VERSION 5.8 ;
BUSBITCHARS "[]" ;
DIVIDERCHAR "/" ;
UNITS
    DATABASE MICRONS 1000 ;
END UNITS

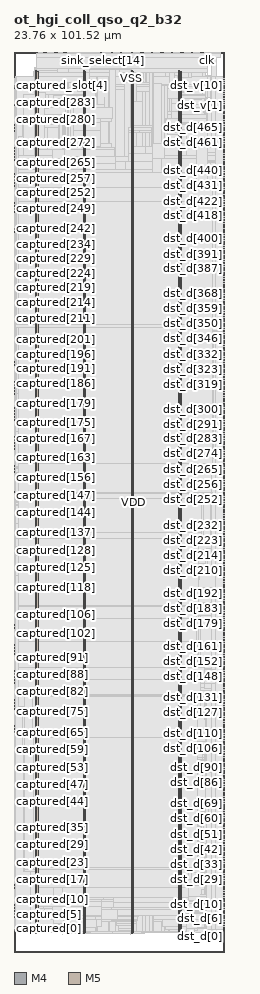
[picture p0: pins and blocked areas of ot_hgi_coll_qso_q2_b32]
MACRO ot_hgi_coll_qso_q2_b32
  FOREIGN ot_hgi_coll_qso_q2_b32 0 0 ;
  CLASS BLOCK ;
  SIZE 23.76 BY 101.52 ;
  PIN captured[0]
    DIRECTION INPUT ;
    USE SIGNAL ;
    PORT
      LAYER M4 ;
        RECT  0 2.64 0.084 2.664 ;
    END
  END captured[0]
  PIN captured[100]
    DIRECTION INPUT ;
    USE SIGNAL ;
    PORT
      LAYER M4 ;
        RECT  0 35.232 0.084 35.256 ;
    END
  END captured[100]
  PIN captured[101]
    DIRECTION INPUT ;
    USE SIGNAL ;
    PORT
      LAYER M4 ;
        RECT  0 35.568 0.084 35.592 ;
    END
  END captured[101]
  PIN captured[102]
    DIRECTION INPUT ;
    USE SIGNAL ;
    PORT
      LAYER M4 ;
        RECT  0 35.904 0.084 35.928 ;
    END
  END captured[102]
  PIN captured[103]
    DIRECTION INPUT ;
    USE SIGNAL ;
    PORT
      LAYER M4 ;
        RECT  0 36.24 0.084 36.264 ;
    END
  END captured[103]
  PIN captured[104]
    DIRECTION INPUT ;
    USE SIGNAL ;
    PORT
      LAYER M4 ;
        RECT  0 36.528 0.084 36.552 ;
    END
  END captured[104]
  PIN captured[105]
    DIRECTION INPUT ;
    USE SIGNAL ;
    PORT
      LAYER M4 ;
        RECT  0 36.864 0.084 36.888 ;
    END
  END captured[105]
  PIN captured[106]
    DIRECTION INPUT ;
    USE SIGNAL ;
    PORT
      LAYER M4 ;
        RECT  0 37.2 0.084 37.224 ;
    END
  END captured[106]
  PIN captured[107]
    DIRECTION INPUT ;
    USE SIGNAL ;
    PORT
      LAYER M4 ;
        RECT  0 37.536 0.084 37.56 ;
    END
  END captured[107]
  PIN captured[108]
    DIRECTION INPUT ;
    USE SIGNAL ;
    PORT
      LAYER M4 ;
        RECT  0 37.872 0.084 37.896 ;
    END
  END captured[108]
  PIN captured[109]
    DIRECTION INPUT ;
    USE SIGNAL ;
    PORT
      LAYER M4 ;
        RECT  0 38.16 0.084 38.184 ;
    END
  END captured[109]
  PIN captured[10]
    DIRECTION INPUT ;
    USE SIGNAL ;
    PORT
      LAYER M4 ;
        RECT  0 5.904 0.084 5.928 ;
    END
  END captured[10]
  PIN captured[110]
    DIRECTION INPUT ;
    USE SIGNAL ;
    PORT
      LAYER M4 ;
        RECT  0 38.496 0.084 38.52 ;
    END
  END captured[110]
  PIN captured[111]
    DIRECTION INPUT ;
    USE SIGNAL ;
    PORT
      LAYER M4 ;
        RECT  0 38.832 0.084 38.856 ;
    END
  END captured[111]
  PIN captured[112]
    DIRECTION INPUT ;
    USE SIGNAL ;
    PORT
      LAYER M4 ;
        RECT  0 39.168 0.084 39.192 ;
    END
  END captured[112]
  PIN captured[113]
    DIRECTION INPUT ;
    USE SIGNAL ;
    PORT
      LAYER M4 ;
        RECT  0 39.504 0.084 39.528 ;
    END
  END captured[113]
  PIN captured[114]
    DIRECTION INPUT ;
    USE SIGNAL ;
    PORT
      LAYER M4 ;
        RECT  0 39.792 0.084 39.816 ;
    END
  END captured[114]
  PIN captured[115]
    DIRECTION INPUT ;
    USE SIGNAL ;
    PORT
      LAYER M4 ;
        RECT  0 40.128 0.084 40.152 ;
    END
  END captured[115]
  PIN captured[116]
    DIRECTION INPUT ;
    USE SIGNAL ;
    PORT
      LAYER M4 ;
        RECT  0 40.464 0.084 40.488 ;
    END
  END captured[116]
  PIN captured[117]
    DIRECTION INPUT ;
    USE SIGNAL ;
    PORT
      LAYER M4 ;
        RECT  0 40.8 0.084 40.824 ;
    END
  END captured[117]
  PIN captured[118]
    DIRECTION INPUT ;
    USE SIGNAL ;
    PORT
      LAYER M4 ;
        RECT  0 41.136 0.084 41.16 ;
    END
  END captured[118]
  PIN captured[119]
    DIRECTION INPUT ;
    USE SIGNAL ;
    PORT
      LAYER M4 ;
        RECT  0 41.424 0.084 41.448 ;
    END
  END captured[119]
  PIN captured[11]
    DIRECTION INPUT ;
    USE SIGNAL ;
    PORT
      LAYER M4 ;
        RECT  0 6.24 0.084 6.264 ;
    END
  END captured[11]
  PIN captured[120]
    DIRECTION INPUT ;
    USE SIGNAL ;
    PORT
      LAYER M4 ;
        RECT  0 41.76 0.084 41.784 ;
    END
  END captured[120]
  PIN captured[121]
    DIRECTION INPUT ;
    USE SIGNAL ;
    PORT
      LAYER M4 ;
        RECT  0 42.096 0.084 42.12 ;
    END
  END captured[121]
  PIN captured[122]
    DIRECTION INPUT ;
    USE SIGNAL ;
    PORT
      LAYER M4 ;
        RECT  0 42.432 0.084 42.456 ;
    END
  END captured[122]
  PIN captured[123]
    DIRECTION INPUT ;
    USE SIGNAL ;
    PORT
      LAYER M4 ;
        RECT  0 42.72 0.084 42.744 ;
    END
  END captured[123]
  PIN captured[124]
    DIRECTION INPUT ;
    USE SIGNAL ;
    PORT
      LAYER M4 ;
        RECT  0 43.056 0.084 43.08 ;
    END
  END captured[124]
  PIN captured[125]
    DIRECTION INPUT ;
    USE SIGNAL ;
    PORT
      LAYER M4 ;
        RECT  0 43.392 0.084 43.416 ;
    END
  END captured[125]
  PIN captured[126]
    DIRECTION INPUT ;
    USE SIGNAL ;
    PORT
      LAYER M4 ;
        RECT  0 43.728 0.084 43.752 ;
    END
  END captured[126]
  PIN captured[127]
    DIRECTION INPUT ;
    USE SIGNAL ;
    PORT
      LAYER M4 ;
        RECT  0 44.064 0.084 44.088 ;
    END
  END captured[127]
  PIN captured[128]
    DIRECTION INPUT ;
    USE SIGNAL ;
    PORT
      LAYER M4 ;
        RECT  0 44.352 0.084 44.376 ;
    END
  END captured[128]
  PIN captured[129]
    DIRECTION INPUT ;
    USE SIGNAL ;
    PORT
      LAYER M4 ;
        RECT  0 44.688 0.084 44.712 ;
    END
  END captured[129]
  PIN captured[12]
    DIRECTION INPUT ;
    USE SIGNAL ;
    PORT
      LAYER M4 ;
        RECT  0 6.576 0.084 6.6 ;
    END
  END captured[12]
  PIN captured[130]
    DIRECTION INPUT ;
    USE SIGNAL ;
    PORT
      LAYER M4 ;
        RECT  0 45.024 0.084 45.048 ;
    END
  END captured[130]
  PIN captured[131]
    DIRECTION INPUT ;
    USE SIGNAL ;
    PORT
      LAYER M4 ;
        RECT  0 45.36 0.084 45.384 ;
    END
  END captured[131]
  PIN captured[132]
    DIRECTION INPUT ;
    USE SIGNAL ;
    PORT
      LAYER M4 ;
        RECT  0 45.696 0.084 45.72 ;
    END
  END captured[132]
  PIN captured[133]
    DIRECTION INPUT ;
    USE SIGNAL ;
    PORT
      LAYER M4 ;
        RECT  0 45.984 0.084 46.008 ;
    END
  END captured[133]
  PIN captured[134]
    DIRECTION INPUT ;
    USE SIGNAL ;
    PORT
      LAYER M4 ;
        RECT  0 46.32 0.084 46.344 ;
    END
  END captured[134]
  PIN captured[135]
    DIRECTION INPUT ;
    USE SIGNAL ;
    PORT
      LAYER M4 ;
        RECT  0 46.656 0.084 46.68 ;
    END
  END captured[135]
  PIN captured[136]
    DIRECTION INPUT ;
    USE SIGNAL ;
    PORT
      LAYER M4 ;
        RECT  0 46.992 0.084 47.016 ;
    END
  END captured[136]
  PIN captured[137]
    DIRECTION INPUT ;
    USE SIGNAL ;
    PORT
      LAYER M4 ;
        RECT  0 47.328 0.084 47.352 ;
    END
  END captured[137]
  PIN captured[138]
    DIRECTION INPUT ;
    USE SIGNAL ;
    PORT
      LAYER M4 ;
        RECT  0 47.616 0.084 47.64 ;
    END
  END captured[138]
  PIN captured[139]
    DIRECTION INPUT ;
    USE SIGNAL ;
    PORT
      LAYER M4 ;
        RECT  0 47.952 0.084 47.976 ;
    END
  END captured[139]
  PIN captured[13]
    DIRECTION INPUT ;
    USE SIGNAL ;
    PORT
      LAYER M4 ;
        RECT  0 6.912 0.084 6.936 ;
    END
  END captured[13]
  PIN captured[140]
    DIRECTION INPUT ;
    USE SIGNAL ;
    PORT
      LAYER M4 ;
        RECT  0 48.288 0.084 48.312 ;
    END
  END captured[140]
  PIN captured[141]
    DIRECTION INPUT ;
    USE SIGNAL ;
    PORT
      LAYER M4 ;
        RECT  0 48.624 0.084 48.648 ;
    END
  END captured[141]
  PIN captured[142]
    DIRECTION INPUT ;
    USE SIGNAL ;
    PORT
      LAYER M4 ;
        RECT  0 48.912 0.084 48.936 ;
    END
  END captured[142]
  PIN captured[143]
    DIRECTION INPUT ;
    USE SIGNAL ;
    PORT
      LAYER M4 ;
        RECT  0 49.248 0.084 49.272 ;
    END
  END captured[143]
  PIN captured[144]
    DIRECTION INPUT ;
    USE SIGNAL ;
    PORT
      LAYER M4 ;
        RECT  0 49.584 0.084 49.608 ;
    END
  END captured[144]
  PIN captured[145]
    DIRECTION INPUT ;
    USE SIGNAL ;
    PORT
      LAYER M4 ;
        RECT  0 49.92 0.084 49.944 ;
    END
  END captured[145]
  PIN captured[146]
    DIRECTION INPUT ;
    USE SIGNAL ;
    PORT
      LAYER M4 ;
        RECT  0 50.256 0.084 50.28 ;
    END
  END captured[146]
  PIN captured[147]
    DIRECTION INPUT ;
    USE SIGNAL ;
    PORT
      LAYER M4 ;
        RECT  0 50.544 0.084 50.568 ;
    END
  END captured[147]
  PIN captured[148]
    DIRECTION INPUT ;
    USE SIGNAL ;
    PORT
      LAYER M4 ;
        RECT  0 50.88 0.084 50.904 ;
    END
  END captured[148]
  PIN captured[149]
    DIRECTION INPUT ;
    USE SIGNAL ;
    PORT
      LAYER M4 ;
        RECT  0 51.216 0.084 51.24 ;
    END
  END captured[149]
  PIN captured[14]
    DIRECTION INPUT ;
    USE SIGNAL ;
    PORT
      LAYER M4 ;
        RECT  0 7.2 0.084 7.224 ;
    END
  END captured[14]
  PIN captured[150]
    DIRECTION INPUT ;
    USE SIGNAL ;
    PORT
      LAYER M4 ;
        RECT  0 51.552 0.084 51.576 ;
    END
  END captured[150]
  PIN captured[151]
    DIRECTION INPUT ;
    USE SIGNAL ;
    PORT
      LAYER M4 ;
        RECT  0 51.888 0.084 51.912 ;
    END
  END captured[151]
  PIN captured[152]
    DIRECTION INPUT ;
    USE SIGNAL ;
    PORT
      LAYER M4 ;
        RECT  0 52.176 0.084 52.2 ;
    END
  END captured[152]
  PIN captured[153]
    DIRECTION INPUT ;
    USE SIGNAL ;
    PORT
      LAYER M4 ;
        RECT  0 52.512 0.084 52.536 ;
    END
  END captured[153]
  PIN captured[154]
    DIRECTION INPUT ;
    USE SIGNAL ;
    PORT
      LAYER M4 ;
        RECT  0 52.848 0.084 52.872 ;
    END
  END captured[154]
  PIN captured[155]
    DIRECTION INPUT ;
    USE SIGNAL ;
    PORT
      LAYER M4 ;
        RECT  0 53.184 0.084 53.208 ;
    END
  END captured[155]
  PIN captured[156]
    DIRECTION INPUT ;
    USE SIGNAL ;
    PORT
      LAYER M4 ;
        RECT  0 53.52 0.084 53.544 ;
    END
  END captured[156]
  PIN captured[157]
    DIRECTION INPUT ;
    USE SIGNAL ;
    PORT
      LAYER M4 ;
        RECT  0 53.808 0.084 53.832 ;
    END
  END captured[157]
  PIN captured[158]
    DIRECTION INPUT ;
    USE SIGNAL ;
    PORT
      LAYER M4 ;
        RECT  0 54.144 0.084 54.168 ;
    END
  END captured[158]
  PIN captured[159]
    DIRECTION INPUT ;
    USE SIGNAL ;
    PORT
      LAYER M4 ;
        RECT  0 54.48 0.084 54.504 ;
    END
  END captured[159]
  PIN captured[15]
    DIRECTION INPUT ;
    USE SIGNAL ;
    PORT
      LAYER M4 ;
        RECT  0 7.536 0.084 7.56 ;
    END
  END captured[15]
  PIN captured[160]
    DIRECTION INPUT ;
    USE SIGNAL ;
    PORT
      LAYER M4 ;
        RECT  0 54.816 0.084 54.84 ;
    END
  END captured[160]
  PIN captured[161]
    DIRECTION INPUT ;
    USE SIGNAL ;
    PORT
      LAYER M4 ;
        RECT  0 55.104 0.084 55.128 ;
    END
  END captured[161]
  PIN captured[162]
    DIRECTION INPUT ;
    USE SIGNAL ;
    PORT
      LAYER M4 ;
        RECT  0 55.44 0.084 55.464 ;
    END
  END captured[162]
  PIN captured[163]
    DIRECTION INPUT ;
    USE SIGNAL ;
    PORT
      LAYER M4 ;
        RECT  0 55.776 0.084 55.8 ;
    END
  END captured[163]
  PIN captured[164]
    DIRECTION INPUT ;
    USE SIGNAL ;
    PORT
      LAYER M4 ;
        RECT  0 56.112 0.084 56.136 ;
    END
  END captured[164]
  PIN captured[165]
    DIRECTION INPUT ;
    USE SIGNAL ;
    PORT
      LAYER M4 ;
        RECT  0 56.448 0.084 56.472 ;
    END
  END captured[165]
  PIN captured[166]
    DIRECTION INPUT ;
    USE SIGNAL ;
    PORT
      LAYER M4 ;
        RECT  0 56.736 0.084 56.76 ;
    END
  END captured[166]
  PIN captured[167]
    DIRECTION INPUT ;
    USE SIGNAL ;
    PORT
      LAYER M4 ;
        RECT  0 57.072 0.084 57.096 ;
    END
  END captured[167]
  PIN captured[168]
    DIRECTION INPUT ;
    USE SIGNAL ;
    PORT
      LAYER M4 ;
        RECT  0 57.408 0.084 57.432 ;
    END
  END captured[168]
  PIN captured[169]
    DIRECTION INPUT ;
    USE SIGNAL ;
    PORT
      LAYER M4 ;
        RECT  0 57.744 0.084 57.768 ;
    END
  END captured[169]
  PIN captured[16]
    DIRECTION INPUT ;
    USE SIGNAL ;
    PORT
      LAYER M4 ;
        RECT  0 7.872 0.084 7.896 ;
    END
  END captured[16]
  PIN captured[170]
    DIRECTION INPUT ;
    USE SIGNAL ;
    PORT
      LAYER M4 ;
        RECT  0 58.08 0.084 58.104 ;
    END
  END captured[170]
  PIN captured[171]
    DIRECTION INPUT ;
    USE SIGNAL ;
    PORT
      LAYER M4 ;
        RECT  0 58.368 0.084 58.392 ;
    END
  END captured[171]
  PIN captured[172]
    DIRECTION INPUT ;
    USE SIGNAL ;
    PORT
      LAYER M4 ;
        RECT  0 58.704 0.084 58.728 ;
    END
  END captured[172]
  PIN captured[173]
    DIRECTION INPUT ;
    USE SIGNAL ;
    PORT
      LAYER M4 ;
        RECT  0 59.04 0.084 59.064 ;
    END
  END captured[173]
  PIN captured[174]
    DIRECTION INPUT ;
    USE SIGNAL ;
    PORT
      LAYER M4 ;
        RECT  0 59.376 0.084 59.4 ;
    END
  END captured[174]
  PIN captured[175]
    DIRECTION INPUT ;
    USE SIGNAL ;
    PORT
      LAYER M4 ;
        RECT  0 59.712 0.084 59.736 ;
    END
  END captured[175]
  PIN captured[176]
    DIRECTION INPUT ;
    USE SIGNAL ;
    PORT
      LAYER M4 ;
        RECT  0 60 0.084 60.024 ;
    END
  END captured[176]
  PIN captured[177]
    DIRECTION INPUT ;
    USE SIGNAL ;
    PORT
      LAYER M4 ;
        RECT  0 60.336 0.084 60.36 ;
    END
  END captured[177]
  PIN captured[178]
    DIRECTION INPUT ;
    USE SIGNAL ;
    PORT
      LAYER M4 ;
        RECT  0 60.672 0.084 60.696 ;
    END
  END captured[178]
  PIN captured[179]
    DIRECTION INPUT ;
    USE SIGNAL ;
    PORT
      LAYER M4 ;
        RECT  0 61.008 0.084 61.032 ;
    END
  END captured[179]
  PIN captured[17]
    DIRECTION INPUT ;
    USE SIGNAL ;
    PORT
      LAYER M4 ;
        RECT  0 8.208 0.084 8.232 ;
    END
  END captured[17]
  PIN captured[180]
    DIRECTION INPUT ;
    USE SIGNAL ;
    PORT
      LAYER M4 ;
        RECT  0 61.344 0.084 61.368 ;
    END
  END captured[180]
  PIN captured[181]
    DIRECTION INPUT ;
    USE SIGNAL ;
    PORT
      LAYER M4 ;
        RECT  0 61.632 0.084 61.656 ;
    END
  END captured[181]
  PIN captured[182]
    DIRECTION INPUT ;
    USE SIGNAL ;
    PORT
      LAYER M4 ;
        RECT  0 61.968 0.084 61.992 ;
    END
  END captured[182]
  PIN captured[183]
    DIRECTION INPUT ;
    USE SIGNAL ;
    PORT
      LAYER M4 ;
        RECT  0 62.304 0.084 62.328 ;
    END
  END captured[183]
  PIN captured[184]
    DIRECTION INPUT ;
    USE SIGNAL ;
    PORT
      LAYER M4 ;
        RECT  0 62.64 0.084 62.664 ;
    END
  END captured[184]
  PIN captured[185]
    DIRECTION INPUT ;
    USE SIGNAL ;
    PORT
      LAYER M4 ;
        RECT  0 62.928 0.084 62.952 ;
    END
  END captured[185]
  PIN captured[186]
    DIRECTION INPUT ;
    USE SIGNAL ;
    PORT
      LAYER M4 ;
        RECT  0 63.264 0.084 63.288 ;
    END
  END captured[186]
  PIN captured[187]
    DIRECTION INPUT ;
    USE SIGNAL ;
    PORT
      LAYER M4 ;
        RECT  0 63.6 0.084 63.624 ;
    END
  END captured[187]
  PIN captured[188]
    DIRECTION INPUT ;
    USE SIGNAL ;
    PORT
      LAYER M4 ;
        RECT  0 63.936 0.084 63.96 ;
    END
  END captured[188]
  PIN captured[189]
    DIRECTION INPUT ;
    USE SIGNAL ;
    PORT
      LAYER M4 ;
        RECT  0 64.272 0.084 64.296 ;
    END
  END captured[189]
  PIN captured[18]
    DIRECTION INPUT ;
    USE SIGNAL ;
    PORT
      LAYER M4 ;
        RECT  0 8.496 0.084 8.52 ;
    END
  END captured[18]
  PIN captured[190]
    DIRECTION INPUT ;
    USE SIGNAL ;
    PORT
      LAYER M4 ;
        RECT  0 64.56 0.084 64.584 ;
    END
  END captured[190]
  PIN captured[191]
    DIRECTION INPUT ;
    USE SIGNAL ;
    PORT
      LAYER M4 ;
        RECT  0 64.896 0.084 64.92 ;
    END
  END captured[191]
  PIN captured[192]
    DIRECTION INPUT ;
    USE SIGNAL ;
    PORT
      LAYER M4 ;
        RECT  0 65.232 0.084 65.256 ;
    END
  END captured[192]
  PIN captured[193]
    DIRECTION INPUT ;
    USE SIGNAL ;
    PORT
      LAYER M4 ;
        RECT  0 65.568 0.084 65.592 ;
    END
  END captured[193]
  PIN captured[194]
    DIRECTION INPUT ;
    USE SIGNAL ;
    PORT
      LAYER M4 ;
        RECT  0 65.904 0.084 65.928 ;
    END
  END captured[194]
  PIN captured[195]
    DIRECTION INPUT ;
    USE SIGNAL ;
    PORT
      LAYER M4 ;
        RECT  0 66.192 0.084 66.216 ;
    END
  END captured[195]
  PIN captured[196]
    DIRECTION INPUT ;
    USE SIGNAL ;
    PORT
      LAYER M4 ;
        RECT  0 66.528 0.084 66.552 ;
    END
  END captured[196]
  PIN captured[197]
    DIRECTION INPUT ;
    USE SIGNAL ;
    PORT
      LAYER M4 ;
        RECT  0 66.864 0.084 66.888 ;
    END
  END captured[197]
  PIN captured[198]
    DIRECTION INPUT ;
    USE SIGNAL ;
    PORT
      LAYER M4 ;
        RECT  0 67.2 0.084 67.224 ;
    END
  END captured[198]
  PIN captured[199]
    DIRECTION INPUT ;
    USE SIGNAL ;
    PORT
      LAYER M4 ;
        RECT  0 67.536 0.084 67.56 ;
    END
  END captured[199]
  PIN captured[19]
    DIRECTION INPUT ;
    USE SIGNAL ;
    PORT
      LAYER M4 ;
        RECT  0 8.832 0.084 8.856 ;
    END
  END captured[19]
  PIN captured[1]
    DIRECTION INPUT ;
    USE SIGNAL ;
    PORT
      LAYER M4 ;
        RECT  0 2.976 0.084 3 ;
    END
  END captured[1]
  PIN captured[200]
    DIRECTION INPUT ;
    USE SIGNAL ;
    PORT
      LAYER M4 ;
        RECT  0 67.824 0.084 67.848 ;
    END
  END captured[200]
  PIN captured[201]
    DIRECTION INPUT ;
    USE SIGNAL ;
    PORT
      LAYER M4 ;
        RECT  0 68.16 0.084 68.184 ;
    END
  END captured[201]
  PIN captured[202]
    DIRECTION INPUT ;
    USE SIGNAL ;
    PORT
      LAYER M4 ;
        RECT  0 68.496 0.084 68.52 ;
    END
  END captured[202]
  PIN captured[203]
    DIRECTION INPUT ;
    USE SIGNAL ;
    PORT
      LAYER M4 ;
        RECT  0 68.832 0.084 68.856 ;
    END
  END captured[203]
  PIN captured[204]
    DIRECTION INPUT ;
    USE SIGNAL ;
    PORT
      LAYER M4 ;
        RECT  0 69.12 0.084 69.144 ;
    END
  END captured[204]
  PIN captured[205]
    DIRECTION INPUT ;
    USE SIGNAL ;
    PORT
      LAYER M4 ;
        RECT  0 69.456 0.084 69.48 ;
    END
  END captured[205]
  PIN captured[206]
    DIRECTION INPUT ;
    USE SIGNAL ;
    PORT
      LAYER M4 ;
        RECT  0 69.792 0.084 69.816 ;
    END
  END captured[206]
  PIN captured[207]
    DIRECTION INPUT ;
    USE SIGNAL ;
    PORT
      LAYER M4 ;
        RECT  0 70.128 0.084 70.152 ;
    END
  END captured[207]
  PIN captured[208]
    DIRECTION INPUT ;
    USE SIGNAL ;
    PORT
      LAYER M4 ;
        RECT  0 70.464 0.084 70.488 ;
    END
  END captured[208]
  PIN captured[209]
    DIRECTION INPUT ;
    USE SIGNAL ;
    PORT
      LAYER M4 ;
        RECT  0 70.752 0.084 70.776 ;
    END
  END captured[209]
  PIN captured[20]
    DIRECTION INPUT ;
    USE SIGNAL ;
    PORT
      LAYER M4 ;
        RECT  0 9.168 0.084 9.192 ;
    END
  END captured[20]
  PIN captured[210]
    DIRECTION INPUT ;
    USE SIGNAL ;
    PORT
      LAYER M4 ;
        RECT  0 71.088 0.084 71.112 ;
    END
  END captured[210]
  PIN captured[211]
    DIRECTION INPUT ;
    USE SIGNAL ;
    PORT
      LAYER M4 ;
        RECT  0 71.424 0.084 71.448 ;
    END
  END captured[211]
  PIN captured[212]
    DIRECTION INPUT ;
    USE SIGNAL ;
    PORT
      LAYER M4 ;
        RECT  0 71.76 0.084 71.784 ;
    END
  END captured[212]
  PIN captured[213]
    DIRECTION INPUT ;
    USE SIGNAL ;
    PORT
      LAYER M4 ;
        RECT  0 72.096 0.084 72.12 ;
    END
  END captured[213]
  PIN captured[214]
    DIRECTION INPUT ;
    USE SIGNAL ;
    PORT
      LAYER M4 ;
        RECT  0 72.384 0.084 72.408 ;
    END
  END captured[214]
  PIN captured[215]
    DIRECTION INPUT ;
    USE SIGNAL ;
    PORT
      LAYER M4 ;
        RECT  0 72.72 0.084 72.744 ;
    END
  END captured[215]
  PIN captured[216]
    DIRECTION INPUT ;
    USE SIGNAL ;
    PORT
      LAYER M4 ;
        RECT  0 73.056 0.084 73.08 ;
    END
  END captured[216]
  PIN captured[217]
    DIRECTION INPUT ;
    USE SIGNAL ;
    PORT
      LAYER M4 ;
        RECT  0 73.392 0.084 73.416 ;
    END
  END captured[217]
  PIN captured[218]
    DIRECTION INPUT ;
    USE SIGNAL ;
    PORT
      LAYER M4 ;
        RECT  0 73.728 0.084 73.752 ;
    END
  END captured[218]
  PIN captured[219]
    DIRECTION INPUT ;
    USE SIGNAL ;
    PORT
      LAYER M4 ;
        RECT  0 74.016 0.084 74.04 ;
    END
  END captured[219]
  PIN captured[21]
    DIRECTION INPUT ;
    USE SIGNAL ;
    PORT
      LAYER M4 ;
        RECT  0 9.504 0.084 9.528 ;
    END
  END captured[21]
  PIN captured[220]
    DIRECTION INPUT ;
    USE SIGNAL ;
    PORT
      LAYER M4 ;
        RECT  0 74.352 0.084 74.376 ;
    END
  END captured[220]
  PIN captured[221]
    DIRECTION INPUT ;
    USE SIGNAL ;
    PORT
      LAYER M4 ;
        RECT  0 74.688 0.084 74.712 ;
    END
  END captured[221]
  PIN captured[222]
    DIRECTION INPUT ;
    USE SIGNAL ;
    PORT
      LAYER M4 ;
        RECT  0 75.024 0.084 75.048 ;
    END
  END captured[222]
  PIN captured[223]
    DIRECTION INPUT ;
    USE SIGNAL ;
    PORT
      LAYER M4 ;
        RECT  0 75.312 0.084 75.336 ;
    END
  END captured[223]
  PIN captured[224]
    DIRECTION INPUT ;
    USE SIGNAL ;
    PORT
      LAYER M4 ;
        RECT  0 75.648 0.084 75.672 ;
    END
  END captured[224]
  PIN captured[225]
    DIRECTION INPUT ;
    USE SIGNAL ;
    PORT
      LAYER M4 ;
        RECT  0 75.984 0.084 76.008 ;
    END
  END captured[225]
  PIN captured[226]
    DIRECTION INPUT ;
    USE SIGNAL ;
    PORT
      LAYER M4 ;
        RECT  0 76.32 0.084 76.344 ;
    END
  END captured[226]
  PIN captured[227]
    DIRECTION INPUT ;
    USE SIGNAL ;
    PORT
      LAYER M4 ;
        RECT  0 76.656 0.084 76.68 ;
    END
  END captured[227]
  PIN captured[228]
    DIRECTION INPUT ;
    USE SIGNAL ;
    PORT
      LAYER M4 ;
        RECT  0 76.944 0.084 76.968 ;
    END
  END captured[228]
  PIN captured[229]
    DIRECTION INPUT ;
    USE SIGNAL ;
    PORT
      LAYER M4 ;
        RECT  0 77.28 0.084 77.304 ;
    END
  END captured[229]
  PIN captured[22]
    DIRECTION INPUT ;
    USE SIGNAL ;
    PORT
      LAYER M4 ;
        RECT  0 9.84 0.084 9.864 ;
    END
  END captured[22]
  PIN captured[230]
    DIRECTION INPUT ;
    USE SIGNAL ;
    PORT
      LAYER M4 ;
        RECT  0 77.616 0.084 77.64 ;
    END
  END captured[230]
  PIN captured[231]
    DIRECTION INPUT ;
    USE SIGNAL ;
    PORT
      LAYER M4 ;
        RECT  0 77.952 0.084 77.976 ;
    END
  END captured[231]
  PIN captured[232]
    DIRECTION INPUT ;
    USE SIGNAL ;
    PORT
      LAYER M4 ;
        RECT  0 78.288 0.084 78.312 ;
    END
  END captured[232]
  PIN captured[233]
    DIRECTION INPUT ;
    USE SIGNAL ;
    PORT
      LAYER M4 ;
        RECT  0 78.576 0.084 78.6 ;
    END
  END captured[233]
  PIN captured[234]
    DIRECTION INPUT ;
    USE SIGNAL ;
    PORT
      LAYER M4 ;
        RECT  0 78.912 0.084 78.936 ;
    END
  END captured[234]
  PIN captured[235]
    DIRECTION INPUT ;
    USE SIGNAL ;
    PORT
      LAYER M4 ;
        RECT  0 79.248 0.084 79.272 ;
    END
  END captured[235]
  PIN captured[236]
    DIRECTION INPUT ;
    USE SIGNAL ;
    PORT
      LAYER M4 ;
        RECT  0 79.584 0.084 79.608 ;
    END
  END captured[236]
  PIN captured[237]
    DIRECTION INPUT ;
    USE SIGNAL ;
    PORT
      LAYER M4 ;
        RECT  0 79.92 0.084 79.944 ;
    END
  END captured[237]
  PIN captured[238]
    DIRECTION INPUT ;
    USE SIGNAL ;
    PORT
      LAYER M4 ;
        RECT  0 80.208 0.084 80.232 ;
    END
  END captured[238]
  PIN captured[239]
    DIRECTION INPUT ;
    USE SIGNAL ;
    PORT
      LAYER M4 ;
        RECT  0 80.544 0.084 80.568 ;
    END
  END captured[239]
  PIN captured[23]
    DIRECTION INPUT ;
    USE SIGNAL ;
    PORT
      LAYER M4 ;
        RECT  0 10.128 0.084 10.152 ;
    END
  END captured[23]
  PIN captured[240]
    DIRECTION INPUT ;
    USE SIGNAL ;
    PORT
      LAYER M4 ;
        RECT  0 80.88 0.084 80.904 ;
    END
  END captured[240]
  PIN captured[241]
    DIRECTION INPUT ;
    USE SIGNAL ;
    PORT
      LAYER M4 ;
        RECT  0 81.216 0.084 81.24 ;
    END
  END captured[241]
  PIN captured[242]
    DIRECTION INPUT ;
    USE SIGNAL ;
    PORT
      LAYER M4 ;
        RECT  0 81.552 0.084 81.576 ;
    END
  END captured[242]
  PIN captured[243]
    DIRECTION INPUT ;
    USE SIGNAL ;
    PORT
      LAYER M4 ;
        RECT  0 81.84 0.084 81.864 ;
    END
  END captured[243]
  PIN captured[244]
    DIRECTION INPUT ;
    USE SIGNAL ;
    PORT
      LAYER M4 ;
        RECT  0 82.176 0.084 82.2 ;
    END
  END captured[244]
  PIN captured[245]
    DIRECTION INPUT ;
    USE SIGNAL ;
    PORT
      LAYER M4 ;
        RECT  0 82.512 0.084 82.536 ;
    END
  END captured[245]
  PIN captured[246]
    DIRECTION INPUT ;
    USE SIGNAL ;
    PORT
      LAYER M4 ;
        RECT  0 82.848 0.084 82.872 ;
    END
  END captured[246]
  PIN captured[247]
    DIRECTION INPUT ;
    USE SIGNAL ;
    PORT
      LAYER M4 ;
        RECT  0 83.136 0.084 83.16 ;
    END
  END captured[247]
  PIN captured[248]
    DIRECTION INPUT ;
    USE SIGNAL ;
    PORT
      LAYER M4 ;
        RECT  0 83.472 0.084 83.496 ;
    END
  END captured[248]
  PIN captured[249]
    DIRECTION INPUT ;
    USE SIGNAL ;
    PORT
      LAYER M4 ;
        RECT  0 83.808 0.084 83.832 ;
    END
  END captured[249]
  PIN captured[24]
    DIRECTION INPUT ;
    USE SIGNAL ;
    PORT
      LAYER M4 ;
        RECT  0 10.464 0.084 10.488 ;
    END
  END captured[24]
  PIN captured[250]
    DIRECTION INPUT ;
    USE SIGNAL ;
    PORT
      LAYER M4 ;
        RECT  0 84.144 0.084 84.168 ;
    END
  END captured[250]
  PIN captured[251]
    DIRECTION INPUT ;
    USE SIGNAL ;
    PORT
      LAYER M4 ;
        RECT  0 84.48 0.084 84.504 ;
    END
  END captured[251]
  PIN captured[252]
    DIRECTION INPUT ;
    USE SIGNAL ;
    PORT
      LAYER M4 ;
        RECT  0 84.768 0.084 84.792 ;
    END
  END captured[252]
  PIN captured[253]
    DIRECTION INPUT ;
    USE SIGNAL ;
    PORT
      LAYER M4 ;
        RECT  0 85.104 0.084 85.128 ;
    END
  END captured[253]
  PIN captured[254]
    DIRECTION INPUT ;
    USE SIGNAL ;
    PORT
      LAYER M4 ;
        RECT  0 85.44 0.084 85.464 ;
    END
  END captured[254]
  PIN captured[255]
    DIRECTION INPUT ;
    USE SIGNAL ;
    PORT
      LAYER M4 ;
        RECT  0 85.776 0.084 85.8 ;
    END
  END captured[255]
  PIN captured[256]
    DIRECTION INPUT ;
    USE SIGNAL ;
    PORT
      LAYER M4 ;
        RECT  0 86.112 0.084 86.136 ;
    END
  END captured[256]
  PIN captured[257]
    DIRECTION INPUT ;
    USE SIGNAL ;
    PORT
      LAYER M4 ;
        RECT  0 86.4 0.084 86.424 ;
    END
  END captured[257]
  PIN captured[258]
    DIRECTION INPUT ;
    USE SIGNAL ;
    PORT
      LAYER M4 ;
        RECT  0 86.736 0.084 86.76 ;
    END
  END captured[258]
  PIN captured[259]
    DIRECTION INPUT ;
    USE SIGNAL ;
    PORT
      LAYER M4 ;
        RECT  0 87.072 0.084 87.096 ;
    END
  END captured[259]
  PIN captured[25]
    DIRECTION INPUT ;
    USE SIGNAL ;
    PORT
      LAYER M4 ;
        RECT  0 10.8 0.084 10.824 ;
    END
  END captured[25]
  PIN captured[260]
    DIRECTION INPUT ;
    USE SIGNAL ;
    PORT
      LAYER M4 ;
        RECT  0 87.408 0.084 87.432 ;
    END
  END captured[260]
  PIN captured[261]
    DIRECTION INPUT ;
    USE SIGNAL ;
    PORT
      LAYER M4 ;
        RECT  0 87.744 0.084 87.768 ;
    END
  END captured[261]
  PIN captured[262]
    DIRECTION INPUT ;
    USE SIGNAL ;
    PORT
      LAYER M4 ;
        RECT  0 88.032 0.084 88.056 ;
    END
  END captured[262]
  PIN captured[263]
    DIRECTION INPUT ;
    USE SIGNAL ;
    PORT
      LAYER M4 ;
        RECT  0 88.368 0.084 88.392 ;
    END
  END captured[263]
  PIN captured[264]
    DIRECTION INPUT ;
    USE SIGNAL ;
    PORT
      LAYER M4 ;
        RECT  0 88.704 0.084 88.728 ;
    END
  END captured[264]
  PIN captured[265]
    DIRECTION INPUT ;
    USE SIGNAL ;
    PORT
      LAYER M4 ;
        RECT  0 89.04 0.084 89.064 ;
    END
  END captured[265]
  PIN captured[266]
    DIRECTION INPUT ;
    USE SIGNAL ;
    PORT
      LAYER M4 ;
        RECT  0 89.328 0.084 89.352 ;
    END
  END captured[266]
  PIN captured[267]
    DIRECTION INPUT ;
    USE SIGNAL ;
    PORT
      LAYER M4 ;
        RECT  0 89.664 0.084 89.688 ;
    END
  END captured[267]
  PIN captured[268]
    DIRECTION INPUT ;
    USE SIGNAL ;
    PORT
      LAYER M4 ;
        RECT  0 90 0.084 90.024 ;
    END
  END captured[268]
  PIN captured[269]
    DIRECTION INPUT ;
    USE SIGNAL ;
    PORT
      LAYER M4 ;
        RECT  0 90.336 0.084 90.36 ;
    END
  END captured[269]
  PIN captured[26]
    DIRECTION INPUT ;
    USE SIGNAL ;
    PORT
      LAYER M4 ;
        RECT  0 11.136 0.084 11.16 ;
    END
  END captured[26]
  PIN captured[270]
    DIRECTION INPUT ;
    USE SIGNAL ;
    PORT
      LAYER M4 ;
        RECT  0 90.672 0.084 90.696 ;
    END
  END captured[270]
  PIN captured[271]
    DIRECTION INPUT ;
    USE SIGNAL ;
    PORT
      LAYER M4 ;
        RECT  0 90.96 0.084 90.984 ;
    END
  END captured[271]
  PIN captured[272]
    DIRECTION INPUT ;
    USE SIGNAL ;
    PORT
      LAYER M4 ;
        RECT  0 91.296 0.084 91.32 ;
    END
  END captured[272]
  PIN captured[273]
    DIRECTION INPUT ;
    USE SIGNAL ;
    PORT
      LAYER M4 ;
        RECT  0 91.632 0.084 91.656 ;
    END
  END captured[273]
  PIN captured[274]
    DIRECTION INPUT ;
    USE SIGNAL ;
    PORT
      LAYER M4 ;
        RECT  0 91.968 0.084 91.992 ;
    END
  END captured[274]
  PIN captured[275]
    DIRECTION INPUT ;
    USE SIGNAL ;
    PORT
      LAYER M4 ;
        RECT  0 92.304 0.084 92.328 ;
    END
  END captured[275]
  PIN captured[276]
    DIRECTION INPUT ;
    USE SIGNAL ;
    PORT
      LAYER M4 ;
        RECT  0 92.592 0.084 92.616 ;
    END
  END captured[276]
  PIN captured[277]
    DIRECTION INPUT ;
    USE SIGNAL ;
    PORT
      LAYER M4 ;
        RECT  0 92.928 0.084 92.952 ;
    END
  END captured[277]
  PIN captured[278]
    DIRECTION INPUT ;
    USE SIGNAL ;
    PORT
      LAYER M4 ;
        RECT  0 93.264 0.084 93.288 ;
    END
  END captured[278]
  PIN captured[279]
    DIRECTION INPUT ;
    USE SIGNAL ;
    PORT
      LAYER M4 ;
        RECT  0 93.6 0.084 93.624 ;
    END
  END captured[279]
  PIN captured[27]
    DIRECTION INPUT ;
    USE SIGNAL ;
    PORT
      LAYER M4 ;
        RECT  0 11.472 0.084 11.496 ;
    END
  END captured[27]
  PIN captured[280]
    DIRECTION INPUT ;
    USE SIGNAL ;
    PORT
      LAYER M4 ;
        RECT  0 93.936 0.084 93.96 ;
    END
  END captured[280]
  PIN captured[281]
    DIRECTION INPUT ;
    USE SIGNAL ;
    PORT
      LAYER M4 ;
        RECT  0 94.224 0.084 94.248 ;
    END
  END captured[281]
  PIN captured[282]
    DIRECTION INPUT ;
    USE SIGNAL ;
    PORT
      LAYER M4 ;
        RECT  0 94.56 0.084 94.584 ;
    END
  END captured[282]
  PIN captured[283]
    DIRECTION INPUT ;
    USE SIGNAL ;
    PORT
      LAYER M4 ;
        RECT  0 94.896 0.084 94.92 ;
    END
  END captured[283]
  PIN captured[284]
    DIRECTION INPUT ;
    USE SIGNAL ;
    PORT
      LAYER M4 ;
        RECT  0 95.232 0.084 95.256 ;
    END
  END captured[284]
  PIN captured[285]
    DIRECTION INPUT ;
    USE SIGNAL ;
    PORT
      LAYER M4 ;
        RECT  0 95.52 0.084 95.544 ;
    END
  END captured[285]
  PIN captured[286]
    DIRECTION INPUT ;
    USE SIGNAL ;
    PORT
      LAYER M4 ;
        RECT  0 95.856 0.084 95.88 ;
    END
  END captured[286]
  PIN captured[287]
    DIRECTION INPUT ;
    USE SIGNAL ;
    PORT
      LAYER M4 ;
        RECT  0 96.192 0.084 96.216 ;
    END
  END captured[287]
  PIN captured[28]
    DIRECTION INPUT ;
    USE SIGNAL ;
    PORT
      LAYER M4 ;
        RECT  0 11.76 0.084 11.784 ;
    END
  END captured[28]
  PIN captured[29]
    DIRECTION INPUT ;
    USE SIGNAL ;
    PORT
      LAYER M4 ;
        RECT  0 12.096 0.084 12.12 ;
    END
  END captured[29]
  PIN captured[2]
    DIRECTION INPUT ;
    USE SIGNAL ;
    PORT
      LAYER M4 ;
        RECT  0 3.312 0.084 3.336 ;
    END
  END captured[2]
  PIN captured[30]
    DIRECTION INPUT ;
    USE SIGNAL ;
    PORT
      LAYER M4 ;
        RECT  0 12.432 0.084 12.456 ;
    END
  END captured[30]
  PIN captured[31]
    DIRECTION INPUT ;
    USE SIGNAL ;
    PORT
      LAYER M4 ;
        RECT  0 12.768 0.084 12.792 ;
    END
  END captured[31]
  PIN captured[32]
    DIRECTION INPUT ;
    USE SIGNAL ;
    PORT
      LAYER M4 ;
        RECT  0 13.104 0.084 13.128 ;
    END
  END captured[32]
  PIN captured[33]
    DIRECTION INPUT ;
    USE SIGNAL ;
    PORT
      LAYER M4 ;
        RECT  0 13.392 0.084 13.416 ;
    END
  END captured[33]
  PIN captured[34]
    DIRECTION INPUT ;
    USE SIGNAL ;
    PORT
      LAYER M4 ;
        RECT  0 13.728 0.084 13.752 ;
    END
  END captured[34]
  PIN captured[35]
    DIRECTION INPUT ;
    USE SIGNAL ;
    PORT
      LAYER M4 ;
        RECT  0 14.064 0.084 14.088 ;
    END
  END captured[35]
  PIN captured[36]
    DIRECTION INPUT ;
    USE SIGNAL ;
    PORT
      LAYER M4 ;
        RECT  0 14.4 0.084 14.424 ;
    END
  END captured[36]
  PIN captured[37]
    DIRECTION INPUT ;
    USE SIGNAL ;
    PORT
      LAYER M4 ;
        RECT  0 14.688 0.084 14.712 ;
    END
  END captured[37]
  PIN captured[38]
    DIRECTION INPUT ;
    USE SIGNAL ;
    PORT
      LAYER M4 ;
        RECT  0 15.024 0.084 15.048 ;
    END
  END captured[38]
  PIN captured[39]
    DIRECTION INPUT ;
    USE SIGNAL ;
    PORT
      LAYER M4 ;
        RECT  0 15.36 0.084 15.384 ;
    END
  END captured[39]
  PIN captured[3]
    DIRECTION INPUT ;
    USE SIGNAL ;
    PORT
      LAYER M4 ;
        RECT  0 3.648 0.084 3.672 ;
    END
  END captured[3]
  PIN captured[40]
    DIRECTION INPUT ;
    USE SIGNAL ;
    PORT
      LAYER M4 ;
        RECT  0 15.696 0.084 15.72 ;
    END
  END captured[40]
  PIN captured[41]
    DIRECTION INPUT ;
    USE SIGNAL ;
    PORT
      LAYER M4 ;
        RECT  0 16.032 0.084 16.056 ;
    END
  END captured[41]
  PIN captured[42]
    DIRECTION INPUT ;
    USE SIGNAL ;
    PORT
      LAYER M4 ;
        RECT  0 16.32 0.084 16.344 ;
    END
  END captured[42]
  PIN captured[43]
    DIRECTION INPUT ;
    USE SIGNAL ;
    PORT
      LAYER M4 ;
        RECT  0 16.656 0.084 16.68 ;
    END
  END captured[43]
  PIN captured[44]
    DIRECTION INPUT ;
    USE SIGNAL ;
    PORT
      LAYER M4 ;
        RECT  0 16.992 0.084 17.016 ;
    END
  END captured[44]
  PIN captured[45]
    DIRECTION INPUT ;
    USE SIGNAL ;
    PORT
      LAYER M4 ;
        RECT  0 17.328 0.084 17.352 ;
    END
  END captured[45]
  PIN captured[46]
    DIRECTION INPUT ;
    USE SIGNAL ;
    PORT
      LAYER M4 ;
        RECT  0 17.664 0.084 17.688 ;
    END
  END captured[46]
  PIN captured[47]
    DIRECTION INPUT ;
    USE SIGNAL ;
    PORT
      LAYER M4 ;
        RECT  0 17.952 0.084 17.976 ;
    END
  END captured[47]
  PIN captured[48]
    DIRECTION INPUT ;
    USE SIGNAL ;
    PORT
      LAYER M4 ;
        RECT  0 18.288 0.084 18.312 ;
    END
  END captured[48]
  PIN captured[49]
    DIRECTION INPUT ;
    USE SIGNAL ;
    PORT
      LAYER M4 ;
        RECT  0 18.624 0.084 18.648 ;
    END
  END captured[49]
  PIN captured[4]
    DIRECTION INPUT ;
    USE SIGNAL ;
    PORT
      LAYER M4 ;
        RECT  0 3.936 0.084 3.96 ;
    END
  END captured[4]
  PIN captured[50]
    DIRECTION INPUT ;
    USE SIGNAL ;
    PORT
      LAYER M4 ;
        RECT  0 18.96 0.084 18.984 ;
    END
  END captured[50]
  PIN captured[51]
    DIRECTION INPUT ;
    USE SIGNAL ;
    PORT
      LAYER M4 ;
        RECT  0 19.296 0.084 19.32 ;
    END
  END captured[51]
  PIN captured[52]
    DIRECTION INPUT ;
    USE SIGNAL ;
    PORT
      LAYER M4 ;
        RECT  0 19.584 0.084 19.608 ;
    END
  END captured[52]
  PIN captured[53]
    DIRECTION INPUT ;
    USE SIGNAL ;
    PORT
      LAYER M4 ;
        RECT  0 19.92 0.084 19.944 ;
    END
  END captured[53]
  PIN captured[54]
    DIRECTION INPUT ;
    USE SIGNAL ;
    PORT
      LAYER M4 ;
        RECT  0 20.256 0.084 20.28 ;
    END
  END captured[54]
  PIN captured[55]
    DIRECTION INPUT ;
    USE SIGNAL ;
    PORT
      LAYER M4 ;
        RECT  0 20.592 0.084 20.616 ;
    END
  END captured[55]
  PIN captured[56]
    DIRECTION INPUT ;
    USE SIGNAL ;
    PORT
      LAYER M4 ;
        RECT  0 20.88 0.084 20.904 ;
    END
  END captured[56]
  PIN captured[57]
    DIRECTION INPUT ;
    USE SIGNAL ;
    PORT
      LAYER M4 ;
        RECT  0 21.216 0.084 21.24 ;
    END
  END captured[57]
  PIN captured[58]
    DIRECTION INPUT ;
    USE SIGNAL ;
    PORT
      LAYER M4 ;
        RECT  0 21.552 0.084 21.576 ;
    END
  END captured[58]
  PIN captured[59]
    DIRECTION INPUT ;
    USE SIGNAL ;
    PORT
      LAYER M4 ;
        RECT  0 21.888 0.084 21.912 ;
    END
  END captured[59]
  PIN captured[5]
    DIRECTION INPUT ;
    USE SIGNAL ;
    PORT
      LAYER M4 ;
        RECT  0 4.272 0.084 4.296 ;
    END
  END captured[5]
  PIN captured[60]
    DIRECTION INPUT ;
    USE SIGNAL ;
    PORT
      LAYER M4 ;
        RECT  0 22.224 0.084 22.248 ;
    END
  END captured[60]
  PIN captured[61]
    DIRECTION INPUT ;
    USE SIGNAL ;
    PORT
      LAYER M4 ;
        RECT  0 22.512 0.084 22.536 ;
    END
  END captured[61]
  PIN captured[62]
    DIRECTION INPUT ;
    USE SIGNAL ;
    PORT
      LAYER M4 ;
        RECT  0 22.848 0.084 22.872 ;
    END
  END captured[62]
  PIN captured[63]
    DIRECTION INPUT ;
    USE SIGNAL ;
    PORT
      LAYER M4 ;
        RECT  0 23.184 0.084 23.208 ;
    END
  END captured[63]
  PIN captured[64]
    DIRECTION INPUT ;
    USE SIGNAL ;
    PORT
      LAYER M4 ;
        RECT  0 23.52 0.084 23.544 ;
    END
  END captured[64]
  PIN captured[65]
    DIRECTION INPUT ;
    USE SIGNAL ;
    PORT
      LAYER M4 ;
        RECT  0 23.856 0.084 23.88 ;
    END
  END captured[65]
  PIN captured[66]
    DIRECTION INPUT ;
    USE SIGNAL ;
    PORT
      LAYER M4 ;
        RECT  0 24.144 0.084 24.168 ;
    END
  END captured[66]
  PIN captured[67]
    DIRECTION INPUT ;
    USE SIGNAL ;
    PORT
      LAYER M4 ;
        RECT  0 24.48 0.084 24.504 ;
    END
  END captured[67]
  PIN captured[68]
    DIRECTION INPUT ;
    USE SIGNAL ;
    PORT
      LAYER M4 ;
        RECT  0 24.816 0.084 24.84 ;
    END
  END captured[68]
  PIN captured[69]
    DIRECTION INPUT ;
    USE SIGNAL ;
    PORT
      LAYER M4 ;
        RECT  0 25.152 0.084 25.176 ;
    END
  END captured[69]
  PIN captured[6]
    DIRECTION INPUT ;
    USE SIGNAL ;
    PORT
      LAYER M4 ;
        RECT  0 4.608 0.084 4.632 ;
    END
  END captured[6]
  PIN captured[70]
    DIRECTION INPUT ;
    USE SIGNAL ;
    PORT
      LAYER M4 ;
        RECT  0 25.488 0.084 25.512 ;
    END
  END captured[70]
  PIN captured[71]
    DIRECTION INPUT ;
    USE SIGNAL ;
    PORT
      LAYER M4 ;
        RECT  0 25.776 0.084 25.8 ;
    END
  END captured[71]
  PIN captured[72]
    DIRECTION INPUT ;
    USE SIGNAL ;
    PORT
      LAYER M4 ;
        RECT  0 26.112 0.084 26.136 ;
    END
  END captured[72]
  PIN captured[73]
    DIRECTION INPUT ;
    USE SIGNAL ;
    PORT
      LAYER M4 ;
        RECT  0 26.448 0.084 26.472 ;
    END
  END captured[73]
  PIN captured[74]
    DIRECTION INPUT ;
    USE SIGNAL ;
    PORT
      LAYER M4 ;
        RECT  0 26.784 0.084 26.808 ;
    END
  END captured[74]
  PIN captured[75]
    DIRECTION INPUT ;
    USE SIGNAL ;
    PORT
      LAYER M4 ;
        RECT  0 27.12 0.084 27.144 ;
    END
  END captured[75]
  PIN captured[76]
    DIRECTION INPUT ;
    USE SIGNAL ;
    PORT
      LAYER M4 ;
        RECT  0 27.408 0.084 27.432 ;
    END
  END captured[76]
  PIN captured[77]
    DIRECTION INPUT ;
    USE SIGNAL ;
    PORT
      LAYER M4 ;
        RECT  0 27.744 0.084 27.768 ;
    END
  END captured[77]
  PIN captured[78]
    DIRECTION INPUT ;
    USE SIGNAL ;
    PORT
      LAYER M4 ;
        RECT  0 28.08 0.084 28.104 ;
    END
  END captured[78]
  PIN captured[79]
    DIRECTION INPUT ;
    USE SIGNAL ;
    PORT
      LAYER M4 ;
        RECT  0 28.416 0.084 28.44 ;
    END
  END captured[79]
  PIN captured[7]
    DIRECTION INPUT ;
    USE SIGNAL ;
    PORT
      LAYER M4 ;
        RECT  0 4.944 0.084 4.968 ;
    END
  END captured[7]
  PIN captured[80]
    DIRECTION INPUT ;
    USE SIGNAL ;
    PORT
      LAYER M4 ;
        RECT  0 28.704 0.084 28.728 ;
    END
  END captured[80]
  PIN captured[81]
    DIRECTION INPUT ;
    USE SIGNAL ;
    PORT
      LAYER M4 ;
        RECT  0 29.04 0.084 29.064 ;
    END
  END captured[81]
  PIN captured[82]
    DIRECTION INPUT ;
    USE SIGNAL ;
    PORT
      LAYER M4 ;
        RECT  0 29.376 0.084 29.4 ;
    END
  END captured[82]
  PIN captured[83]
    DIRECTION INPUT ;
    USE SIGNAL ;
    PORT
      LAYER M4 ;
        RECT  0 29.712 0.084 29.736 ;
    END
  END captured[83]
  PIN captured[84]
    DIRECTION INPUT ;
    USE SIGNAL ;
    PORT
      LAYER M4 ;
        RECT  0 30.048 0.084 30.072 ;
    END
  END captured[84]
  PIN captured[85]
    DIRECTION INPUT ;
    USE SIGNAL ;
    PORT
      LAYER M4 ;
        RECT  0 30.336 0.084 30.36 ;
    END
  END captured[85]
  PIN captured[86]
    DIRECTION INPUT ;
    USE SIGNAL ;
    PORT
      LAYER M4 ;
        RECT  0 30.672 0.084 30.696 ;
    END
  END captured[86]
  PIN captured[87]
    DIRECTION INPUT ;
    USE SIGNAL ;
    PORT
      LAYER M4 ;
        RECT  0 31.008 0.084 31.032 ;
    END
  END captured[87]
  PIN captured[88]
    DIRECTION INPUT ;
    USE SIGNAL ;
    PORT
      LAYER M4 ;
        RECT  0 31.344 0.084 31.368 ;
    END
  END captured[88]
  PIN captured[89]
    DIRECTION INPUT ;
    USE SIGNAL ;
    PORT
      LAYER M4 ;
        RECT  0 31.68 0.084 31.704 ;
    END
  END captured[89]
  PIN captured[8]
    DIRECTION INPUT ;
    USE SIGNAL ;
    PORT
      LAYER M4 ;
        RECT  0 5.28 0.084 5.304 ;
    END
  END captured[8]
  PIN captured[90]
    DIRECTION INPUT ;
    USE SIGNAL ;
    PORT
      LAYER M4 ;
        RECT  0 31.968 0.084 31.992 ;
    END
  END captured[90]
  PIN captured[91]
    DIRECTION INPUT ;
    USE SIGNAL ;
    PORT
      LAYER M4 ;
        RECT  0 32.304 0.084 32.328 ;
    END
  END captured[91]
  PIN captured[92]
    DIRECTION INPUT ;
    USE SIGNAL ;
    PORT
      LAYER M4 ;
        RECT  0 32.64 0.084 32.664 ;
    END
  END captured[92]
  PIN captured[93]
    DIRECTION INPUT ;
    USE SIGNAL ;
    PORT
      LAYER M4 ;
        RECT  0 32.976 0.084 33 ;
    END
  END captured[93]
  PIN captured[94]
    DIRECTION INPUT ;
    USE SIGNAL ;
    PORT
      LAYER M4 ;
        RECT  0 33.312 0.084 33.336 ;
    END
  END captured[94]
  PIN captured[95]
    DIRECTION INPUT ;
    USE SIGNAL ;
    PORT
      LAYER M4 ;
        RECT  0 33.6 0.084 33.624 ;
    END
  END captured[95]
  PIN captured[96]
    DIRECTION INPUT ;
    USE SIGNAL ;
    PORT
      LAYER M4 ;
        RECT  0 33.936 0.084 33.96 ;
    END
  END captured[96]
  PIN captured[97]
    DIRECTION INPUT ;
    USE SIGNAL ;
    PORT
      LAYER M4 ;
        RECT  0 34.272 0.084 34.296 ;
    END
  END captured[97]
  PIN captured[98]
    DIRECTION INPUT ;
    USE SIGNAL ;
    PORT
      LAYER M4 ;
        RECT  0 34.608 0.084 34.632 ;
    END
  END captured[98]
  PIN captured[99]
    DIRECTION INPUT ;
    USE SIGNAL ;
    PORT
      LAYER M4 ;
        RECT  0 34.896 0.084 34.92 ;
    END
  END captured[99]
  PIN captured[9]
    DIRECTION INPUT ;
    USE SIGNAL ;
    PORT
      LAYER M4 ;
        RECT  0 5.568 0.084 5.592 ;
    END
  END captured[9]
  PIN captured_slot[0]
    DIRECTION INPUT ;
    USE SIGNAL ;
    PORT
      LAYER M4 ;
        RECT  0 96.672 0.084 96.696 ;
    END
  END captured_slot[0]
  PIN captured_slot[1]
    DIRECTION INPUT ;
    USE SIGNAL ;
    PORT
      LAYER M4 ;
        RECT  0 96.912 0.084 96.936 ;
    END
  END captured_slot[1]
  PIN captured_slot[2]
    DIRECTION INPUT ;
    USE SIGNAL ;
    PORT
      LAYER M4 ;
        RECT  0 97.2 0.084 97.224 ;
    END
  END captured_slot[2]
  PIN captured_slot[3]
    DIRECTION INPUT ;
    USE SIGNAL ;
    PORT
      LAYER M4 ;
        RECT  0 97.44 0.084 97.464 ;
    END
  END captured_slot[3]
  PIN captured_slot[4]
    DIRECTION INPUT ;
    USE SIGNAL ;
    PORT
      LAYER M4 ;
        RECT  0 97.68 0.084 97.704 ;
    END
  END captured_slot[4]
  PIN captured_slot[5]
    DIRECTION INPUT ;
    USE SIGNAL ;
    PORT
      LAYER M4 ;
        RECT  0 97.92 0.084 97.944 ;
    END
  END captured_slot[5]
  PIN captured_slot[6]
    DIRECTION INPUT ;
    USE SIGNAL ;
    PORT
      LAYER M4 ;
        RECT  0 98.16 0.084 98.184 ;
    END
  END captured_slot[6]
  PIN captured_slot[7]
    DIRECTION INPUT ;
    USE SIGNAL ;
    PORT
      LAYER M4 ;
        RECT  0 98.448 0.084 98.472 ;
    END
  END captured_slot[7]
  PIN captured_slot[8]
    DIRECTION INPUT ;
    USE SIGNAL ;
    PORT
      LAYER M4 ;
        RECT  0 98.688 0.084 98.712 ;
    END
  END captured_slot[8]
  PIN clk
    DIRECTION INPUT ;
    USE SIGNAL ;
    PORT
      LAYER M5 ;
        RECT  21.792 101.436 21.816 101.52 ;
    END
  END clk
  PIN dst_d[0]
    DIRECTION OUTPUT ;
    USE SIGNAL ;
    PORT
      LAYER M4 ;
        RECT  23.676 2.592 23.76 2.616 ;
    END
  END dst_d[0]
  PIN dst_d[100]
    DIRECTION OUTPUT ;
    USE SIGNAL ;
    PORT
      LAYER M4 ;
        RECT  23.676 21.84 23.76 21.864 ;
    END
  END dst_d[100]
  PIN dst_d[101]
    DIRECTION OUTPUT ;
    USE SIGNAL ;
    PORT
      LAYER M4 ;
        RECT  23.676 22.032 23.76 22.056 ;
    END
  END dst_d[101]
  PIN dst_d[102]
    DIRECTION OUTPUT ;
    USE SIGNAL ;
    PORT
      LAYER M4 ;
        RECT  23.676 22.224 23.76 22.248 ;
    END
  END dst_d[102]
  PIN dst_d[103]
    DIRECTION OUTPUT ;
    USE SIGNAL ;
    PORT
      LAYER M4 ;
        RECT  23.676 22.416 23.76 22.44 ;
    END
  END dst_d[103]
  PIN dst_d[104]
    DIRECTION OUTPUT ;
    USE SIGNAL ;
    PORT
      LAYER M4 ;
        RECT  23.676 22.608 23.76 22.632 ;
    END
  END dst_d[104]
  PIN dst_d[105]
    DIRECTION OUTPUT ;
    USE SIGNAL ;
    PORT
      LAYER M4 ;
        RECT  23.676 22.8 23.76 22.824 ;
    END
  END dst_d[105]
  PIN dst_d[106]
    DIRECTION OUTPUT ;
    USE SIGNAL ;
    PORT
      LAYER M4 ;
        RECT  23.676 22.992 23.76 23.016 ;
    END
  END dst_d[106]
  PIN dst_d[107]
    DIRECTION OUTPUT ;
    USE SIGNAL ;
    PORT
      LAYER M4 ;
        RECT  23.676 23.184 23.76 23.208 ;
    END
  END dst_d[107]
  PIN dst_d[108]
    DIRECTION OUTPUT ;
    USE SIGNAL ;
    PORT
      LAYER M4 ;
        RECT  23.676 23.376 23.76 23.4 ;
    END
  END dst_d[108]
  PIN dst_d[109]
    DIRECTION OUTPUT ;
    USE SIGNAL ;
    PORT
      LAYER M4 ;
        RECT  23.676 23.568 23.76 23.592 ;
    END
  END dst_d[109]
  PIN dst_d[10]
    DIRECTION OUTPUT ;
    USE SIGNAL ;
    PORT
      LAYER M4 ;
        RECT  23.676 4.512 23.76 4.536 ;
    END
  END dst_d[10]
  PIN dst_d[110]
    DIRECTION OUTPUT ;
    USE SIGNAL ;
    PORT
      LAYER M4 ;
        RECT  23.676 23.76 23.76 23.784 ;
    END
  END dst_d[110]
  PIN dst_d[111]
    DIRECTION OUTPUT ;
    USE SIGNAL ;
    PORT
      LAYER M4 ;
        RECT  23.676 23.952 23.76 23.976 ;
    END
  END dst_d[111]
  PIN dst_d[112]
    DIRECTION OUTPUT ;
    USE SIGNAL ;
    PORT
      LAYER M4 ;
        RECT  23.676 24.144 23.76 24.168 ;
    END
  END dst_d[112]
  PIN dst_d[113]
    DIRECTION OUTPUT ;
    USE SIGNAL ;
    PORT
      LAYER M4 ;
        RECT  23.676 24.336 23.76 24.36 ;
    END
  END dst_d[113]
  PIN dst_d[114]
    DIRECTION OUTPUT ;
    USE SIGNAL ;
    PORT
      LAYER M4 ;
        RECT  23.676 24.528 23.76 24.552 ;
    END
  END dst_d[114]
  PIN dst_d[115]
    DIRECTION OUTPUT ;
    USE SIGNAL ;
    PORT
      LAYER M4 ;
        RECT  23.676 24.72 23.76 24.744 ;
    END
  END dst_d[115]
  PIN dst_d[116]
    DIRECTION OUTPUT ;
    USE SIGNAL ;
    PORT
      LAYER M4 ;
        RECT  23.676 24.912 23.76 24.936 ;
    END
  END dst_d[116]
  PIN dst_d[117]
    DIRECTION OUTPUT ;
    USE SIGNAL ;
    PORT
      LAYER M4 ;
        RECT  23.676 25.104 23.76 25.128 ;
    END
  END dst_d[117]
  PIN dst_d[118]
    DIRECTION OUTPUT ;
    USE SIGNAL ;
    PORT
      LAYER M4 ;
        RECT  23.676 25.296 23.76 25.32 ;
    END
  END dst_d[118]
  PIN dst_d[119]
    DIRECTION OUTPUT ;
    USE SIGNAL ;
    PORT
      LAYER M4 ;
        RECT  23.676 25.488 23.76 25.512 ;
    END
  END dst_d[119]
  PIN dst_d[11]
    DIRECTION OUTPUT ;
    USE SIGNAL ;
    PORT
      LAYER M4 ;
        RECT  23.676 4.704 23.76 4.728 ;
    END
  END dst_d[11]
  PIN dst_d[120]
    DIRECTION OUTPUT ;
    USE SIGNAL ;
    PORT
      LAYER M4 ;
        RECT  23.676 25.68 23.76 25.704 ;
    END
  END dst_d[120]
  PIN dst_d[121]
    DIRECTION OUTPUT ;
    USE SIGNAL ;
    PORT
      LAYER M4 ;
        RECT  23.676 25.872 23.76 25.896 ;
    END
  END dst_d[121]
  PIN dst_d[122]
    DIRECTION OUTPUT ;
    USE SIGNAL ;
    PORT
      LAYER M4 ;
        RECT  23.676 26.064 23.76 26.088 ;
    END
  END dst_d[122]
  PIN dst_d[123]
    DIRECTION OUTPUT ;
    USE SIGNAL ;
    PORT
      LAYER M4 ;
        RECT  23.676 26.256 23.76 26.28 ;
    END
  END dst_d[123]
  PIN dst_d[124]
    DIRECTION OUTPUT ;
    USE SIGNAL ;
    PORT
      LAYER M4 ;
        RECT  23.676 26.448 23.76 26.472 ;
    END
  END dst_d[124]
  PIN dst_d[125]
    DIRECTION OUTPUT ;
    USE SIGNAL ;
    PORT
      LAYER M4 ;
        RECT  23.676 26.64 23.76 26.664 ;
    END
  END dst_d[125]
  PIN dst_d[126]
    DIRECTION OUTPUT ;
    USE SIGNAL ;
    PORT
      LAYER M4 ;
        RECT  23.676 26.832 23.76 26.856 ;
    END
  END dst_d[126]
  PIN dst_d[127]
    DIRECTION OUTPUT ;
    USE SIGNAL ;
    PORT
      LAYER M4 ;
        RECT  23.676 27.024 23.76 27.048 ;
    END
  END dst_d[127]
  PIN dst_d[128]
    DIRECTION OUTPUT ;
    USE SIGNAL ;
    PORT
      LAYER M4 ;
        RECT  23.676 27.216 23.76 27.24 ;
    END
  END dst_d[128]
  PIN dst_d[129]
    DIRECTION OUTPUT ;
    USE SIGNAL ;
    PORT
      LAYER M4 ;
        RECT  23.676 27.408 23.76 27.432 ;
    END
  END dst_d[129]
  PIN dst_d[12]
    DIRECTION OUTPUT ;
    USE SIGNAL ;
    PORT
      LAYER M4 ;
        RECT  23.676 4.896 23.76 4.92 ;
    END
  END dst_d[12]
  PIN dst_d[130]
    DIRECTION OUTPUT ;
    USE SIGNAL ;
    PORT
      LAYER M4 ;
        RECT  23.676 27.6 23.76 27.624 ;
    END
  END dst_d[130]
  PIN dst_d[131]
    DIRECTION OUTPUT ;
    USE SIGNAL ;
    PORT
      LAYER M4 ;
        RECT  23.676 27.792 23.76 27.816 ;
    END
  END dst_d[131]
  PIN dst_d[132]
    DIRECTION OUTPUT ;
    USE SIGNAL ;
    PORT
      LAYER M4 ;
        RECT  23.676 27.984 23.76 28.008 ;
    END
  END dst_d[132]
  PIN dst_d[133]
    DIRECTION OUTPUT ;
    USE SIGNAL ;
    PORT
      LAYER M4 ;
        RECT  23.676 28.176 23.76 28.2 ;
    END
  END dst_d[133]
  PIN dst_d[134]
    DIRECTION OUTPUT ;
    USE SIGNAL ;
    PORT
      LAYER M4 ;
        RECT  23.676 28.368 23.76 28.392 ;
    END
  END dst_d[134]
  PIN dst_d[135]
    DIRECTION OUTPUT ;
    USE SIGNAL ;
    PORT
      LAYER M4 ;
        RECT  23.676 28.56 23.76 28.584 ;
    END
  END dst_d[135]
  PIN dst_d[136]
    DIRECTION OUTPUT ;
    USE SIGNAL ;
    PORT
      LAYER M4 ;
        RECT  23.676 28.752 23.76 28.776 ;
    END
  END dst_d[136]
  PIN dst_d[137]
    DIRECTION OUTPUT ;
    USE SIGNAL ;
    PORT
      LAYER M4 ;
        RECT  23.676 28.944 23.76 28.968 ;
    END
  END dst_d[137]
  PIN dst_d[138]
    DIRECTION OUTPUT ;
    USE SIGNAL ;
    PORT
      LAYER M4 ;
        RECT  23.676 29.136 23.76 29.16 ;
    END
  END dst_d[138]
  PIN dst_d[139]
    DIRECTION OUTPUT ;
    USE SIGNAL ;
    PORT
      LAYER M4 ;
        RECT  23.676 29.328 23.76 29.352 ;
    END
  END dst_d[139]
  PIN dst_d[13]
    DIRECTION OUTPUT ;
    USE SIGNAL ;
    PORT
      LAYER M4 ;
        RECT  23.676 5.088 23.76 5.112 ;
    END
  END dst_d[13]
  PIN dst_d[140]
    DIRECTION OUTPUT ;
    USE SIGNAL ;
    PORT
      LAYER M4 ;
        RECT  23.676 29.52 23.76 29.544 ;
    END
  END dst_d[140]
  PIN dst_d[141]
    DIRECTION OUTPUT ;
    USE SIGNAL ;
    PORT
      LAYER M4 ;
        RECT  23.676 29.712 23.76 29.736 ;
    END
  END dst_d[141]
  PIN dst_d[142]
    DIRECTION OUTPUT ;
    USE SIGNAL ;
    PORT
      LAYER M4 ;
        RECT  23.676 29.904 23.76 29.928 ;
    END
  END dst_d[142]
  PIN dst_d[143]
    DIRECTION OUTPUT ;
    USE SIGNAL ;
    PORT
      LAYER M4 ;
        RECT  23.676 30.096 23.76 30.12 ;
    END
  END dst_d[143]
  PIN dst_d[144]
    DIRECTION OUTPUT ;
    USE SIGNAL ;
    PORT
      LAYER M4 ;
        RECT  23.676 30.288 23.76 30.312 ;
    END
  END dst_d[144]
  PIN dst_d[145]
    DIRECTION OUTPUT ;
    USE SIGNAL ;
    PORT
      LAYER M4 ;
        RECT  23.676 30.48 23.76 30.504 ;
    END
  END dst_d[145]
  PIN dst_d[146]
    DIRECTION OUTPUT ;
    USE SIGNAL ;
    PORT
      LAYER M4 ;
        RECT  23.676 30.672 23.76 30.696 ;
    END
  END dst_d[146]
  PIN dst_d[147]
    DIRECTION OUTPUT ;
    USE SIGNAL ;
    PORT
      LAYER M4 ;
        RECT  23.676 30.864 23.76 30.888 ;
    END
  END dst_d[147]
  PIN dst_d[148]
    DIRECTION OUTPUT ;
    USE SIGNAL ;
    PORT
      LAYER M4 ;
        RECT  23.676 31.056 23.76 31.08 ;
    END
  END dst_d[148]
  PIN dst_d[149]
    DIRECTION OUTPUT ;
    USE SIGNAL ;
    PORT
      LAYER M4 ;
        RECT  23.676 31.248 23.76 31.272 ;
    END
  END dst_d[149]
  PIN dst_d[14]
    DIRECTION OUTPUT ;
    USE SIGNAL ;
    PORT
      LAYER M4 ;
        RECT  23.676 5.28 23.76 5.304 ;
    END
  END dst_d[14]
  PIN dst_d[150]
    DIRECTION OUTPUT ;
    USE SIGNAL ;
    PORT
      LAYER M4 ;
        RECT  23.676 31.44 23.76 31.464 ;
    END
  END dst_d[150]
  PIN dst_d[151]
    DIRECTION OUTPUT ;
    USE SIGNAL ;
    PORT
      LAYER M4 ;
        RECT  23.676 31.632 23.76 31.656 ;
    END
  END dst_d[151]
  PIN dst_d[152]
    DIRECTION OUTPUT ;
    USE SIGNAL ;
    PORT
      LAYER M4 ;
        RECT  23.676 31.824 23.76 31.848 ;
    END
  END dst_d[152]
  PIN dst_d[153]
    DIRECTION OUTPUT ;
    USE SIGNAL ;
    PORT
      LAYER M4 ;
        RECT  23.676 32.016 23.76 32.04 ;
    END
  END dst_d[153]
  PIN dst_d[154]
    DIRECTION OUTPUT ;
    USE SIGNAL ;
    PORT
      LAYER M4 ;
        RECT  23.676 32.208 23.76 32.232 ;
    END
  END dst_d[154]
  PIN dst_d[155]
    DIRECTION OUTPUT ;
    USE SIGNAL ;
    PORT
      LAYER M4 ;
        RECT  23.676 32.4 23.76 32.424 ;
    END
  END dst_d[155]
  PIN dst_d[156]
    DIRECTION OUTPUT ;
    USE SIGNAL ;
    PORT
      LAYER M4 ;
        RECT  23.676 32.592 23.76 32.616 ;
    END
  END dst_d[156]
  PIN dst_d[157]
    DIRECTION OUTPUT ;
    USE SIGNAL ;
    PORT
      LAYER M4 ;
        RECT  23.676 32.784 23.76 32.808 ;
    END
  END dst_d[157]
  PIN dst_d[158]
    DIRECTION OUTPUT ;
    USE SIGNAL ;
    PORT
      LAYER M4 ;
        RECT  23.676 32.976 23.76 33 ;
    END
  END dst_d[158]
  PIN dst_d[159]
    DIRECTION OUTPUT ;
    USE SIGNAL ;
    PORT
      LAYER M4 ;
        RECT  23.676 33.168 23.76 33.192 ;
    END
  END dst_d[159]
  PIN dst_d[15]
    DIRECTION OUTPUT ;
    USE SIGNAL ;
    PORT
      LAYER M4 ;
        RECT  23.676 5.472 23.76 5.496 ;
    END
  END dst_d[15]
  PIN dst_d[160]
    DIRECTION OUTPUT ;
    USE SIGNAL ;
    PORT
      LAYER M4 ;
        RECT  23.676 33.36 23.76 33.384 ;
    END
  END dst_d[160]
  PIN dst_d[161]
    DIRECTION OUTPUT ;
    USE SIGNAL ;
    PORT
      LAYER M4 ;
        RECT  23.676 33.552 23.76 33.576 ;
    END
  END dst_d[161]
  PIN dst_d[162]
    DIRECTION OUTPUT ;
    USE SIGNAL ;
    PORT
      LAYER M4 ;
        RECT  23.676 33.744 23.76 33.768 ;
    END
  END dst_d[162]
  PIN dst_d[163]
    DIRECTION OUTPUT ;
    USE SIGNAL ;
    PORT
      LAYER M4 ;
        RECT  23.676 33.936 23.76 33.96 ;
    END
  END dst_d[163]
  PIN dst_d[164]
    DIRECTION OUTPUT ;
    USE SIGNAL ;
    PORT
      LAYER M4 ;
        RECT  23.676 34.128 23.76 34.152 ;
    END
  END dst_d[164]
  PIN dst_d[165]
    DIRECTION OUTPUT ;
    USE SIGNAL ;
    PORT
      LAYER M4 ;
        RECT  23.676 34.32 23.76 34.344 ;
    END
  END dst_d[165]
  PIN dst_d[166]
    DIRECTION OUTPUT ;
    USE SIGNAL ;
    PORT
      LAYER M4 ;
        RECT  23.676 34.512 23.76 34.536 ;
    END
  END dst_d[166]
  PIN dst_d[167]
    DIRECTION OUTPUT ;
    USE SIGNAL ;
    PORT
      LAYER M4 ;
        RECT  23.676 34.704 23.76 34.728 ;
    END
  END dst_d[167]
  PIN dst_d[168]
    DIRECTION OUTPUT ;
    USE SIGNAL ;
    PORT
      LAYER M4 ;
        RECT  23.676 34.896 23.76 34.92 ;
    END
  END dst_d[168]
  PIN dst_d[169]
    DIRECTION OUTPUT ;
    USE SIGNAL ;
    PORT
      LAYER M4 ;
        RECT  23.676 35.088 23.76 35.112 ;
    END
  END dst_d[169]
  PIN dst_d[16]
    DIRECTION OUTPUT ;
    USE SIGNAL ;
    PORT
      LAYER M4 ;
        RECT  23.676 5.664 23.76 5.688 ;
    END
  END dst_d[16]
  PIN dst_d[170]
    DIRECTION OUTPUT ;
    USE SIGNAL ;
    PORT
      LAYER M4 ;
        RECT  23.676 35.28 23.76 35.304 ;
    END
  END dst_d[170]
  PIN dst_d[171]
    DIRECTION OUTPUT ;
    USE SIGNAL ;
    PORT
      LAYER M4 ;
        RECT  23.676 35.472 23.76 35.496 ;
    END
  END dst_d[171]
  PIN dst_d[172]
    DIRECTION OUTPUT ;
    USE SIGNAL ;
    PORT
      LAYER M4 ;
        RECT  23.676 35.664 23.76 35.688 ;
    END
  END dst_d[172]
  PIN dst_d[173]
    DIRECTION OUTPUT ;
    USE SIGNAL ;
    PORT
      LAYER M4 ;
        RECT  23.676 35.856 23.76 35.88 ;
    END
  END dst_d[173]
  PIN dst_d[174]
    DIRECTION OUTPUT ;
    USE SIGNAL ;
    PORT
      LAYER M4 ;
        RECT  23.676 36.048 23.76 36.072 ;
    END
  END dst_d[174]
  PIN dst_d[175]
    DIRECTION OUTPUT ;
    USE SIGNAL ;
    PORT
      LAYER M4 ;
        RECT  23.676 36.24 23.76 36.264 ;
    END
  END dst_d[175]
  PIN dst_d[176]
    DIRECTION OUTPUT ;
    USE SIGNAL ;
    PORT
      LAYER M4 ;
        RECT  23.676 36.432 23.76 36.456 ;
    END
  END dst_d[176]
  PIN dst_d[177]
    DIRECTION OUTPUT ;
    USE SIGNAL ;
    PORT
      LAYER M4 ;
        RECT  23.676 36.624 23.76 36.648 ;
    END
  END dst_d[177]
  PIN dst_d[178]
    DIRECTION OUTPUT ;
    USE SIGNAL ;
    PORT
      LAYER M4 ;
        RECT  23.676 36.816 23.76 36.84 ;
    END
  END dst_d[178]
  PIN dst_d[179]
    DIRECTION OUTPUT ;
    USE SIGNAL ;
    PORT
      LAYER M4 ;
        RECT  23.676 37.008 23.76 37.032 ;
    END
  END dst_d[179]
  PIN dst_d[17]
    DIRECTION OUTPUT ;
    USE SIGNAL ;
    PORT
      LAYER M4 ;
        RECT  23.676 5.856 23.76 5.88 ;
    END
  END dst_d[17]
  PIN dst_d[180]
    DIRECTION OUTPUT ;
    USE SIGNAL ;
    PORT
      LAYER M4 ;
        RECT  23.676 37.2 23.76 37.224 ;
    END
  END dst_d[180]
  PIN dst_d[181]
    DIRECTION OUTPUT ;
    USE SIGNAL ;
    PORT
      LAYER M4 ;
        RECT  23.676 37.392 23.76 37.416 ;
    END
  END dst_d[181]
  PIN dst_d[182]
    DIRECTION OUTPUT ;
    USE SIGNAL ;
    PORT
      LAYER M4 ;
        RECT  23.676 37.632 23.76 37.656 ;
    END
  END dst_d[182]
  PIN dst_d[183]
    DIRECTION OUTPUT ;
    USE SIGNAL ;
    PORT
      LAYER M4 ;
        RECT  23.676 37.824 23.76 37.848 ;
    END
  END dst_d[183]
  PIN dst_d[184]
    DIRECTION OUTPUT ;
    USE SIGNAL ;
    PORT
      LAYER M4 ;
        RECT  23.676 38.016 23.76 38.04 ;
    END
  END dst_d[184]
  PIN dst_d[185]
    DIRECTION OUTPUT ;
    USE SIGNAL ;
    PORT
      LAYER M4 ;
        RECT  23.676 38.208 23.76 38.232 ;
    END
  END dst_d[185]
  PIN dst_d[186]
    DIRECTION OUTPUT ;
    USE SIGNAL ;
    PORT
      LAYER M4 ;
        RECT  23.676 38.4 23.76 38.424 ;
    END
  END dst_d[186]
  PIN dst_d[187]
    DIRECTION OUTPUT ;
    USE SIGNAL ;
    PORT
      LAYER M4 ;
        RECT  23.676 38.592 23.76 38.616 ;
    END
  END dst_d[187]
  PIN dst_d[188]
    DIRECTION OUTPUT ;
    USE SIGNAL ;
    PORT
      LAYER M4 ;
        RECT  23.676 38.784 23.76 38.808 ;
    END
  END dst_d[188]
  PIN dst_d[189]
    DIRECTION OUTPUT ;
    USE SIGNAL ;
    PORT
      LAYER M4 ;
        RECT  23.676 38.976 23.76 39 ;
    END
  END dst_d[189]
  PIN dst_d[18]
    DIRECTION OUTPUT ;
    USE SIGNAL ;
    PORT
      LAYER M4 ;
        RECT  23.676 6.048 23.76 6.072 ;
    END
  END dst_d[18]
  PIN dst_d[190]
    DIRECTION OUTPUT ;
    USE SIGNAL ;
    PORT
      LAYER M4 ;
        RECT  23.676 39.168 23.76 39.192 ;
    END
  END dst_d[190]
  PIN dst_d[191]
    DIRECTION OUTPUT ;
    USE SIGNAL ;
    PORT
      LAYER M4 ;
        RECT  23.676 39.36 23.76 39.384 ;
    END
  END dst_d[191]
  PIN dst_d[192]
    DIRECTION OUTPUT ;
    USE SIGNAL ;
    PORT
      LAYER M4 ;
        RECT  23.676 39.552 23.76 39.576 ;
    END
  END dst_d[192]
  PIN dst_d[193]
    DIRECTION OUTPUT ;
    USE SIGNAL ;
    PORT
      LAYER M4 ;
        RECT  23.676 39.744 23.76 39.768 ;
    END
  END dst_d[193]
  PIN dst_d[194]
    DIRECTION OUTPUT ;
    USE SIGNAL ;
    PORT
      LAYER M4 ;
        RECT  23.676 39.936 23.76 39.96 ;
    END
  END dst_d[194]
  PIN dst_d[195]
    DIRECTION OUTPUT ;
    USE SIGNAL ;
    PORT
      LAYER M4 ;
        RECT  23.676 40.128 23.76 40.152 ;
    END
  END dst_d[195]
  PIN dst_d[196]
    DIRECTION OUTPUT ;
    USE SIGNAL ;
    PORT
      LAYER M4 ;
        RECT  23.676 40.32 23.76 40.344 ;
    END
  END dst_d[196]
  PIN dst_d[197]
    DIRECTION OUTPUT ;
    USE SIGNAL ;
    PORT
      LAYER M4 ;
        RECT  23.676 40.512 23.76 40.536 ;
    END
  END dst_d[197]
  PIN dst_d[198]
    DIRECTION OUTPUT ;
    USE SIGNAL ;
    PORT
      LAYER M4 ;
        RECT  23.676 40.704 23.76 40.728 ;
    END
  END dst_d[198]
  PIN dst_d[199]
    DIRECTION OUTPUT ;
    USE SIGNAL ;
    PORT
      LAYER M4 ;
        RECT  23.676 40.896 23.76 40.92 ;
    END
  END dst_d[199]
  PIN dst_d[19]
    DIRECTION OUTPUT ;
    USE SIGNAL ;
    PORT
      LAYER M4 ;
        RECT  23.676 6.24 23.76 6.264 ;
    END
  END dst_d[19]
  PIN dst_d[1]
    DIRECTION OUTPUT ;
    USE SIGNAL ;
    PORT
      LAYER M4 ;
        RECT  23.676 2.784 23.76 2.808 ;
    END
  END dst_d[1]
  PIN dst_d[200]
    DIRECTION OUTPUT ;
    USE SIGNAL ;
    PORT
      LAYER M4 ;
        RECT  23.676 41.088 23.76 41.112 ;
    END
  END dst_d[200]
  PIN dst_d[201]
    DIRECTION OUTPUT ;
    USE SIGNAL ;
    PORT
      LAYER M4 ;
        RECT  23.676 41.28 23.76 41.304 ;
    END
  END dst_d[201]
  PIN dst_d[202]
    DIRECTION OUTPUT ;
    USE SIGNAL ;
    PORT
      LAYER M4 ;
        RECT  23.676 41.472 23.76 41.496 ;
    END
  END dst_d[202]
  PIN dst_d[203]
    DIRECTION OUTPUT ;
    USE SIGNAL ;
    PORT
      LAYER M4 ;
        RECT  23.676 41.664 23.76 41.688 ;
    END
  END dst_d[203]
  PIN dst_d[204]
    DIRECTION OUTPUT ;
    USE SIGNAL ;
    PORT
      LAYER M4 ;
        RECT  23.676 41.856 23.76 41.88 ;
    END
  END dst_d[204]
  PIN dst_d[205]
    DIRECTION OUTPUT ;
    USE SIGNAL ;
    PORT
      LAYER M4 ;
        RECT  23.676 42.048 23.76 42.072 ;
    END
  END dst_d[205]
  PIN dst_d[206]
    DIRECTION OUTPUT ;
    USE SIGNAL ;
    PORT
      LAYER M4 ;
        RECT  23.676 42.24 23.76 42.264 ;
    END
  END dst_d[206]
  PIN dst_d[207]
    DIRECTION OUTPUT ;
    USE SIGNAL ;
    PORT
      LAYER M4 ;
        RECT  23.676 42.432 23.76 42.456 ;
    END
  END dst_d[207]
  PIN dst_d[208]
    DIRECTION OUTPUT ;
    USE SIGNAL ;
    PORT
      LAYER M4 ;
        RECT  23.676 42.624 23.76 42.648 ;
    END
  END dst_d[208]
  PIN dst_d[209]
    DIRECTION OUTPUT ;
    USE SIGNAL ;
    PORT
      LAYER M4 ;
        RECT  23.676 42.816 23.76 42.84 ;
    END
  END dst_d[209]
  PIN dst_d[20]
    DIRECTION OUTPUT ;
    USE SIGNAL ;
    PORT
      LAYER M4 ;
        RECT  23.676 6.432 23.76 6.456 ;
    END
  END dst_d[20]
  PIN dst_d[210]
    DIRECTION OUTPUT ;
    USE SIGNAL ;
    PORT
      LAYER M4 ;
        RECT  23.676 43.008 23.76 43.032 ;
    END
  END dst_d[210]
  PIN dst_d[211]
    DIRECTION OUTPUT ;
    USE SIGNAL ;
    PORT
      LAYER M4 ;
        RECT  23.676 43.2 23.76 43.224 ;
    END
  END dst_d[211]
  PIN dst_d[212]
    DIRECTION OUTPUT ;
    USE SIGNAL ;
    PORT
      LAYER M4 ;
        RECT  23.676 43.392 23.76 43.416 ;
    END
  END dst_d[212]
  PIN dst_d[213]
    DIRECTION OUTPUT ;
    USE SIGNAL ;
    PORT
      LAYER M4 ;
        RECT  23.676 43.584 23.76 43.608 ;
    END
  END dst_d[213]
  PIN dst_d[214]
    DIRECTION OUTPUT ;
    USE SIGNAL ;
    PORT
      LAYER M4 ;
        RECT  23.676 43.776 23.76 43.8 ;
    END
  END dst_d[214]
  PIN dst_d[215]
    DIRECTION OUTPUT ;
    USE SIGNAL ;
    PORT
      LAYER M4 ;
        RECT  23.676 43.968 23.76 43.992 ;
    END
  END dst_d[215]
  PIN dst_d[216]
    DIRECTION OUTPUT ;
    USE SIGNAL ;
    PORT
      LAYER M4 ;
        RECT  23.676 44.16 23.76 44.184 ;
    END
  END dst_d[216]
  PIN dst_d[217]
    DIRECTION OUTPUT ;
    USE SIGNAL ;
    PORT
      LAYER M4 ;
        RECT  23.676 44.352 23.76 44.376 ;
    END
  END dst_d[217]
  PIN dst_d[218]
    DIRECTION OUTPUT ;
    USE SIGNAL ;
    PORT
      LAYER M4 ;
        RECT  23.676 44.544 23.76 44.568 ;
    END
  END dst_d[218]
  PIN dst_d[219]
    DIRECTION OUTPUT ;
    USE SIGNAL ;
    PORT
      LAYER M4 ;
        RECT  23.676 44.736 23.76 44.76 ;
    END
  END dst_d[219]
  PIN dst_d[21]
    DIRECTION OUTPUT ;
    USE SIGNAL ;
    PORT
      LAYER M4 ;
        RECT  23.676 6.624 23.76 6.648 ;
    END
  END dst_d[21]
  PIN dst_d[220]
    DIRECTION OUTPUT ;
    USE SIGNAL ;
    PORT
      LAYER M4 ;
        RECT  23.676 44.928 23.76 44.952 ;
    END
  END dst_d[220]
  PIN dst_d[221]
    DIRECTION OUTPUT ;
    USE SIGNAL ;
    PORT
      LAYER M4 ;
        RECT  23.676 45.12 23.76 45.144 ;
    END
  END dst_d[221]
  PIN dst_d[222]
    DIRECTION OUTPUT ;
    USE SIGNAL ;
    PORT
      LAYER M4 ;
        RECT  23.676 45.312 23.76 45.336 ;
    END
  END dst_d[222]
  PIN dst_d[223]
    DIRECTION OUTPUT ;
    USE SIGNAL ;
    PORT
      LAYER M4 ;
        RECT  23.676 45.504 23.76 45.528 ;
    END
  END dst_d[223]
  PIN dst_d[224]
    DIRECTION OUTPUT ;
    USE SIGNAL ;
    PORT
      LAYER M4 ;
        RECT  23.676 45.696 23.76 45.72 ;
    END
  END dst_d[224]
  PIN dst_d[225]
    DIRECTION OUTPUT ;
    USE SIGNAL ;
    PORT
      LAYER M4 ;
        RECT  23.676 45.888 23.76 45.912 ;
    END
  END dst_d[225]
  PIN dst_d[226]
    DIRECTION OUTPUT ;
    USE SIGNAL ;
    PORT
      LAYER M4 ;
        RECT  23.676 46.08 23.76 46.104 ;
    END
  END dst_d[226]
  PIN dst_d[227]
    DIRECTION OUTPUT ;
    USE SIGNAL ;
    PORT
      LAYER M4 ;
        RECT  23.676 46.272 23.76 46.296 ;
    END
  END dst_d[227]
  PIN dst_d[228]
    DIRECTION OUTPUT ;
    USE SIGNAL ;
    PORT
      LAYER M4 ;
        RECT  23.676 46.464 23.76 46.488 ;
    END
  END dst_d[228]
  PIN dst_d[229]
    DIRECTION OUTPUT ;
    USE SIGNAL ;
    PORT
      LAYER M4 ;
        RECT  23.676 46.656 23.76 46.68 ;
    END
  END dst_d[229]
  PIN dst_d[22]
    DIRECTION OUTPUT ;
    USE SIGNAL ;
    PORT
      LAYER M4 ;
        RECT  23.676 6.816 23.76 6.84 ;
    END
  END dst_d[22]
  PIN dst_d[230]
    DIRECTION OUTPUT ;
    USE SIGNAL ;
    PORT
      LAYER M4 ;
        RECT  23.676 46.848 23.76 46.872 ;
    END
  END dst_d[230]
  PIN dst_d[231]
    DIRECTION OUTPUT ;
    USE SIGNAL ;
    PORT
      LAYER M4 ;
        RECT  23.676 47.04 23.76 47.064 ;
    END
  END dst_d[231]
  PIN dst_d[232]
    DIRECTION OUTPUT ;
    USE SIGNAL ;
    PORT
      LAYER M4 ;
        RECT  23.676 47.232 23.76 47.256 ;
    END
  END dst_d[232]
  PIN dst_d[233]
    DIRECTION OUTPUT ;
    USE SIGNAL ;
    PORT
      LAYER M4 ;
        RECT  23.676 47.424 23.76 47.448 ;
    END
  END dst_d[233]
  PIN dst_d[234]
    DIRECTION OUTPUT ;
    USE SIGNAL ;
    PORT
      LAYER M4 ;
        RECT  23.676 47.616 23.76 47.64 ;
    END
  END dst_d[234]
  PIN dst_d[235]
    DIRECTION OUTPUT ;
    USE SIGNAL ;
    PORT
      LAYER M4 ;
        RECT  23.676 47.808 23.76 47.832 ;
    END
  END dst_d[235]
  PIN dst_d[236]
    DIRECTION OUTPUT ;
    USE SIGNAL ;
    PORT
      LAYER M4 ;
        RECT  23.676 48 23.76 48.024 ;
    END
  END dst_d[236]
  PIN dst_d[237]
    DIRECTION OUTPUT ;
    USE SIGNAL ;
    PORT
      LAYER M4 ;
        RECT  23.676 48.192 23.76 48.216 ;
    END
  END dst_d[237]
  PIN dst_d[238]
    DIRECTION OUTPUT ;
    USE SIGNAL ;
    PORT
      LAYER M4 ;
        RECT  23.676 48.384 23.76 48.408 ;
    END
  END dst_d[238]
  PIN dst_d[239]
    DIRECTION OUTPUT ;
    USE SIGNAL ;
    PORT
      LAYER M4 ;
        RECT  23.676 48.576 23.76 48.6 ;
    END
  END dst_d[239]
  PIN dst_d[23]
    DIRECTION OUTPUT ;
    USE SIGNAL ;
    PORT
      LAYER M4 ;
        RECT  23.676 7.008 23.76 7.032 ;
    END
  END dst_d[23]
  PIN dst_d[240]
    DIRECTION OUTPUT ;
    USE SIGNAL ;
    PORT
      LAYER M4 ;
        RECT  23.676 48.768 23.76 48.792 ;
    END
  END dst_d[240]
  PIN dst_d[241]
    DIRECTION OUTPUT ;
    USE SIGNAL ;
    PORT
      LAYER M4 ;
        RECT  23.676 48.96 23.76 48.984 ;
    END
  END dst_d[241]
  PIN dst_d[242]
    DIRECTION OUTPUT ;
    USE SIGNAL ;
    PORT
      LAYER M4 ;
        RECT  23.676 49.152 23.76 49.176 ;
    END
  END dst_d[242]
  PIN dst_d[243]
    DIRECTION OUTPUT ;
    USE SIGNAL ;
    PORT
      LAYER M4 ;
        RECT  23.676 49.344 23.76 49.368 ;
    END
  END dst_d[243]
  PIN dst_d[244]
    DIRECTION OUTPUT ;
    USE SIGNAL ;
    PORT
      LAYER M4 ;
        RECT  23.676 49.536 23.76 49.56 ;
    END
  END dst_d[244]
  PIN dst_d[245]
    DIRECTION OUTPUT ;
    USE SIGNAL ;
    PORT
      LAYER M4 ;
        RECT  23.676 49.728 23.76 49.752 ;
    END
  END dst_d[245]
  PIN dst_d[246]
    DIRECTION OUTPUT ;
    USE SIGNAL ;
    PORT
      LAYER M4 ;
        RECT  23.676 49.92 23.76 49.944 ;
    END
  END dst_d[246]
  PIN dst_d[247]
    DIRECTION OUTPUT ;
    USE SIGNAL ;
    PORT
      LAYER M4 ;
        RECT  23.676 50.112 23.76 50.136 ;
    END
  END dst_d[247]
  PIN dst_d[248]
    DIRECTION OUTPUT ;
    USE SIGNAL ;
    PORT
      LAYER M4 ;
        RECT  23.676 50.304 23.76 50.328 ;
    END
  END dst_d[248]
  PIN dst_d[249]
    DIRECTION OUTPUT ;
    USE SIGNAL ;
    PORT
      LAYER M4 ;
        RECT  23.676 50.496 23.76 50.52 ;
    END
  END dst_d[249]
  PIN dst_d[24]
    DIRECTION OUTPUT ;
    USE SIGNAL ;
    PORT
      LAYER M4 ;
        RECT  23.676 7.2 23.76 7.224 ;
    END
  END dst_d[24]
  PIN dst_d[250]
    DIRECTION OUTPUT ;
    USE SIGNAL ;
    PORT
      LAYER M4 ;
        RECT  23.676 50.688 23.76 50.712 ;
    END
  END dst_d[250]
  PIN dst_d[251]
    DIRECTION OUTPUT ;
    USE SIGNAL ;
    PORT
      LAYER M4 ;
        RECT  23.676 50.88 23.76 50.904 ;
    END
  END dst_d[251]
  PIN dst_d[252]
    DIRECTION OUTPUT ;
    USE SIGNAL ;
    PORT
      LAYER M4 ;
        RECT  23.676 51.072 23.76 51.096 ;
    END
  END dst_d[252]
  PIN dst_d[253]
    DIRECTION OUTPUT ;
    USE SIGNAL ;
    PORT
      LAYER M4 ;
        RECT  23.676 51.264 23.76 51.288 ;
    END
  END dst_d[253]
  PIN dst_d[254]
    DIRECTION OUTPUT ;
    USE SIGNAL ;
    PORT
      LAYER M4 ;
        RECT  23.676 51.456 23.76 51.48 ;
    END
  END dst_d[254]
  PIN dst_d[255]
    DIRECTION OUTPUT ;
    USE SIGNAL ;
    PORT
      LAYER M4 ;
        RECT  23.676 51.648 23.76 51.672 ;
    END
  END dst_d[255]
  PIN dst_d[256]
    DIRECTION OUTPUT ;
    USE SIGNAL ;
    PORT
      LAYER M4 ;
        RECT  23.676 51.84 23.76 51.864 ;
    END
  END dst_d[256]
  PIN dst_d[257]
    DIRECTION OUTPUT ;
    USE SIGNAL ;
    PORT
      LAYER M4 ;
        RECT  23.676 52.032 23.76 52.056 ;
    END
  END dst_d[257]
  PIN dst_d[258]
    DIRECTION OUTPUT ;
    USE SIGNAL ;
    PORT
      LAYER M4 ;
        RECT  23.676 52.224 23.76 52.248 ;
    END
  END dst_d[258]
  PIN dst_d[259]
    DIRECTION OUTPUT ;
    USE SIGNAL ;
    PORT
      LAYER M4 ;
        RECT  23.676 52.416 23.76 52.44 ;
    END
  END dst_d[259]
  PIN dst_d[25]
    DIRECTION OUTPUT ;
    USE SIGNAL ;
    PORT
      LAYER M4 ;
        RECT  23.676 7.392 23.76 7.416 ;
    END
  END dst_d[25]
  PIN dst_d[260]
    DIRECTION OUTPUT ;
    USE SIGNAL ;
    PORT
      LAYER M4 ;
        RECT  23.676 52.608 23.76 52.632 ;
    END
  END dst_d[260]
  PIN dst_d[261]
    DIRECTION OUTPUT ;
    USE SIGNAL ;
    PORT
      LAYER M4 ;
        RECT  23.676 52.8 23.76 52.824 ;
    END
  END dst_d[261]
  PIN dst_d[262]
    DIRECTION OUTPUT ;
    USE SIGNAL ;
    PORT
      LAYER M4 ;
        RECT  23.676 52.992 23.76 53.016 ;
    END
  END dst_d[262]
  PIN dst_d[263]
    DIRECTION OUTPUT ;
    USE SIGNAL ;
    PORT
      LAYER M4 ;
        RECT  23.676 53.184 23.76 53.208 ;
    END
  END dst_d[263]
  PIN dst_d[264]
    DIRECTION OUTPUT ;
    USE SIGNAL ;
    PORT
      LAYER M4 ;
        RECT  23.676 53.376 23.76 53.4 ;
    END
  END dst_d[264]
  PIN dst_d[265]
    DIRECTION OUTPUT ;
    USE SIGNAL ;
    PORT
      LAYER M4 ;
        RECT  23.676 53.568 23.76 53.592 ;
    END
  END dst_d[265]
  PIN dst_d[266]
    DIRECTION OUTPUT ;
    USE SIGNAL ;
    PORT
      LAYER M4 ;
        RECT  23.676 53.76 23.76 53.784 ;
    END
  END dst_d[266]
  PIN dst_d[267]
    DIRECTION OUTPUT ;
    USE SIGNAL ;
    PORT
      LAYER M4 ;
        RECT  23.676 53.952 23.76 53.976 ;
    END
  END dst_d[267]
  PIN dst_d[268]
    DIRECTION OUTPUT ;
    USE SIGNAL ;
    PORT
      LAYER M4 ;
        RECT  23.676 54.144 23.76 54.168 ;
    END
  END dst_d[268]
  PIN dst_d[269]
    DIRECTION OUTPUT ;
    USE SIGNAL ;
    PORT
      LAYER M4 ;
        RECT  23.676 54.336 23.76 54.36 ;
    END
  END dst_d[269]
  PIN dst_d[26]
    DIRECTION OUTPUT ;
    USE SIGNAL ;
    PORT
      LAYER M4 ;
        RECT  23.676 7.584 23.76 7.608 ;
    END
  END dst_d[26]
  PIN dst_d[270]
    DIRECTION OUTPUT ;
    USE SIGNAL ;
    PORT
      LAYER M4 ;
        RECT  23.676 54.528 23.76 54.552 ;
    END
  END dst_d[270]
  PIN dst_d[271]
    DIRECTION OUTPUT ;
    USE SIGNAL ;
    PORT
      LAYER M4 ;
        RECT  23.676 54.72 23.76 54.744 ;
    END
  END dst_d[271]
  PIN dst_d[272]
    DIRECTION OUTPUT ;
    USE SIGNAL ;
    PORT
      LAYER M4 ;
        RECT  23.676 54.912 23.76 54.936 ;
    END
  END dst_d[272]
  PIN dst_d[273]
    DIRECTION OUTPUT ;
    USE SIGNAL ;
    PORT
      LAYER M4 ;
        RECT  23.676 55.104 23.76 55.128 ;
    END
  END dst_d[273]
  PIN dst_d[274]
    DIRECTION OUTPUT ;
    USE SIGNAL ;
    PORT
      LAYER M4 ;
        RECT  23.676 55.296 23.76 55.32 ;
    END
  END dst_d[274]
  PIN dst_d[275]
    DIRECTION OUTPUT ;
    USE SIGNAL ;
    PORT
      LAYER M4 ;
        RECT  23.676 55.488 23.76 55.512 ;
    END
  END dst_d[275]
  PIN dst_d[276]
    DIRECTION OUTPUT ;
    USE SIGNAL ;
    PORT
      LAYER M4 ;
        RECT  23.676 55.68 23.76 55.704 ;
    END
  END dst_d[276]
  PIN dst_d[277]
    DIRECTION OUTPUT ;
    USE SIGNAL ;
    PORT
      LAYER M4 ;
        RECT  23.676 55.872 23.76 55.896 ;
    END
  END dst_d[277]
  PIN dst_d[278]
    DIRECTION OUTPUT ;
    USE SIGNAL ;
    PORT
      LAYER M4 ;
        RECT  23.676 56.064 23.76 56.088 ;
    END
  END dst_d[278]
  PIN dst_d[279]
    DIRECTION OUTPUT ;
    USE SIGNAL ;
    PORT
      LAYER M4 ;
        RECT  23.676 56.256 23.76 56.28 ;
    END
  END dst_d[279]
  PIN dst_d[27]
    DIRECTION OUTPUT ;
    USE SIGNAL ;
    PORT
      LAYER M4 ;
        RECT  23.676 7.776 23.76 7.8 ;
    END
  END dst_d[27]
  PIN dst_d[280]
    DIRECTION OUTPUT ;
    USE SIGNAL ;
    PORT
      LAYER M4 ;
        RECT  23.676 56.448 23.76 56.472 ;
    END
  END dst_d[280]
  PIN dst_d[281]
    DIRECTION OUTPUT ;
    USE SIGNAL ;
    PORT
      LAYER M4 ;
        RECT  23.676 56.64 23.76 56.664 ;
    END
  END dst_d[281]
  PIN dst_d[282]
    DIRECTION OUTPUT ;
    USE SIGNAL ;
    PORT
      LAYER M4 ;
        RECT  23.676 56.832 23.76 56.856 ;
    END
  END dst_d[282]
  PIN dst_d[283]
    DIRECTION OUTPUT ;
    USE SIGNAL ;
    PORT
      LAYER M4 ;
        RECT  23.676 57.024 23.76 57.048 ;
    END
  END dst_d[283]
  PIN dst_d[284]
    DIRECTION OUTPUT ;
    USE SIGNAL ;
    PORT
      LAYER M4 ;
        RECT  23.676 57.216 23.76 57.24 ;
    END
  END dst_d[284]
  PIN dst_d[285]
    DIRECTION OUTPUT ;
    USE SIGNAL ;
    PORT
      LAYER M4 ;
        RECT  23.676 57.408 23.76 57.432 ;
    END
  END dst_d[285]
  PIN dst_d[286]
    DIRECTION OUTPUT ;
    USE SIGNAL ;
    PORT
      LAYER M4 ;
        RECT  23.676 57.6 23.76 57.624 ;
    END
  END dst_d[286]
  PIN dst_d[287]
    DIRECTION OUTPUT ;
    USE SIGNAL ;
    PORT
      LAYER M4 ;
        RECT  23.676 57.792 23.76 57.816 ;
    END
  END dst_d[287]
  PIN dst_d[288]
    DIRECTION OUTPUT ;
    USE SIGNAL ;
    PORT
      LAYER M4 ;
        RECT  23.676 57.984 23.76 58.008 ;
    END
  END dst_d[288]
  PIN dst_d[289]
    DIRECTION OUTPUT ;
    USE SIGNAL ;
    PORT
      LAYER M4 ;
        RECT  23.676 58.176 23.76 58.2 ;
    END
  END dst_d[289]
  PIN dst_d[28]
    DIRECTION OUTPUT ;
    USE SIGNAL ;
    PORT
      LAYER M4 ;
        RECT  23.676 7.968 23.76 7.992 ;
    END
  END dst_d[28]
  PIN dst_d[290]
    DIRECTION OUTPUT ;
    USE SIGNAL ;
    PORT
      LAYER M4 ;
        RECT  23.676 58.368 23.76 58.392 ;
    END
  END dst_d[290]
  PIN dst_d[291]
    DIRECTION OUTPUT ;
    USE SIGNAL ;
    PORT
      LAYER M4 ;
        RECT  23.676 58.608 23.76 58.632 ;
    END
  END dst_d[291]
  PIN dst_d[292]
    DIRECTION OUTPUT ;
    USE SIGNAL ;
    PORT
      LAYER M4 ;
        RECT  23.676 58.8 23.76 58.824 ;
    END
  END dst_d[292]
  PIN dst_d[293]
    DIRECTION OUTPUT ;
    USE SIGNAL ;
    PORT
      LAYER M4 ;
        RECT  23.676 58.992 23.76 59.016 ;
    END
  END dst_d[293]
  PIN dst_d[294]
    DIRECTION OUTPUT ;
    USE SIGNAL ;
    PORT
      LAYER M4 ;
        RECT  23.676 59.184 23.76 59.208 ;
    END
  END dst_d[294]
  PIN dst_d[295]
    DIRECTION OUTPUT ;
    USE SIGNAL ;
    PORT
      LAYER M4 ;
        RECT  23.676 59.376 23.76 59.4 ;
    END
  END dst_d[295]
  PIN dst_d[296]
    DIRECTION OUTPUT ;
    USE SIGNAL ;
    PORT
      LAYER M4 ;
        RECT  23.676 59.568 23.76 59.592 ;
    END
  END dst_d[296]
  PIN dst_d[297]
    DIRECTION OUTPUT ;
    USE SIGNAL ;
    PORT
      LAYER M4 ;
        RECT  23.676 59.76 23.76 59.784 ;
    END
  END dst_d[297]
  PIN dst_d[298]
    DIRECTION OUTPUT ;
    USE SIGNAL ;
    PORT
      LAYER M4 ;
        RECT  23.676 59.952 23.76 59.976 ;
    END
  END dst_d[298]
  PIN dst_d[299]
    DIRECTION OUTPUT ;
    USE SIGNAL ;
    PORT
      LAYER M4 ;
        RECT  23.676 60.144 23.76 60.168 ;
    END
  END dst_d[299]
  PIN dst_d[29]
    DIRECTION OUTPUT ;
    USE SIGNAL ;
    PORT
      LAYER M4 ;
        RECT  23.676 8.16 23.76 8.184 ;
    END
  END dst_d[29]
  PIN dst_d[2]
    DIRECTION OUTPUT ;
    USE SIGNAL ;
    PORT
      LAYER M4 ;
        RECT  23.676 2.976 23.76 3 ;
    END
  END dst_d[2]
  PIN dst_d[300]
    DIRECTION OUTPUT ;
    USE SIGNAL ;
    PORT
      LAYER M4 ;
        RECT  23.676 60.336 23.76 60.36 ;
    END
  END dst_d[300]
  PIN dst_d[301]
    DIRECTION OUTPUT ;
    USE SIGNAL ;
    PORT
      LAYER M4 ;
        RECT  23.676 60.528 23.76 60.552 ;
    END
  END dst_d[301]
  PIN dst_d[302]
    DIRECTION OUTPUT ;
    USE SIGNAL ;
    PORT
      LAYER M4 ;
        RECT  23.676 60.72 23.76 60.744 ;
    END
  END dst_d[302]
  PIN dst_d[303]
    DIRECTION OUTPUT ;
    USE SIGNAL ;
    PORT
      LAYER M4 ;
        RECT  23.676 60.912 23.76 60.936 ;
    END
  END dst_d[303]
  PIN dst_d[304]
    DIRECTION OUTPUT ;
    USE SIGNAL ;
    PORT
      LAYER M4 ;
        RECT  23.676 61.104 23.76 61.128 ;
    END
  END dst_d[304]
  PIN dst_d[305]
    DIRECTION OUTPUT ;
    USE SIGNAL ;
    PORT
      LAYER M4 ;
        RECT  23.676 61.296 23.76 61.32 ;
    END
  END dst_d[305]
  PIN dst_d[306]
    DIRECTION OUTPUT ;
    USE SIGNAL ;
    PORT
      LAYER M4 ;
        RECT  23.676 61.488 23.76 61.512 ;
    END
  END dst_d[306]
  PIN dst_d[307]
    DIRECTION OUTPUT ;
    USE SIGNAL ;
    PORT
      LAYER M4 ;
        RECT  23.676 61.68 23.76 61.704 ;
    END
  END dst_d[307]
  PIN dst_d[308]
    DIRECTION OUTPUT ;
    USE SIGNAL ;
    PORT
      LAYER M4 ;
        RECT  23.676 61.872 23.76 61.896 ;
    END
  END dst_d[308]
  PIN dst_d[309]
    DIRECTION OUTPUT ;
    USE SIGNAL ;
    PORT
      LAYER M4 ;
        RECT  23.676 62.064 23.76 62.088 ;
    END
  END dst_d[309]
  PIN dst_d[30]
    DIRECTION OUTPUT ;
    USE SIGNAL ;
    PORT
      LAYER M4 ;
        RECT  23.676 8.352 23.76 8.376 ;
    END
  END dst_d[30]
  PIN dst_d[310]
    DIRECTION OUTPUT ;
    USE SIGNAL ;
    PORT
      LAYER M4 ;
        RECT  23.676 62.256 23.76 62.28 ;
    END
  END dst_d[310]
  PIN dst_d[311]
    DIRECTION OUTPUT ;
    USE SIGNAL ;
    PORT
      LAYER M4 ;
        RECT  23.676 62.448 23.76 62.472 ;
    END
  END dst_d[311]
  PIN dst_d[312]
    DIRECTION OUTPUT ;
    USE SIGNAL ;
    PORT
      LAYER M4 ;
        RECT  23.676 62.64 23.76 62.664 ;
    END
  END dst_d[312]
  PIN dst_d[313]
    DIRECTION OUTPUT ;
    USE SIGNAL ;
    PORT
      LAYER M4 ;
        RECT  23.676 62.832 23.76 62.856 ;
    END
  END dst_d[313]
  PIN dst_d[314]
    DIRECTION OUTPUT ;
    USE SIGNAL ;
    PORT
      LAYER M4 ;
        RECT  23.676 63.024 23.76 63.048 ;
    END
  END dst_d[314]
  PIN dst_d[315]
    DIRECTION OUTPUT ;
    USE SIGNAL ;
    PORT
      LAYER M4 ;
        RECT  23.676 63.216 23.76 63.24 ;
    END
  END dst_d[315]
  PIN dst_d[316]
    DIRECTION OUTPUT ;
    USE SIGNAL ;
    PORT
      LAYER M4 ;
        RECT  23.676 63.408 23.76 63.432 ;
    END
  END dst_d[316]
  PIN dst_d[317]
    DIRECTION OUTPUT ;
    USE SIGNAL ;
    PORT
      LAYER M4 ;
        RECT  23.676 63.6 23.76 63.624 ;
    END
  END dst_d[317]
  PIN dst_d[318]
    DIRECTION OUTPUT ;
    USE SIGNAL ;
    PORT
      LAYER M4 ;
        RECT  23.676 63.792 23.76 63.816 ;
    END
  END dst_d[318]
  PIN dst_d[319]
    DIRECTION OUTPUT ;
    USE SIGNAL ;
    PORT
      LAYER M4 ;
        RECT  23.676 63.984 23.76 64.008 ;
    END
  END dst_d[319]
  PIN dst_d[31]
    DIRECTION OUTPUT ;
    USE SIGNAL ;
    PORT
      LAYER M4 ;
        RECT  23.676 8.544 23.76 8.568 ;
    END
  END dst_d[31]
  PIN dst_d[320]
    DIRECTION OUTPUT ;
    USE SIGNAL ;
    PORT
      LAYER M4 ;
        RECT  23.676 64.176 23.76 64.2 ;
    END
  END dst_d[320]
  PIN dst_d[321]
    DIRECTION OUTPUT ;
    USE SIGNAL ;
    PORT
      LAYER M4 ;
        RECT  23.676 64.368 23.76 64.392 ;
    END
  END dst_d[321]
  PIN dst_d[322]
    DIRECTION OUTPUT ;
    USE SIGNAL ;
    PORT
      LAYER M4 ;
        RECT  23.676 64.56 23.76 64.584 ;
    END
  END dst_d[322]
  PIN dst_d[323]
    DIRECTION OUTPUT ;
    USE SIGNAL ;
    PORT
      LAYER M4 ;
        RECT  23.676 64.752 23.76 64.776 ;
    END
  END dst_d[323]
  PIN dst_d[324]
    DIRECTION OUTPUT ;
    USE SIGNAL ;
    PORT
      LAYER M4 ;
        RECT  23.676 64.944 23.76 64.968 ;
    END
  END dst_d[324]
  PIN dst_d[325]
    DIRECTION OUTPUT ;
    USE SIGNAL ;
    PORT
      LAYER M4 ;
        RECT  23.676 65.136 23.76 65.16 ;
    END
  END dst_d[325]
  PIN dst_d[326]
    DIRECTION OUTPUT ;
    USE SIGNAL ;
    PORT
      LAYER M4 ;
        RECT  23.676 65.328 23.76 65.352 ;
    END
  END dst_d[326]
  PIN dst_d[327]
    DIRECTION OUTPUT ;
    USE SIGNAL ;
    PORT
      LAYER M4 ;
        RECT  23.676 65.52 23.76 65.544 ;
    END
  END dst_d[327]
  PIN dst_d[328]
    DIRECTION OUTPUT ;
    USE SIGNAL ;
    PORT
      LAYER M4 ;
        RECT  23.676 65.712 23.76 65.736 ;
    END
  END dst_d[328]
  PIN dst_d[329]
    DIRECTION OUTPUT ;
    USE SIGNAL ;
    PORT
      LAYER M4 ;
        RECT  23.676 65.904 23.76 65.928 ;
    END
  END dst_d[329]
  PIN dst_d[32]
    DIRECTION OUTPUT ;
    USE SIGNAL ;
    PORT
      LAYER M4 ;
        RECT  23.676 8.736 23.76 8.76 ;
    END
  END dst_d[32]
  PIN dst_d[330]
    DIRECTION OUTPUT ;
    USE SIGNAL ;
    PORT
      LAYER M4 ;
        RECT  23.676 66.096 23.76 66.12 ;
    END
  END dst_d[330]
  PIN dst_d[331]
    DIRECTION OUTPUT ;
    USE SIGNAL ;
    PORT
      LAYER M4 ;
        RECT  23.676 66.288 23.76 66.312 ;
    END
  END dst_d[331]
  PIN dst_d[332]
    DIRECTION OUTPUT ;
    USE SIGNAL ;
    PORT
      LAYER M4 ;
        RECT  23.676 66.48 23.76 66.504 ;
    END
  END dst_d[332]
  PIN dst_d[333]
    DIRECTION OUTPUT ;
    USE SIGNAL ;
    PORT
      LAYER M4 ;
        RECT  23.676 66.672 23.76 66.696 ;
    END
  END dst_d[333]
  PIN dst_d[334]
    DIRECTION OUTPUT ;
    USE SIGNAL ;
    PORT
      LAYER M4 ;
        RECT  23.676 66.864 23.76 66.888 ;
    END
  END dst_d[334]
  PIN dst_d[335]
    DIRECTION OUTPUT ;
    USE SIGNAL ;
    PORT
      LAYER M4 ;
        RECT  23.676 67.056 23.76 67.08 ;
    END
  END dst_d[335]
  PIN dst_d[336]
    DIRECTION OUTPUT ;
    USE SIGNAL ;
    PORT
      LAYER M4 ;
        RECT  23.676 67.248 23.76 67.272 ;
    END
  END dst_d[336]
  PIN dst_d[337]
    DIRECTION OUTPUT ;
    USE SIGNAL ;
    PORT
      LAYER M4 ;
        RECT  23.676 67.44 23.76 67.464 ;
    END
  END dst_d[337]
  PIN dst_d[338]
    DIRECTION OUTPUT ;
    USE SIGNAL ;
    PORT
      LAYER M4 ;
        RECT  23.676 67.632 23.76 67.656 ;
    END
  END dst_d[338]
  PIN dst_d[339]
    DIRECTION OUTPUT ;
    USE SIGNAL ;
    PORT
      LAYER M4 ;
        RECT  23.676 67.824 23.76 67.848 ;
    END
  END dst_d[339]
  PIN dst_d[33]
    DIRECTION OUTPUT ;
    USE SIGNAL ;
    PORT
      LAYER M4 ;
        RECT  23.676 8.928 23.76 8.952 ;
    END
  END dst_d[33]
  PIN dst_d[340]
    DIRECTION OUTPUT ;
    USE SIGNAL ;
    PORT
      LAYER M4 ;
        RECT  23.676 68.016 23.76 68.04 ;
    END
  END dst_d[340]
  PIN dst_d[341]
    DIRECTION OUTPUT ;
    USE SIGNAL ;
    PORT
      LAYER M4 ;
        RECT  23.676 68.208 23.76 68.232 ;
    END
  END dst_d[341]
  PIN dst_d[342]
    DIRECTION OUTPUT ;
    USE SIGNAL ;
    PORT
      LAYER M4 ;
        RECT  23.676 68.4 23.76 68.424 ;
    END
  END dst_d[342]
  PIN dst_d[343]
    DIRECTION OUTPUT ;
    USE SIGNAL ;
    PORT
      LAYER M4 ;
        RECT  23.676 68.592 23.76 68.616 ;
    END
  END dst_d[343]
  PIN dst_d[344]
    DIRECTION OUTPUT ;
    USE SIGNAL ;
    PORT
      LAYER M4 ;
        RECT  23.676 68.784 23.76 68.808 ;
    END
  END dst_d[344]
  PIN dst_d[345]
    DIRECTION OUTPUT ;
    USE SIGNAL ;
    PORT
      LAYER M4 ;
        RECT  23.676 68.976 23.76 69 ;
    END
  END dst_d[345]
  PIN dst_d[346]
    DIRECTION OUTPUT ;
    USE SIGNAL ;
    PORT
      LAYER M4 ;
        RECT  23.676 69.168 23.76 69.192 ;
    END
  END dst_d[346]
  PIN dst_d[347]
    DIRECTION OUTPUT ;
    USE SIGNAL ;
    PORT
      LAYER M4 ;
        RECT  23.676 69.36 23.76 69.384 ;
    END
  END dst_d[347]
  PIN dst_d[348]
    DIRECTION OUTPUT ;
    USE SIGNAL ;
    PORT
      LAYER M4 ;
        RECT  23.676 69.552 23.76 69.576 ;
    END
  END dst_d[348]
  PIN dst_d[349]
    DIRECTION OUTPUT ;
    USE SIGNAL ;
    PORT
      LAYER M4 ;
        RECT  23.676 69.744 23.76 69.768 ;
    END
  END dst_d[349]
  PIN dst_d[34]
    DIRECTION OUTPUT ;
    USE SIGNAL ;
    PORT
      LAYER M4 ;
        RECT  23.676 9.12 23.76 9.144 ;
    END
  END dst_d[34]
  PIN dst_d[350]
    DIRECTION OUTPUT ;
    USE SIGNAL ;
    PORT
      LAYER M4 ;
        RECT  23.676 69.936 23.76 69.96 ;
    END
  END dst_d[350]
  PIN dst_d[351]
    DIRECTION OUTPUT ;
    USE SIGNAL ;
    PORT
      LAYER M4 ;
        RECT  23.676 70.128 23.76 70.152 ;
    END
  END dst_d[351]
  PIN dst_d[352]
    DIRECTION OUTPUT ;
    USE SIGNAL ;
    PORT
      LAYER M4 ;
        RECT  23.676 70.32 23.76 70.344 ;
    END
  END dst_d[352]
  PIN dst_d[353]
    DIRECTION OUTPUT ;
    USE SIGNAL ;
    PORT
      LAYER M4 ;
        RECT  23.676 70.512 23.76 70.536 ;
    END
  END dst_d[353]
  PIN dst_d[354]
    DIRECTION OUTPUT ;
    USE SIGNAL ;
    PORT
      LAYER M4 ;
        RECT  23.676 70.704 23.76 70.728 ;
    END
  END dst_d[354]
  PIN dst_d[355]
    DIRECTION OUTPUT ;
    USE SIGNAL ;
    PORT
      LAYER M4 ;
        RECT  23.676 70.896 23.76 70.92 ;
    END
  END dst_d[355]
  PIN dst_d[356]
    DIRECTION OUTPUT ;
    USE SIGNAL ;
    PORT
      LAYER M4 ;
        RECT  23.676 71.088 23.76 71.112 ;
    END
  END dst_d[356]
  PIN dst_d[357]
    DIRECTION OUTPUT ;
    USE SIGNAL ;
    PORT
      LAYER M4 ;
        RECT  23.676 71.28 23.76 71.304 ;
    END
  END dst_d[357]
  PIN dst_d[358]
    DIRECTION OUTPUT ;
    USE SIGNAL ;
    PORT
      LAYER M4 ;
        RECT  23.676 71.472 23.76 71.496 ;
    END
  END dst_d[358]
  PIN dst_d[359]
    DIRECTION OUTPUT ;
    USE SIGNAL ;
    PORT
      LAYER M4 ;
        RECT  23.676 71.664 23.76 71.688 ;
    END
  END dst_d[359]
  PIN dst_d[35]
    DIRECTION OUTPUT ;
    USE SIGNAL ;
    PORT
      LAYER M4 ;
        RECT  23.676 9.312 23.76 9.336 ;
    END
  END dst_d[35]
  PIN dst_d[360]
    DIRECTION OUTPUT ;
    USE SIGNAL ;
    PORT
      LAYER M4 ;
        RECT  23.676 71.856 23.76 71.88 ;
    END
  END dst_d[360]
  PIN dst_d[361]
    DIRECTION OUTPUT ;
    USE SIGNAL ;
    PORT
      LAYER M4 ;
        RECT  23.676 72.048 23.76 72.072 ;
    END
  END dst_d[361]
  PIN dst_d[362]
    DIRECTION OUTPUT ;
    USE SIGNAL ;
    PORT
      LAYER M4 ;
        RECT  23.676 72.24 23.76 72.264 ;
    END
  END dst_d[362]
  PIN dst_d[363]
    DIRECTION OUTPUT ;
    USE SIGNAL ;
    PORT
      LAYER M4 ;
        RECT  23.676 72.432 23.76 72.456 ;
    END
  END dst_d[363]
  PIN dst_d[364]
    DIRECTION OUTPUT ;
    USE SIGNAL ;
    PORT
      LAYER M4 ;
        RECT  23.676 72.624 23.76 72.648 ;
    END
  END dst_d[364]
  PIN dst_d[365]
    DIRECTION OUTPUT ;
    USE SIGNAL ;
    PORT
      LAYER M4 ;
        RECT  23.676 72.816 23.76 72.84 ;
    END
  END dst_d[365]
  PIN dst_d[366]
    DIRECTION OUTPUT ;
    USE SIGNAL ;
    PORT
      LAYER M4 ;
        RECT  23.676 73.008 23.76 73.032 ;
    END
  END dst_d[366]
  PIN dst_d[367]
    DIRECTION OUTPUT ;
    USE SIGNAL ;
    PORT
      LAYER M4 ;
        RECT  23.676 73.2 23.76 73.224 ;
    END
  END dst_d[367]
  PIN dst_d[368]
    DIRECTION OUTPUT ;
    USE SIGNAL ;
    PORT
      LAYER M4 ;
        RECT  23.676 73.392 23.76 73.416 ;
    END
  END dst_d[368]
  PIN dst_d[369]
    DIRECTION OUTPUT ;
    USE SIGNAL ;
    PORT
      LAYER M4 ;
        RECT  23.676 73.584 23.76 73.608 ;
    END
  END dst_d[369]
  PIN dst_d[36]
    DIRECTION OUTPUT ;
    USE SIGNAL ;
    PORT
      LAYER M4 ;
        RECT  23.676 9.504 23.76 9.528 ;
    END
  END dst_d[36]
  PIN dst_d[370]
    DIRECTION OUTPUT ;
    USE SIGNAL ;
    PORT
      LAYER M4 ;
        RECT  23.676 73.776 23.76 73.8 ;
    END
  END dst_d[370]
  PIN dst_d[371]
    DIRECTION OUTPUT ;
    USE SIGNAL ;
    PORT
      LAYER M4 ;
        RECT  23.676 73.968 23.76 73.992 ;
    END
  END dst_d[371]
  PIN dst_d[372]
    DIRECTION OUTPUT ;
    USE SIGNAL ;
    PORT
      LAYER M4 ;
        RECT  23.676 74.16 23.76 74.184 ;
    END
  END dst_d[372]
  PIN dst_d[373]
    DIRECTION OUTPUT ;
    USE SIGNAL ;
    PORT
      LAYER M4 ;
        RECT  23.676 74.352 23.76 74.376 ;
    END
  END dst_d[373]
  PIN dst_d[374]
    DIRECTION OUTPUT ;
    USE SIGNAL ;
    PORT
      LAYER M4 ;
        RECT  23.676 74.544 23.76 74.568 ;
    END
  END dst_d[374]
  PIN dst_d[375]
    DIRECTION OUTPUT ;
    USE SIGNAL ;
    PORT
      LAYER M4 ;
        RECT  23.676 74.736 23.76 74.76 ;
    END
  END dst_d[375]
  PIN dst_d[376]
    DIRECTION OUTPUT ;
    USE SIGNAL ;
    PORT
      LAYER M4 ;
        RECT  23.676 74.928 23.76 74.952 ;
    END
  END dst_d[376]
  PIN dst_d[377]
    DIRECTION OUTPUT ;
    USE SIGNAL ;
    PORT
      LAYER M4 ;
        RECT  23.676 75.12 23.76 75.144 ;
    END
  END dst_d[377]
  PIN dst_d[378]
    DIRECTION OUTPUT ;
    USE SIGNAL ;
    PORT
      LAYER M4 ;
        RECT  23.676 75.312 23.76 75.336 ;
    END
  END dst_d[378]
  PIN dst_d[379]
    DIRECTION OUTPUT ;
    USE SIGNAL ;
    PORT
      LAYER M4 ;
        RECT  23.676 75.504 23.76 75.528 ;
    END
  END dst_d[379]
  PIN dst_d[37]
    DIRECTION OUTPUT ;
    USE SIGNAL ;
    PORT
      LAYER M4 ;
        RECT  23.676 9.696 23.76 9.72 ;
    END
  END dst_d[37]
  PIN dst_d[380]
    DIRECTION OUTPUT ;
    USE SIGNAL ;
    PORT
      LAYER M4 ;
        RECT  23.676 75.696 23.76 75.72 ;
    END
  END dst_d[380]
  PIN dst_d[381]
    DIRECTION OUTPUT ;
    USE SIGNAL ;
    PORT
      LAYER M4 ;
        RECT  23.676 75.888 23.76 75.912 ;
    END
  END dst_d[381]
  PIN dst_d[382]
    DIRECTION OUTPUT ;
    USE SIGNAL ;
    PORT
      LAYER M4 ;
        RECT  23.676 76.08 23.76 76.104 ;
    END
  END dst_d[382]
  PIN dst_d[383]
    DIRECTION OUTPUT ;
    USE SIGNAL ;
    PORT
      LAYER M4 ;
        RECT  23.676 76.272 23.76 76.296 ;
    END
  END dst_d[383]
  PIN dst_d[384]
    DIRECTION OUTPUT ;
    USE SIGNAL ;
    PORT
      LAYER M4 ;
        RECT  23.676 76.464 23.76 76.488 ;
    END
  END dst_d[384]
  PIN dst_d[385]
    DIRECTION OUTPUT ;
    USE SIGNAL ;
    PORT
      LAYER M4 ;
        RECT  23.676 76.656 23.76 76.68 ;
    END
  END dst_d[385]
  PIN dst_d[386]
    DIRECTION OUTPUT ;
    USE SIGNAL ;
    PORT
      LAYER M4 ;
        RECT  23.676 76.848 23.76 76.872 ;
    END
  END dst_d[386]
  PIN dst_d[387]
    DIRECTION OUTPUT ;
    USE SIGNAL ;
    PORT
      LAYER M4 ;
        RECT  23.676 77.04 23.76 77.064 ;
    END
  END dst_d[387]
  PIN dst_d[388]
    DIRECTION OUTPUT ;
    USE SIGNAL ;
    PORT
      LAYER M4 ;
        RECT  23.676 77.232 23.76 77.256 ;
    END
  END dst_d[388]
  PIN dst_d[389]
    DIRECTION OUTPUT ;
    USE SIGNAL ;
    PORT
      LAYER M4 ;
        RECT  23.676 77.424 23.76 77.448 ;
    END
  END dst_d[389]
  PIN dst_d[38]
    DIRECTION OUTPUT ;
    USE SIGNAL ;
    PORT
      LAYER M4 ;
        RECT  23.676 9.888 23.76 9.912 ;
    END
  END dst_d[38]
  PIN dst_d[390]
    DIRECTION OUTPUT ;
    USE SIGNAL ;
    PORT
      LAYER M4 ;
        RECT  23.676 77.616 23.76 77.64 ;
    END
  END dst_d[390]
  PIN dst_d[391]
    DIRECTION OUTPUT ;
    USE SIGNAL ;
    PORT
      LAYER M4 ;
        RECT  23.676 77.808 23.76 77.832 ;
    END
  END dst_d[391]
  PIN dst_d[392]
    DIRECTION OUTPUT ;
    USE SIGNAL ;
    PORT
      LAYER M4 ;
        RECT  23.676 78 23.76 78.024 ;
    END
  END dst_d[392]
  PIN dst_d[393]
    DIRECTION OUTPUT ;
    USE SIGNAL ;
    PORT
      LAYER M4 ;
        RECT  23.676 78.192 23.76 78.216 ;
    END
  END dst_d[393]
  PIN dst_d[394]
    DIRECTION OUTPUT ;
    USE SIGNAL ;
    PORT
      LAYER M4 ;
        RECT  23.676 78.384 23.76 78.408 ;
    END
  END dst_d[394]
  PIN dst_d[395]
    DIRECTION OUTPUT ;
    USE SIGNAL ;
    PORT
      LAYER M4 ;
        RECT  23.676 78.576 23.76 78.6 ;
    END
  END dst_d[395]
  PIN dst_d[396]
    DIRECTION OUTPUT ;
    USE SIGNAL ;
    PORT
      LAYER M4 ;
        RECT  23.676 78.768 23.76 78.792 ;
    END
  END dst_d[396]
  PIN dst_d[397]
    DIRECTION OUTPUT ;
    USE SIGNAL ;
    PORT
      LAYER M4 ;
        RECT  23.676 78.96 23.76 78.984 ;
    END
  END dst_d[397]
  PIN dst_d[398]
    DIRECTION OUTPUT ;
    USE SIGNAL ;
    PORT
      LAYER M4 ;
        RECT  23.676 79.152 23.76 79.176 ;
    END
  END dst_d[398]
  PIN dst_d[399]
    DIRECTION OUTPUT ;
    USE SIGNAL ;
    PORT
      LAYER M4 ;
        RECT  23.676 79.344 23.76 79.368 ;
    END
  END dst_d[399]
  PIN dst_d[39]
    DIRECTION OUTPUT ;
    USE SIGNAL ;
    PORT
      LAYER M4 ;
        RECT  23.676 10.08 23.76 10.104 ;
    END
  END dst_d[39]
  PIN dst_d[3]
    DIRECTION OUTPUT ;
    USE SIGNAL ;
    PORT
      LAYER M4 ;
        RECT  23.676 3.168 23.76 3.192 ;
    END
  END dst_d[3]
  PIN dst_d[400]
    DIRECTION OUTPUT ;
    USE SIGNAL ;
    PORT
      LAYER M4 ;
        RECT  23.676 79.536 23.76 79.56 ;
    END
  END dst_d[400]
  PIN dst_d[401]
    DIRECTION OUTPUT ;
    USE SIGNAL ;
    PORT
      LAYER M4 ;
        RECT  23.676 79.776 23.76 79.8 ;
    END
  END dst_d[401]
  PIN dst_d[402]
    DIRECTION OUTPUT ;
    USE SIGNAL ;
    PORT
      LAYER M4 ;
        RECT  23.676 79.968 23.76 79.992 ;
    END
  END dst_d[402]
  PIN dst_d[403]
    DIRECTION OUTPUT ;
    USE SIGNAL ;
    PORT
      LAYER M4 ;
        RECT  23.676 80.16 23.76 80.184 ;
    END
  END dst_d[403]
  PIN dst_d[404]
    DIRECTION OUTPUT ;
    USE SIGNAL ;
    PORT
      LAYER M4 ;
        RECT  23.676 80.352 23.76 80.376 ;
    END
  END dst_d[404]
  PIN dst_d[405]
    DIRECTION OUTPUT ;
    USE SIGNAL ;
    PORT
      LAYER M4 ;
        RECT  23.676 80.544 23.76 80.568 ;
    END
  END dst_d[405]
  PIN dst_d[406]
    DIRECTION OUTPUT ;
    USE SIGNAL ;
    PORT
      LAYER M4 ;
        RECT  23.676 80.736 23.76 80.76 ;
    END
  END dst_d[406]
  PIN dst_d[407]
    DIRECTION OUTPUT ;
    USE SIGNAL ;
    PORT
      LAYER M4 ;
        RECT  23.676 80.928 23.76 80.952 ;
    END
  END dst_d[407]
  PIN dst_d[408]
    DIRECTION OUTPUT ;
    USE SIGNAL ;
    PORT
      LAYER M4 ;
        RECT  23.676 81.12 23.76 81.144 ;
    END
  END dst_d[408]
  PIN dst_d[409]
    DIRECTION OUTPUT ;
    USE SIGNAL ;
    PORT
      LAYER M4 ;
        RECT  23.676 81.312 23.76 81.336 ;
    END
  END dst_d[409]
  PIN dst_d[40]
    DIRECTION OUTPUT ;
    USE SIGNAL ;
    PORT
      LAYER M4 ;
        RECT  23.676 10.272 23.76 10.296 ;
    END
  END dst_d[40]
  PIN dst_d[410]
    DIRECTION OUTPUT ;
    USE SIGNAL ;
    PORT
      LAYER M4 ;
        RECT  23.676 81.504 23.76 81.528 ;
    END
  END dst_d[410]
  PIN dst_d[411]
    DIRECTION OUTPUT ;
    USE SIGNAL ;
    PORT
      LAYER M4 ;
        RECT  23.676 81.696 23.76 81.72 ;
    END
  END dst_d[411]
  PIN dst_d[412]
    DIRECTION OUTPUT ;
    USE SIGNAL ;
    PORT
      LAYER M4 ;
        RECT  23.676 81.888 23.76 81.912 ;
    END
  END dst_d[412]
  PIN dst_d[413]
    DIRECTION OUTPUT ;
    USE SIGNAL ;
    PORT
      LAYER M4 ;
        RECT  23.676 82.08 23.76 82.104 ;
    END
  END dst_d[413]
  PIN dst_d[414]
    DIRECTION OUTPUT ;
    USE SIGNAL ;
    PORT
      LAYER M4 ;
        RECT  23.676 82.272 23.76 82.296 ;
    END
  END dst_d[414]
  PIN dst_d[415]
    DIRECTION OUTPUT ;
    USE SIGNAL ;
    PORT
      LAYER M4 ;
        RECT  23.676 82.464 23.76 82.488 ;
    END
  END dst_d[415]
  PIN dst_d[416]
    DIRECTION OUTPUT ;
    USE SIGNAL ;
    PORT
      LAYER M4 ;
        RECT  23.676 82.656 23.76 82.68 ;
    END
  END dst_d[416]
  PIN dst_d[417]
    DIRECTION OUTPUT ;
    USE SIGNAL ;
    PORT
      LAYER M4 ;
        RECT  23.676 82.848 23.76 82.872 ;
    END
  END dst_d[417]
  PIN dst_d[418]
    DIRECTION OUTPUT ;
    USE SIGNAL ;
    PORT
      LAYER M4 ;
        RECT  23.676 83.04 23.76 83.064 ;
    END
  END dst_d[418]
  PIN dst_d[419]
    DIRECTION OUTPUT ;
    USE SIGNAL ;
    PORT
      LAYER M4 ;
        RECT  23.676 83.232 23.76 83.256 ;
    END
  END dst_d[419]
  PIN dst_d[41]
    DIRECTION OUTPUT ;
    USE SIGNAL ;
    PORT
      LAYER M4 ;
        RECT  23.676 10.464 23.76 10.488 ;
    END
  END dst_d[41]
  PIN dst_d[420]
    DIRECTION OUTPUT ;
    USE SIGNAL ;
    PORT
      LAYER M4 ;
        RECT  23.676 83.424 23.76 83.448 ;
    END
  END dst_d[420]
  PIN dst_d[421]
    DIRECTION OUTPUT ;
    USE SIGNAL ;
    PORT
      LAYER M4 ;
        RECT  23.676 83.616 23.76 83.64 ;
    END
  END dst_d[421]
  PIN dst_d[422]
    DIRECTION OUTPUT ;
    USE SIGNAL ;
    PORT
      LAYER M4 ;
        RECT  23.676 83.808 23.76 83.832 ;
    END
  END dst_d[422]
  PIN dst_d[423]
    DIRECTION OUTPUT ;
    USE SIGNAL ;
    PORT
      LAYER M4 ;
        RECT  23.676 84 23.76 84.024 ;
    END
  END dst_d[423]
  PIN dst_d[424]
    DIRECTION OUTPUT ;
    USE SIGNAL ;
    PORT
      LAYER M4 ;
        RECT  23.676 84.192 23.76 84.216 ;
    END
  END dst_d[424]
  PIN dst_d[425]
    DIRECTION OUTPUT ;
    USE SIGNAL ;
    PORT
      LAYER M4 ;
        RECT  23.676 84.384 23.76 84.408 ;
    END
  END dst_d[425]
  PIN dst_d[426]
    DIRECTION OUTPUT ;
    USE SIGNAL ;
    PORT
      LAYER M4 ;
        RECT  23.676 84.576 23.76 84.6 ;
    END
  END dst_d[426]
  PIN dst_d[427]
    DIRECTION OUTPUT ;
    USE SIGNAL ;
    PORT
      LAYER M4 ;
        RECT  23.676 84.768 23.76 84.792 ;
    END
  END dst_d[427]
  PIN dst_d[428]
    DIRECTION OUTPUT ;
    USE SIGNAL ;
    PORT
      LAYER M4 ;
        RECT  23.676 84.96 23.76 84.984 ;
    END
  END dst_d[428]
  PIN dst_d[429]
    DIRECTION OUTPUT ;
    USE SIGNAL ;
    PORT
      LAYER M4 ;
        RECT  23.676 85.152 23.76 85.176 ;
    END
  END dst_d[429]
  PIN dst_d[42]
    DIRECTION OUTPUT ;
    USE SIGNAL ;
    PORT
      LAYER M4 ;
        RECT  23.676 10.656 23.76 10.68 ;
    END
  END dst_d[42]
  PIN dst_d[430]
    DIRECTION OUTPUT ;
    USE SIGNAL ;
    PORT
      LAYER M4 ;
        RECT  23.676 85.344 23.76 85.368 ;
    END
  END dst_d[430]
  PIN dst_d[431]
    DIRECTION OUTPUT ;
    USE SIGNAL ;
    PORT
      LAYER M4 ;
        RECT  23.676 85.536 23.76 85.56 ;
    END
  END dst_d[431]
  PIN dst_d[432]
    DIRECTION OUTPUT ;
    USE SIGNAL ;
    PORT
      LAYER M4 ;
        RECT  23.676 85.728 23.76 85.752 ;
    END
  END dst_d[432]
  PIN dst_d[433]
    DIRECTION OUTPUT ;
    USE SIGNAL ;
    PORT
      LAYER M4 ;
        RECT  23.676 85.92 23.76 85.944 ;
    END
  END dst_d[433]
  PIN dst_d[434]
    DIRECTION OUTPUT ;
    USE SIGNAL ;
    PORT
      LAYER M4 ;
        RECT  23.676 86.112 23.76 86.136 ;
    END
  END dst_d[434]
  PIN dst_d[435]
    DIRECTION OUTPUT ;
    USE SIGNAL ;
    PORT
      LAYER M4 ;
        RECT  23.676 86.304 23.76 86.328 ;
    END
  END dst_d[435]
  PIN dst_d[436]
    DIRECTION OUTPUT ;
    USE SIGNAL ;
    PORT
      LAYER M4 ;
        RECT  23.676 86.496 23.76 86.52 ;
    END
  END dst_d[436]
  PIN dst_d[437]
    DIRECTION OUTPUT ;
    USE SIGNAL ;
    PORT
      LAYER M4 ;
        RECT  23.676 86.688 23.76 86.712 ;
    END
  END dst_d[437]
  PIN dst_d[438]
    DIRECTION OUTPUT ;
    USE SIGNAL ;
    PORT
      LAYER M4 ;
        RECT  23.676 86.88 23.76 86.904 ;
    END
  END dst_d[438]
  PIN dst_d[439]
    DIRECTION OUTPUT ;
    USE SIGNAL ;
    PORT
      LAYER M4 ;
        RECT  23.676 87.072 23.76 87.096 ;
    END
  END dst_d[439]
  PIN dst_d[43]
    DIRECTION OUTPUT ;
    USE SIGNAL ;
    PORT
      LAYER M4 ;
        RECT  23.676 10.848 23.76 10.872 ;
    END
  END dst_d[43]
  PIN dst_d[440]
    DIRECTION OUTPUT ;
    USE SIGNAL ;
    PORT
      LAYER M4 ;
        RECT  23.676 87.264 23.76 87.288 ;
    END
  END dst_d[440]
  PIN dst_d[441]
    DIRECTION OUTPUT ;
    USE SIGNAL ;
    PORT
      LAYER M4 ;
        RECT  23.676 87.456 23.76 87.48 ;
    END
  END dst_d[441]
  PIN dst_d[442]
    DIRECTION OUTPUT ;
    USE SIGNAL ;
    PORT
      LAYER M4 ;
        RECT  23.676 87.648 23.76 87.672 ;
    END
  END dst_d[442]
  PIN dst_d[443]
    DIRECTION OUTPUT ;
    USE SIGNAL ;
    PORT
      LAYER M4 ;
        RECT  23.676 87.84 23.76 87.864 ;
    END
  END dst_d[443]
  PIN dst_d[444]
    DIRECTION OUTPUT ;
    USE SIGNAL ;
    PORT
      LAYER M4 ;
        RECT  23.676 88.032 23.76 88.056 ;
    END
  END dst_d[444]
  PIN dst_d[445]
    DIRECTION OUTPUT ;
    USE SIGNAL ;
    PORT
      LAYER M4 ;
        RECT  23.676 88.224 23.76 88.248 ;
    END
  END dst_d[445]
  PIN dst_d[446]
    DIRECTION OUTPUT ;
    USE SIGNAL ;
    PORT
      LAYER M4 ;
        RECT  23.676 88.416 23.76 88.44 ;
    END
  END dst_d[446]
  PIN dst_d[447]
    DIRECTION OUTPUT ;
    USE SIGNAL ;
    PORT
      LAYER M4 ;
        RECT  23.676 88.608 23.76 88.632 ;
    END
  END dst_d[447]
  PIN dst_d[448]
    DIRECTION OUTPUT ;
    USE SIGNAL ;
    PORT
      LAYER M4 ;
        RECT  23.676 88.8 23.76 88.824 ;
    END
  END dst_d[448]
  PIN dst_d[449]
    DIRECTION OUTPUT ;
    USE SIGNAL ;
    PORT
      LAYER M4 ;
        RECT  23.676 88.992 23.76 89.016 ;
    END
  END dst_d[449]
  PIN dst_d[44]
    DIRECTION OUTPUT ;
    USE SIGNAL ;
    PORT
      LAYER M4 ;
        RECT  23.676 11.04 23.76 11.064 ;
    END
  END dst_d[44]
  PIN dst_d[450]
    DIRECTION OUTPUT ;
    USE SIGNAL ;
    PORT
      LAYER M4 ;
        RECT  23.676 89.184 23.76 89.208 ;
    END
  END dst_d[450]
  PIN dst_d[451]
    DIRECTION OUTPUT ;
    USE SIGNAL ;
    PORT
      LAYER M4 ;
        RECT  23.676 89.376 23.76 89.4 ;
    END
  END dst_d[451]
  PIN dst_d[452]
    DIRECTION OUTPUT ;
    USE SIGNAL ;
    PORT
      LAYER M4 ;
        RECT  23.676 89.568 23.76 89.592 ;
    END
  END dst_d[452]
  PIN dst_d[453]
    DIRECTION OUTPUT ;
    USE SIGNAL ;
    PORT
      LAYER M4 ;
        RECT  23.676 89.76 23.76 89.784 ;
    END
  END dst_d[453]
  PIN dst_d[454]
    DIRECTION OUTPUT ;
    USE SIGNAL ;
    PORT
      LAYER M4 ;
        RECT  23.676 89.952 23.76 89.976 ;
    END
  END dst_d[454]
  PIN dst_d[455]
    DIRECTION OUTPUT ;
    USE SIGNAL ;
    PORT
      LAYER M4 ;
        RECT  23.676 90.144 23.76 90.168 ;
    END
  END dst_d[455]
  PIN dst_d[456]
    DIRECTION OUTPUT ;
    USE SIGNAL ;
    PORT
      LAYER M4 ;
        RECT  23.676 90.336 23.76 90.36 ;
    END
  END dst_d[456]
  PIN dst_d[457]
    DIRECTION OUTPUT ;
    USE SIGNAL ;
    PORT
      LAYER M4 ;
        RECT  23.676 90.528 23.76 90.552 ;
    END
  END dst_d[457]
  PIN dst_d[458]
    DIRECTION OUTPUT ;
    USE SIGNAL ;
    PORT
      LAYER M4 ;
        RECT  23.676 90.72 23.76 90.744 ;
    END
  END dst_d[458]
  PIN dst_d[459]
    DIRECTION OUTPUT ;
    USE SIGNAL ;
    PORT
      LAYER M4 ;
        RECT  23.676 90.912 23.76 90.936 ;
    END
  END dst_d[459]
  PIN dst_d[45]
    DIRECTION OUTPUT ;
    USE SIGNAL ;
    PORT
      LAYER M4 ;
        RECT  23.676 11.232 23.76 11.256 ;
    END
  END dst_d[45]
  PIN dst_d[460]
    DIRECTION OUTPUT ;
    USE SIGNAL ;
    PORT
      LAYER M4 ;
        RECT  23.676 91.104 23.76 91.128 ;
    END
  END dst_d[460]
  PIN dst_d[461]
    DIRECTION OUTPUT ;
    USE SIGNAL ;
    PORT
      LAYER M4 ;
        RECT  23.676 91.296 23.76 91.32 ;
    END
  END dst_d[461]
  PIN dst_d[462]
    DIRECTION OUTPUT ;
    USE SIGNAL ;
    PORT
      LAYER M4 ;
        RECT  23.676 91.488 23.76 91.512 ;
    END
  END dst_d[462]
  PIN dst_d[463]
    DIRECTION OUTPUT ;
    USE SIGNAL ;
    PORT
      LAYER M4 ;
        RECT  23.676 91.68 23.76 91.704 ;
    END
  END dst_d[463]
  PIN dst_d[464]
    DIRECTION OUTPUT ;
    USE SIGNAL ;
    PORT
      LAYER M4 ;
        RECT  23.676 91.872 23.76 91.896 ;
    END
  END dst_d[464]
  PIN dst_d[465]
    DIRECTION OUTPUT ;
    USE SIGNAL ;
    PORT
      LAYER M4 ;
        RECT  23.676 92.064 23.76 92.088 ;
    END
  END dst_d[465]
  PIN dst_d[466]
    DIRECTION OUTPUT ;
    USE SIGNAL ;
    PORT
      LAYER M4 ;
        RECT  23.676 92.256 23.76 92.28 ;
    END
  END dst_d[466]
  PIN dst_d[467]
    DIRECTION OUTPUT ;
    USE SIGNAL ;
    PORT
      LAYER M4 ;
        RECT  23.676 92.448 23.76 92.472 ;
    END
  END dst_d[467]
  PIN dst_d[468]
    DIRECTION OUTPUT ;
    USE SIGNAL ;
    PORT
      LAYER M4 ;
        RECT  23.676 92.64 23.76 92.664 ;
    END
  END dst_d[468]
  PIN dst_d[469]
    DIRECTION OUTPUT ;
    USE SIGNAL ;
    PORT
      LAYER M4 ;
        RECT  23.676 92.832 23.76 92.856 ;
    END
  END dst_d[469]
  PIN dst_d[46]
    DIRECTION OUTPUT ;
    USE SIGNAL ;
    PORT
      LAYER M4 ;
        RECT  23.676 11.424 23.76 11.448 ;
    END
  END dst_d[46]
  PIN dst_d[470]
    DIRECTION OUTPUT ;
    USE SIGNAL ;
    PORT
      LAYER M4 ;
        RECT  23.676 93.024 23.76 93.048 ;
    END
  END dst_d[470]
  PIN dst_d[471]
    DIRECTION OUTPUT ;
    USE SIGNAL ;
    PORT
      LAYER M4 ;
        RECT  23.676 93.216 23.76 93.24 ;
    END
  END dst_d[471]
  PIN dst_d[472]
    DIRECTION OUTPUT ;
    USE SIGNAL ;
    PORT
      LAYER M4 ;
        RECT  23.676 93.408 23.76 93.432 ;
    END
  END dst_d[472]
  PIN dst_d[473]
    DIRECTION OUTPUT ;
    USE SIGNAL ;
    PORT
      LAYER M4 ;
        RECT  23.676 93.6 23.76 93.624 ;
    END
  END dst_d[473]
  PIN dst_d[474]
    DIRECTION OUTPUT ;
    USE SIGNAL ;
    PORT
      LAYER M4 ;
        RECT  23.676 93.792 23.76 93.816 ;
    END
  END dst_d[474]
  PIN dst_d[475]
    DIRECTION OUTPUT ;
    USE SIGNAL ;
    PORT
      LAYER M4 ;
        RECT  23.676 93.984 23.76 94.008 ;
    END
  END dst_d[475]
  PIN dst_d[476]
    DIRECTION OUTPUT ;
    USE SIGNAL ;
    PORT
      LAYER M4 ;
        RECT  23.676 94.176 23.76 94.2 ;
    END
  END dst_d[476]
  PIN dst_d[477]
    DIRECTION OUTPUT ;
    USE SIGNAL ;
    PORT
      LAYER M4 ;
        RECT  23.676 94.368 23.76 94.392 ;
    END
  END dst_d[477]
  PIN dst_d[478]
    DIRECTION OUTPUT ;
    USE SIGNAL ;
    PORT
      LAYER M4 ;
        RECT  23.676 94.56 23.76 94.584 ;
    END
  END dst_d[478]
  PIN dst_d[479]
    DIRECTION OUTPUT ;
    USE SIGNAL ;
    PORT
      LAYER M4 ;
        RECT  23.676 94.752 23.76 94.776 ;
    END
  END dst_d[479]
  PIN dst_d[47]
    DIRECTION OUTPUT ;
    USE SIGNAL ;
    PORT
      LAYER M4 ;
        RECT  23.676 11.616 23.76 11.64 ;
    END
  END dst_d[47]
  PIN dst_d[48]
    DIRECTION OUTPUT ;
    USE SIGNAL ;
    PORT
      LAYER M4 ;
        RECT  23.676 11.808 23.76 11.832 ;
    END
  END dst_d[48]
  PIN dst_d[49]
    DIRECTION OUTPUT ;
    USE SIGNAL ;
    PORT
      LAYER M4 ;
        RECT  23.676 12 23.76 12.024 ;
    END
  END dst_d[49]
  PIN dst_d[4]
    DIRECTION OUTPUT ;
    USE SIGNAL ;
    PORT
      LAYER M4 ;
        RECT  23.676 3.36 23.76 3.384 ;
    END
  END dst_d[4]
  PIN dst_d[50]
    DIRECTION OUTPUT ;
    USE SIGNAL ;
    PORT
      LAYER M4 ;
        RECT  23.676 12.192 23.76 12.216 ;
    END
  END dst_d[50]
  PIN dst_d[51]
    DIRECTION OUTPUT ;
    USE SIGNAL ;
    PORT
      LAYER M4 ;
        RECT  23.676 12.384 23.76 12.408 ;
    END
  END dst_d[51]
  PIN dst_d[52]
    DIRECTION OUTPUT ;
    USE SIGNAL ;
    PORT
      LAYER M4 ;
        RECT  23.676 12.576 23.76 12.6 ;
    END
  END dst_d[52]
  PIN dst_d[53]
    DIRECTION OUTPUT ;
    USE SIGNAL ;
    PORT
      LAYER M4 ;
        RECT  23.676 12.768 23.76 12.792 ;
    END
  END dst_d[53]
  PIN dst_d[54]
    DIRECTION OUTPUT ;
    USE SIGNAL ;
    PORT
      LAYER M4 ;
        RECT  23.676 12.96 23.76 12.984 ;
    END
  END dst_d[54]
  PIN dst_d[55]
    DIRECTION OUTPUT ;
    USE SIGNAL ;
    PORT
      LAYER M4 ;
        RECT  23.676 13.152 23.76 13.176 ;
    END
  END dst_d[55]
  PIN dst_d[56]
    DIRECTION OUTPUT ;
    USE SIGNAL ;
    PORT
      LAYER M4 ;
        RECT  23.676 13.344 23.76 13.368 ;
    END
  END dst_d[56]
  PIN dst_d[57]
    DIRECTION OUTPUT ;
    USE SIGNAL ;
    PORT
      LAYER M4 ;
        RECT  23.676 13.536 23.76 13.56 ;
    END
  END dst_d[57]
  PIN dst_d[58]
    DIRECTION OUTPUT ;
    USE SIGNAL ;
    PORT
      LAYER M4 ;
        RECT  23.676 13.728 23.76 13.752 ;
    END
  END dst_d[58]
  PIN dst_d[59]
    DIRECTION OUTPUT ;
    USE SIGNAL ;
    PORT
      LAYER M4 ;
        RECT  23.676 13.92 23.76 13.944 ;
    END
  END dst_d[59]
  PIN dst_d[5]
    DIRECTION OUTPUT ;
    USE SIGNAL ;
    PORT
      LAYER M4 ;
        RECT  23.676 3.552 23.76 3.576 ;
    END
  END dst_d[5]
  PIN dst_d[60]
    DIRECTION OUTPUT ;
    USE SIGNAL ;
    PORT
      LAYER M4 ;
        RECT  23.676 14.112 23.76 14.136 ;
    END
  END dst_d[60]
  PIN dst_d[61]
    DIRECTION OUTPUT ;
    USE SIGNAL ;
    PORT
      LAYER M4 ;
        RECT  23.676 14.304 23.76 14.328 ;
    END
  END dst_d[61]
  PIN dst_d[62]
    DIRECTION OUTPUT ;
    USE SIGNAL ;
    PORT
      LAYER M4 ;
        RECT  23.676 14.496 23.76 14.52 ;
    END
  END dst_d[62]
  PIN dst_d[63]
    DIRECTION OUTPUT ;
    USE SIGNAL ;
    PORT
      LAYER M4 ;
        RECT  23.676 14.688 23.76 14.712 ;
    END
  END dst_d[63]
  PIN dst_d[64]
    DIRECTION OUTPUT ;
    USE SIGNAL ;
    PORT
      LAYER M4 ;
        RECT  23.676 14.88 23.76 14.904 ;
    END
  END dst_d[64]
  PIN dst_d[65]
    DIRECTION OUTPUT ;
    USE SIGNAL ;
    PORT
      LAYER M4 ;
        RECT  23.676 15.072 23.76 15.096 ;
    END
  END dst_d[65]
  PIN dst_d[66]
    DIRECTION OUTPUT ;
    USE SIGNAL ;
    PORT
      LAYER M4 ;
        RECT  23.676 15.264 23.76 15.288 ;
    END
  END dst_d[66]
  PIN dst_d[67]
    DIRECTION OUTPUT ;
    USE SIGNAL ;
    PORT
      LAYER M4 ;
        RECT  23.676 15.456 23.76 15.48 ;
    END
  END dst_d[67]
  PIN dst_d[68]
    DIRECTION OUTPUT ;
    USE SIGNAL ;
    PORT
      LAYER M4 ;
        RECT  23.676 15.648 23.76 15.672 ;
    END
  END dst_d[68]
  PIN dst_d[69]
    DIRECTION OUTPUT ;
    USE SIGNAL ;
    PORT
      LAYER M4 ;
        RECT  23.676 15.84 23.76 15.864 ;
    END
  END dst_d[69]
  PIN dst_d[6]
    DIRECTION OUTPUT ;
    USE SIGNAL ;
    PORT
      LAYER M4 ;
        RECT  23.676 3.744 23.76 3.768 ;
    END
  END dst_d[6]
  PIN dst_d[70]
    DIRECTION OUTPUT ;
    USE SIGNAL ;
    PORT
      LAYER M4 ;
        RECT  23.676 16.032 23.76 16.056 ;
    END
  END dst_d[70]
  PIN dst_d[71]
    DIRECTION OUTPUT ;
    USE SIGNAL ;
    PORT
      LAYER M4 ;
        RECT  23.676 16.224 23.76 16.248 ;
    END
  END dst_d[71]
  PIN dst_d[72]
    DIRECTION OUTPUT ;
    USE SIGNAL ;
    PORT
      LAYER M4 ;
        RECT  23.676 16.464 23.76 16.488 ;
    END
  END dst_d[72]
  PIN dst_d[73]
    DIRECTION OUTPUT ;
    USE SIGNAL ;
    PORT
      LAYER M4 ;
        RECT  23.676 16.656 23.76 16.68 ;
    END
  END dst_d[73]
  PIN dst_d[74]
    DIRECTION OUTPUT ;
    USE SIGNAL ;
    PORT
      LAYER M4 ;
        RECT  23.676 16.848 23.76 16.872 ;
    END
  END dst_d[74]
  PIN dst_d[75]
    DIRECTION OUTPUT ;
    USE SIGNAL ;
    PORT
      LAYER M4 ;
        RECT  23.676 17.04 23.76 17.064 ;
    END
  END dst_d[75]
  PIN dst_d[76]
    DIRECTION OUTPUT ;
    USE SIGNAL ;
    PORT
      LAYER M4 ;
        RECT  23.676 17.232 23.76 17.256 ;
    END
  END dst_d[76]
  PIN dst_d[77]
    DIRECTION OUTPUT ;
    USE SIGNAL ;
    PORT
      LAYER M4 ;
        RECT  23.676 17.424 23.76 17.448 ;
    END
  END dst_d[77]
  PIN dst_d[78]
    DIRECTION OUTPUT ;
    USE SIGNAL ;
    PORT
      LAYER M4 ;
        RECT  23.676 17.616 23.76 17.64 ;
    END
  END dst_d[78]
  PIN dst_d[79]
    DIRECTION OUTPUT ;
    USE SIGNAL ;
    PORT
      LAYER M4 ;
        RECT  23.676 17.808 23.76 17.832 ;
    END
  END dst_d[79]
  PIN dst_d[7]
    DIRECTION OUTPUT ;
    USE SIGNAL ;
    PORT
      LAYER M4 ;
        RECT  23.676 3.936 23.76 3.96 ;
    END
  END dst_d[7]
  PIN dst_d[80]
    DIRECTION OUTPUT ;
    USE SIGNAL ;
    PORT
      LAYER M4 ;
        RECT  23.676 18 23.76 18.024 ;
    END
  END dst_d[80]
  PIN dst_d[81]
    DIRECTION OUTPUT ;
    USE SIGNAL ;
    PORT
      LAYER M4 ;
        RECT  23.676 18.192 23.76 18.216 ;
    END
  END dst_d[81]
  PIN dst_d[82]
    DIRECTION OUTPUT ;
    USE SIGNAL ;
    PORT
      LAYER M4 ;
        RECT  23.676 18.384 23.76 18.408 ;
    END
  END dst_d[82]
  PIN dst_d[83]
    DIRECTION OUTPUT ;
    USE SIGNAL ;
    PORT
      LAYER M4 ;
        RECT  23.676 18.576 23.76 18.6 ;
    END
  END dst_d[83]
  PIN dst_d[84]
    DIRECTION OUTPUT ;
    USE SIGNAL ;
    PORT
      LAYER M4 ;
        RECT  23.676 18.768 23.76 18.792 ;
    END
  END dst_d[84]
  PIN dst_d[85]
    DIRECTION OUTPUT ;
    USE SIGNAL ;
    PORT
      LAYER M4 ;
        RECT  23.676 18.96 23.76 18.984 ;
    END
  END dst_d[85]
  PIN dst_d[86]
    DIRECTION OUTPUT ;
    USE SIGNAL ;
    PORT
      LAYER M4 ;
        RECT  23.676 19.152 23.76 19.176 ;
    END
  END dst_d[86]
  PIN dst_d[87]
    DIRECTION OUTPUT ;
    USE SIGNAL ;
    PORT
      LAYER M4 ;
        RECT  23.676 19.344 23.76 19.368 ;
    END
  END dst_d[87]
  PIN dst_d[88]
    DIRECTION OUTPUT ;
    USE SIGNAL ;
    PORT
      LAYER M4 ;
        RECT  23.676 19.536 23.76 19.56 ;
    END
  END dst_d[88]
  PIN dst_d[89]
    DIRECTION OUTPUT ;
    USE SIGNAL ;
    PORT
      LAYER M4 ;
        RECT  23.676 19.728 23.76 19.752 ;
    END
  END dst_d[89]
  PIN dst_d[8]
    DIRECTION OUTPUT ;
    USE SIGNAL ;
    PORT
      LAYER M4 ;
        RECT  23.676 4.128 23.76 4.152 ;
    END
  END dst_d[8]
  PIN dst_d[90]
    DIRECTION OUTPUT ;
    USE SIGNAL ;
    PORT
      LAYER M4 ;
        RECT  23.676 19.92 23.76 19.944 ;
    END
  END dst_d[90]
  PIN dst_d[91]
    DIRECTION OUTPUT ;
    USE SIGNAL ;
    PORT
      LAYER M4 ;
        RECT  23.676 20.112 23.76 20.136 ;
    END
  END dst_d[91]
  PIN dst_d[92]
    DIRECTION OUTPUT ;
    USE SIGNAL ;
    PORT
      LAYER M4 ;
        RECT  23.676 20.304 23.76 20.328 ;
    END
  END dst_d[92]
  PIN dst_d[93]
    DIRECTION OUTPUT ;
    USE SIGNAL ;
    PORT
      LAYER M4 ;
        RECT  23.676 20.496 23.76 20.52 ;
    END
  END dst_d[93]
  PIN dst_d[94]
    DIRECTION OUTPUT ;
    USE SIGNAL ;
    PORT
      LAYER M4 ;
        RECT  23.676 20.688 23.76 20.712 ;
    END
  END dst_d[94]
  PIN dst_d[95]
    DIRECTION OUTPUT ;
    USE SIGNAL ;
    PORT
      LAYER M4 ;
        RECT  23.676 20.88 23.76 20.904 ;
    END
  END dst_d[95]
  PIN dst_d[96]
    DIRECTION OUTPUT ;
    USE SIGNAL ;
    PORT
      LAYER M4 ;
        RECT  23.676 21.072 23.76 21.096 ;
    END
  END dst_d[96]
  PIN dst_d[97]
    DIRECTION OUTPUT ;
    USE SIGNAL ;
    PORT
      LAYER M4 ;
        RECT  23.676 21.264 23.76 21.288 ;
    END
  END dst_d[97]
  PIN dst_d[98]
    DIRECTION OUTPUT ;
    USE SIGNAL ;
    PORT
      LAYER M4 ;
        RECT  23.676 21.456 23.76 21.48 ;
    END
  END dst_d[98]
  PIN dst_d[99]
    DIRECTION OUTPUT ;
    USE SIGNAL ;
    PORT
      LAYER M4 ;
        RECT  23.676 21.648 23.76 21.672 ;
    END
  END dst_d[99]
  PIN dst_d[9]
    DIRECTION OUTPUT ;
    USE SIGNAL ;
    PORT
      LAYER M4 ;
        RECT  23.676 4.32 23.76 4.344 ;
    END
  END dst_d[9]
  PIN dst_v[0]
    DIRECTION OUTPUT ;
    USE SIGNAL ;
    PORT
      LAYER M4 ;
        RECT  23.676 95.184 23.76 95.208 ;
    END
  END dst_v[0]
  PIN dst_v[10]
    DIRECTION OUTPUT ;
    USE SIGNAL ;
    PORT
      LAYER M4 ;
        RECT  23.676 97.68 23.76 97.704 ;
    END
  END dst_v[10]
  PIN dst_v[11]
    DIRECTION OUTPUT ;
    USE SIGNAL ;
    PORT
      LAYER M4 ;
        RECT  23.676 97.92 23.76 97.944 ;
    END
  END dst_v[11]
  PIN dst_v[12]
    DIRECTION OUTPUT ;
    USE SIGNAL ;
    PORT
      LAYER M4 ;
        RECT  23.676 98.16 23.76 98.184 ;
    END
  END dst_v[12]
  PIN dst_v[13]
    DIRECTION OUTPUT ;
    USE SIGNAL ;
    PORT
      LAYER M4 ;
        RECT  23.676 98.448 23.76 98.472 ;
    END
  END dst_v[13]
  PIN dst_v[14]
    DIRECTION OUTPUT ;
    USE SIGNAL ;
    PORT
      LAYER M4 ;
        RECT  23.676 98.688 23.76 98.712 ;
    END
  END dst_v[14]
  PIN dst_v[1]
    DIRECTION OUTPUT ;
    USE SIGNAL ;
    PORT
      LAYER M4 ;
        RECT  23.676 95.424 23.76 95.448 ;
    END
  END dst_v[1]
  PIN dst_v[2]
    DIRECTION OUTPUT ;
    USE SIGNAL ;
    PORT
      LAYER M4 ;
        RECT  23.676 95.664 23.76 95.688 ;
    END
  END dst_v[2]
  PIN dst_v[3]
    DIRECTION OUTPUT ;
    USE SIGNAL ;
    PORT
      LAYER M4 ;
        RECT  23.676 95.952 23.76 95.976 ;
    END
  END dst_v[3]
  PIN dst_v[4]
    DIRECTION OUTPUT ;
    USE SIGNAL ;
    PORT
      LAYER M4 ;
        RECT  23.676 96.192 23.76 96.216 ;
    END
  END dst_v[4]
  PIN dst_v[5]
    DIRECTION OUTPUT ;
    USE SIGNAL ;
    PORT
      LAYER M4 ;
        RECT  23.676 96.432 23.76 96.456 ;
    END
  END dst_v[5]
  PIN dst_v[6]
    DIRECTION OUTPUT ;
    USE SIGNAL ;
    PORT
      LAYER M4 ;
        RECT  23.676 96.672 23.76 96.696 ;
    END
  END dst_v[6]
  PIN dst_v[7]
    DIRECTION OUTPUT ;
    USE SIGNAL ;
    PORT
      LAYER M4 ;
        RECT  23.676 96.912 23.76 96.936 ;
    END
  END dst_v[7]
  PIN dst_v[8]
    DIRECTION OUTPUT ;
    USE SIGNAL ;
    PORT
      LAYER M4 ;
        RECT  23.676 97.2 23.76 97.224 ;
    END
  END dst_v[8]
  PIN dst_v[9]
    DIRECTION OUTPUT ;
    USE SIGNAL ;
    PORT
      LAYER M4 ;
        RECT  23.676 97.44 23.76 97.464 ;
    END
  END dst_v[9]
  PIN rst_n
    DIRECTION INPUT ;
    USE SIGNAL ;
    PORT
      LAYER M5 ;
        RECT  22.272 101.436 22.296 101.52 ;
    END
  END rst_n
  PIN select_fault
    DIRECTION OUTPUT ;
    USE SIGNAL ;
    PORT
      LAYER M5 ;
        RECT  22.8 101.436 22.824 101.52 ;
    END
  END select_fault
  PIN sink_select[0]
    DIRECTION INPUT ;
    USE SIGNAL ;
    PORT
      LAYER M5 ;
        RECT  6.576 101.436 6.6 101.52 ;
    END
  END sink_select[0]
  PIN sink_select[10]
    DIRECTION INPUT ;
    USE SIGNAL ;
    PORT
      LAYER M5 ;
        RECT  9.072 101.436 9.096 101.52 ;
    END
  END sink_select[10]
  PIN sink_select[11]
    DIRECTION INPUT ;
    USE SIGNAL ;
    PORT
      LAYER M5 ;
        RECT  9.312 101.436 9.336 101.52 ;
    END
  END sink_select[11]
  PIN sink_select[12]
    DIRECTION INPUT ;
    USE SIGNAL ;
    PORT
      LAYER M5 ;
        RECT  9.552 101.436 9.576 101.52 ;
    END
  END sink_select[12]
  PIN sink_select[13]
    DIRECTION INPUT ;
    USE SIGNAL ;
    PORT
      LAYER M5 ;
        RECT  9.792 101.436 9.816 101.52 ;
    END
  END sink_select[13]
  PIN sink_select[14]
    DIRECTION INPUT ;
    USE SIGNAL ;
    PORT
      LAYER M5 ;
        RECT  10.08 101.436 10.104 101.52 ;
    END
  END sink_select[14]
  PIN sink_select[15]
    DIRECTION INPUT ;
    USE SIGNAL ;
    PORT
      LAYER M5 ;
        RECT  10.32 101.436 10.344 101.52 ;
    END
  END sink_select[15]
  PIN sink_select[16]
    DIRECTION INPUT ;
    USE SIGNAL ;
    PORT
      LAYER M5 ;
        RECT  10.56 101.436 10.584 101.52 ;
    END
  END sink_select[16]
  PIN sink_select[17]
    DIRECTION INPUT ;
    USE SIGNAL ;
    PORT
      LAYER M5 ;
        RECT  10.8 101.436 10.824 101.52 ;
    END
  END sink_select[17]
  PIN sink_select[18]
    DIRECTION INPUT ;
    USE SIGNAL ;
    PORT
      LAYER M5 ;
        RECT  11.04 101.436 11.064 101.52 ;
    END
  END sink_select[18]
  PIN sink_select[19]
    DIRECTION INPUT ;
    USE SIGNAL ;
    PORT
      LAYER M5 ;
        RECT  11.328 101.436 11.352 101.52 ;
    END
  END sink_select[19]
  PIN sink_select[1]
    DIRECTION INPUT ;
    USE SIGNAL ;
    PORT
      LAYER M5 ;
        RECT  6.816 101.436 6.84 101.52 ;
    END
  END sink_select[1]
  PIN sink_select[20]
    DIRECTION INPUT ;
    USE SIGNAL ;
    PORT
      LAYER M5 ;
        RECT  11.568 101.436 11.592 101.52 ;
    END
  END sink_select[20]
  PIN sink_select[21]
    DIRECTION INPUT ;
    USE SIGNAL ;
    PORT
      LAYER M5 ;
        RECT  11.808 101.436 11.832 101.52 ;
    END
  END sink_select[21]
  PIN sink_select[22]
    DIRECTION INPUT ;
    USE SIGNAL ;
    PORT
      LAYER M5 ;
        RECT  12.048 101.436 12.072 101.52 ;
    END
  END sink_select[22]
  PIN sink_select[23]
    DIRECTION INPUT ;
    USE SIGNAL ;
    PORT
      LAYER M5 ;
        RECT  12.336 101.436 12.36 101.52 ;
    END
  END sink_select[23]
  PIN sink_select[24]
    DIRECTION INPUT ;
    USE SIGNAL ;
    PORT
      LAYER M5 ;
        RECT  12.576 101.436 12.6 101.52 ;
    END
  END sink_select[24]
  PIN sink_select[25]
    DIRECTION INPUT ;
    USE SIGNAL ;
    PORT
      LAYER M5 ;
        RECT  12.816 101.436 12.84 101.52 ;
    END
  END sink_select[25]
  PIN sink_select[26]
    DIRECTION INPUT ;
    USE SIGNAL ;
    PORT
      LAYER M5 ;
        RECT  13.056 101.436 13.08 101.52 ;
    END
  END sink_select[26]
  PIN sink_select[27]
    DIRECTION INPUT ;
    USE SIGNAL ;
    PORT
      LAYER M5 ;
        RECT  13.296 101.436 13.32 101.52 ;
    END
  END sink_select[27]
  PIN sink_select[28]
    DIRECTION INPUT ;
    USE SIGNAL ;
    PORT
      LAYER M5 ;
        RECT  13.584 101.436 13.608 101.52 ;
    END
  END sink_select[28]
  PIN sink_select[29]
    DIRECTION INPUT ;
    USE SIGNAL ;
    PORT
      LAYER M5 ;
        RECT  13.824 101.436 13.848 101.52 ;
    END
  END sink_select[29]
  PIN sink_select[2]
    DIRECTION INPUT ;
    USE SIGNAL ;
    PORT
      LAYER M5 ;
        RECT  7.056 101.436 7.08 101.52 ;
    END
  END sink_select[2]
  PIN sink_select[30]
    DIRECTION INPUT ;
    USE SIGNAL ;
    PORT
      LAYER M5 ;
        RECT  14.064 101.436 14.088 101.52 ;
    END
  END sink_select[30]
  PIN sink_select[31]
    DIRECTION INPUT ;
    USE SIGNAL ;
    PORT
      LAYER M5 ;
        RECT  14.304 101.436 14.328 101.52 ;
    END
  END sink_select[31]
  PIN sink_select[32]
    DIRECTION INPUT ;
    USE SIGNAL ;
    PORT
      LAYER M5 ;
        RECT  14.544 101.436 14.568 101.52 ;
    END
  END sink_select[32]
  PIN sink_select[33]
    DIRECTION INPUT ;
    USE SIGNAL ;
    PORT
      LAYER M5 ;
        RECT  14.832 101.436 14.856 101.52 ;
    END
  END sink_select[33]
  PIN sink_select[34]
    DIRECTION INPUT ;
    USE SIGNAL ;
    PORT
      LAYER M5 ;
        RECT  15.072 101.436 15.096 101.52 ;
    END
  END sink_select[34]
  PIN sink_select[35]
    DIRECTION INPUT ;
    USE SIGNAL ;
    PORT
      LAYER M5 ;
        RECT  15.312 101.436 15.336 101.52 ;
    END
  END sink_select[35]
  PIN sink_select[36]
    DIRECTION INPUT ;
    USE SIGNAL ;
    PORT
      LAYER M5 ;
        RECT  15.552 101.436 15.576 101.52 ;
    END
  END sink_select[36]
  PIN sink_select[37]
    DIRECTION INPUT ;
    USE SIGNAL ;
    PORT
      LAYER M5 ;
        RECT  15.792 101.436 15.816 101.52 ;
    END
  END sink_select[37]
  PIN sink_select[38]
    DIRECTION INPUT ;
    USE SIGNAL ;
    PORT
      LAYER M5 ;
        RECT  16.08 101.436 16.104 101.52 ;
    END
  END sink_select[38]
  PIN sink_select[39]
    DIRECTION INPUT ;
    USE SIGNAL ;
    PORT
      LAYER M5 ;
        RECT  16.32 101.436 16.344 101.52 ;
    END
  END sink_select[39]
  PIN sink_select[3]
    DIRECTION INPUT ;
    USE SIGNAL ;
    PORT
      LAYER M5 ;
        RECT  7.296 101.436 7.32 101.52 ;
    END
  END sink_select[3]
  PIN sink_select[40]
    DIRECTION INPUT ;
    USE SIGNAL ;
    PORT
      LAYER M5 ;
        RECT  16.56 101.436 16.584 101.52 ;
    END
  END sink_select[40]
  PIN sink_select[41]
    DIRECTION INPUT ;
    USE SIGNAL ;
    PORT
      LAYER M5 ;
        RECT  16.8 101.436 16.824 101.52 ;
    END
  END sink_select[41]
  PIN sink_select[42]
    DIRECTION INPUT ;
    USE SIGNAL ;
    PORT
      LAYER M5 ;
        RECT  17.04 101.436 17.064 101.52 ;
    END
  END sink_select[42]
  PIN sink_select[43]
    DIRECTION INPUT ;
    USE SIGNAL ;
    PORT
      LAYER M5 ;
        RECT  17.328 101.436 17.352 101.52 ;
    END
  END sink_select[43]
  PIN sink_select[44]
    DIRECTION INPUT ;
    USE SIGNAL ;
    PORT
      LAYER M5 ;
        RECT  17.568 101.436 17.592 101.52 ;
    END
  END sink_select[44]
  PIN sink_select[45]
    DIRECTION INPUT ;
    USE SIGNAL ;
    PORT
      LAYER M5 ;
        RECT  17.808 101.436 17.832 101.52 ;
    END
  END sink_select[45]
  PIN sink_select[46]
    DIRECTION INPUT ;
    USE SIGNAL ;
    PORT
      LAYER M5 ;
        RECT  18.048 101.436 18.072 101.52 ;
    END
  END sink_select[46]
  PIN sink_select[47]
    DIRECTION INPUT ;
    USE SIGNAL ;
    PORT
      LAYER M5 ;
        RECT  18.336 101.436 18.36 101.52 ;
    END
  END sink_select[47]
  PIN sink_select[48]
    DIRECTION INPUT ;
    USE SIGNAL ;
    PORT
      LAYER M5 ;
        RECT  18.576 101.436 18.6 101.52 ;
    END
  END sink_select[48]
  PIN sink_select[49]
    DIRECTION INPUT ;
    USE SIGNAL ;
    PORT
      LAYER M5 ;
        RECT  18.816 101.436 18.84 101.52 ;
    END
  END sink_select[49]
  PIN sink_select[4]
    DIRECTION INPUT ;
    USE SIGNAL ;
    PORT
      LAYER M5 ;
        RECT  7.584 101.436 7.608 101.52 ;
    END
  END sink_select[4]
  PIN sink_select[50]
    DIRECTION INPUT ;
    USE SIGNAL ;
    PORT
      LAYER M5 ;
        RECT  19.056 101.436 19.08 101.52 ;
    END
  END sink_select[50]
  PIN sink_select[51]
    DIRECTION INPUT ;
    USE SIGNAL ;
    PORT
      LAYER M5 ;
        RECT  19.296 101.436 19.32 101.52 ;
    END
  END sink_select[51]
  PIN sink_select[52]
    DIRECTION INPUT ;
    USE SIGNAL ;
    PORT
      LAYER M5 ;
        RECT  19.584 101.436 19.608 101.52 ;
    END
  END sink_select[52]
  PIN sink_select[53]
    DIRECTION INPUT ;
    USE SIGNAL ;
    PORT
      LAYER M5 ;
        RECT  19.824 101.436 19.848 101.52 ;
    END
  END sink_select[53]
  PIN sink_select[54]
    DIRECTION INPUT ;
    USE SIGNAL ;
    PORT
      LAYER M5 ;
        RECT  20.064 101.436 20.088 101.52 ;
    END
  END sink_select[54]
  PIN sink_select[55]
    DIRECTION INPUT ;
    USE SIGNAL ;
    PORT
      LAYER M5 ;
        RECT  20.304 101.436 20.328 101.52 ;
    END
  END sink_select[55]
  PIN sink_select[56]
    DIRECTION INPUT ;
    USE SIGNAL ;
    PORT
      LAYER M5 ;
        RECT  20.544 101.436 20.568 101.52 ;
    END
  END sink_select[56]
  PIN sink_select[57]
    DIRECTION INPUT ;
    USE SIGNAL ;
    PORT
      LAYER M5 ;
        RECT  20.832 101.436 20.856 101.52 ;
    END
  END sink_select[57]
  PIN sink_select[58]
    DIRECTION INPUT ;
    USE SIGNAL ;
    PORT
      LAYER M5 ;
        RECT  21.072 101.436 21.096 101.52 ;
    END
  END sink_select[58]
  PIN sink_select[59]
    DIRECTION INPUT ;
    USE SIGNAL ;
    PORT
      LAYER M5 ;
        RECT  21.312 101.436 21.336 101.52 ;
    END
  END sink_select[59]
  PIN sink_select[5]
    DIRECTION INPUT ;
    USE SIGNAL ;
    PORT
      LAYER M5 ;
        RECT  7.824 101.436 7.848 101.52 ;
    END
  END sink_select[5]
  PIN sink_select[6]
    DIRECTION INPUT ;
    USE SIGNAL ;
    PORT
      LAYER M5 ;
        RECT  8.064 101.436 8.088 101.52 ;
    END
  END sink_select[6]
  PIN sink_select[7]
    DIRECTION INPUT ;
    USE SIGNAL ;
    PORT
      LAYER M5 ;
        RECT  8.304 101.436 8.328 101.52 ;
    END
  END sink_select[7]
  PIN sink_select[8]
    DIRECTION INPUT ;
    USE SIGNAL ;
    PORT
      LAYER M5 ;
        RECT  8.544 101.436 8.568 101.52 ;
    END
  END sink_select[8]
  PIN sink_select[9]
    DIRECTION INPUT ;
    USE SIGNAL ;
    PORT
      LAYER M5 ;
        RECT  8.832 101.436 8.856 101.52 ;
    END
  END sink_select[9]
  PIN sink_slot[0]
    DIRECTION INPUT ;
    USE SIGNAL ;
    PORT
      LAYER M5 ;
        RECT  2.592 101.436 2.616 101.52 ;
    END
  END sink_slot[0]
  PIN sink_slot[10]
    DIRECTION INPUT ;
    USE SIGNAL ;
    PORT
      LAYER M5 ;
        RECT  5.136 101.436 5.16 101.52 ;
    END
  END sink_slot[10]
  PIN sink_slot[11]
    DIRECTION INPUT ;
    USE SIGNAL ;
    PORT
      LAYER M5 ;
        RECT  5.376 101.436 5.4 101.52 ;
    END
  END sink_slot[11]
  PIN sink_slot[12]
    DIRECTION INPUT ;
    USE SIGNAL ;
    PORT
      LAYER M5 ;
        RECT  5.616 101.436 5.64 101.52 ;
    END
  END sink_slot[12]
  PIN sink_slot[13]
    DIRECTION INPUT ;
    USE SIGNAL ;
    PORT
      LAYER M5 ;
        RECT  5.856 101.436 5.88 101.52 ;
    END
  END sink_slot[13]
  PIN sink_slot[14]
    DIRECTION INPUT ;
    USE SIGNAL ;
    PORT
      LAYER M5 ;
        RECT  6.096 101.436 6.12 101.52 ;
    END
  END sink_slot[14]
  PIN sink_slot[1]
    DIRECTION INPUT ;
    USE SIGNAL ;
    PORT
      LAYER M5 ;
        RECT  2.88 101.436 2.904 101.52 ;
    END
  END sink_slot[1]
  PIN sink_slot[2]
    DIRECTION INPUT ;
    USE SIGNAL ;
    PORT
      LAYER M5 ;
        RECT  3.12 101.436 3.144 101.52 ;
    END
  END sink_slot[2]
  PIN sink_slot[3]
    DIRECTION INPUT ;
    USE SIGNAL ;
    PORT
      LAYER M5 ;
        RECT  3.36 101.436 3.384 101.52 ;
    END
  END sink_slot[3]
  PIN sink_slot[4]
    DIRECTION INPUT ;
    USE SIGNAL ;
    PORT
      LAYER M5 ;
        RECT  3.6 101.436 3.624 101.52 ;
    END
  END sink_slot[4]
  PIN sink_slot[5]
    DIRECTION INPUT ;
    USE SIGNAL ;
    PORT
      LAYER M5 ;
        RECT  3.84 101.436 3.864 101.52 ;
    END
  END sink_slot[5]
  PIN sink_slot[6]
    DIRECTION INPUT ;
    USE SIGNAL ;
    PORT
      LAYER M5 ;
        RECT  4.128 101.436 4.152 101.52 ;
    END
  END sink_slot[6]
  PIN sink_slot[7]
    DIRECTION INPUT ;
    USE SIGNAL ;
    PORT
      LAYER M5 ;
        RECT  4.368 101.436 4.392 101.52 ;
    END
  END sink_slot[7]
  PIN sink_slot[8]
    DIRECTION INPUT ;
    USE SIGNAL ;
    PORT
      LAYER M5 ;
        RECT  4.608 101.436 4.632 101.52 ;
    END
  END sink_slot[8]
  PIN sink_slot[9]
    DIRECTION INPUT ;
    USE SIGNAL ;
    PORT
      LAYER M5 ;
        RECT  4.848 101.436 4.872 101.52 ;
    END
  END sink_slot[9]
  PIN unavailable_fault
    DIRECTION OUTPUT ;
    USE SIGNAL ;
    PORT
      LAYER M5 ;
        RECT  23.28 101.436 23.304 101.52 ;
    END
  END unavailable_fault
  PIN VDD
    DIRECTION INOUT ;
    USE POWER ;
    PORT
      LAYER M5 ;
        RECT  18.792 2.151 18.912 99.369 ;
        RECT  13.392 2.151 13.512 99.369 ;
        RECT  7.992 2.151 8.112 99.369 ;
        RECT  2.592 2.151 2.712 99.369 ;
    END
  END VDD
  PIN VSS
    DIRECTION INOUT ;
    USE GROUND ;
    PORT
      LAYER M5 ;
        RECT  18.6 2.137 18.72 99.383 ;
        RECT  13.2 2.137 13.32 99.383 ;
        RECT  7.8 2.137 7.92 99.383 ;
        RECT  2.4 2.137 2.52 99.383 ;
    END
  END VSS
  # OT_OBS_CLOSED layer=M5 d_um=1.536 added=54
  OBS
    LAYER RVTN ;
     RECT  2.16 2.16 21.6 2.295 ;
     RECT  2.16 2.565 21.6 2.835 ;
     RECT  2.16 3.105 21.6 3.375 ;
     RECT  2.16 3.645 21.6 3.915 ;
     RECT  2.16 4.185 21.6 4.455 ;
     RECT  2.16 4.725 21.6 4.995 ;
     RECT  2.16 5.265 21.6 5.535 ;
     RECT  2.16 5.805 21.6 6.075 ;
     RECT  2.16 6.345 21.6 6.615 ;
     RECT  2.16 6.885 21.6 7.155 ;
     RECT  2.16 7.425 21.6 7.695 ;
     RECT  2.16 7.965 21.6 8.235 ;
     RECT  2.16 8.505 21.6 8.775 ;
     RECT  2.16 9.045 21.6 9.315 ;
     RECT  2.16 9.585 21.6 9.855 ;
     RECT  2.16 10.125 21.6 10.395 ;
     RECT  2.16 10.665 21.6 10.935 ;
     RECT  2.16 11.205 21.6 11.475 ;
     RECT  2.16 11.745 21.6 12.015 ;
     RECT  2.16 12.285 21.6 12.555 ;
     RECT  2.16 12.825 21.6 13.095 ;
     RECT  2.16 13.365 21.6 13.635 ;
     RECT  2.16 13.905 21.6 14.175 ;
     RECT  2.16 14.445 21.6 14.715 ;
     RECT  2.16 14.985 21.6 15.255 ;
     RECT  2.16 15.525 21.6 15.795 ;
     RECT  2.16 16.065 21.6 16.335 ;
     RECT  2.16 16.605 21.6 16.875 ;
     RECT  2.16 17.145 21.6 17.415 ;
     RECT  2.16 17.685 21.6 17.955 ;
     RECT  2.16 18.225 21.6 18.495 ;
     RECT  2.16 18.765 21.6 19.035 ;
     RECT  2.16 19.305 21.6 19.575 ;
     RECT  2.16 19.845 21.6 20.115 ;
     RECT  2.16 20.385 21.6 20.655 ;
     RECT  2.16 20.925 21.6 21.195 ;
     RECT  2.16 21.465 21.6 21.735 ;
     RECT  2.16 22.005 21.6 22.275 ;
     RECT  2.16 22.545 21.6 22.815 ;
     RECT  2.16 23.085 21.6 23.355 ;
     RECT  2.16 23.625 21.6 23.895 ;
     RECT  2.16 24.165 21.6 24.435 ;
     RECT  2.16 24.705 21.6 24.975 ;
     RECT  2.16 25.245 21.6 25.515 ;
     RECT  2.16 25.785 21.6 26.055 ;
     RECT  2.16 26.325 21.6 26.595 ;
     RECT  2.16 26.865 21.6 27.135 ;
     RECT  2.16 27.405 21.6 27.675 ;
     RECT  2.16 27.945 21.6 28.215 ;
     RECT  2.16 28.485 21.6 28.755 ;
     RECT  2.16 29.025 21.6 29.295 ;
     RECT  2.16 29.565 21.6 29.835 ;
     RECT  2.16 30.105 21.6 30.375 ;
     RECT  2.16 30.645 21.6 30.915 ;
     RECT  2.16 31.185 21.6 31.455 ;
     RECT  2.16 31.725 21.6 31.995 ;
     RECT  2.16 32.265 21.6 32.535 ;
     RECT  2.16 32.805 21.6 33.075 ;
     RECT  2.16 33.345 21.6 33.615 ;
     RECT  2.16 33.885 21.6 34.155 ;
     RECT  2.16 34.425 21.6 34.695 ;
     RECT  2.16 34.965 21.6 35.235 ;
     RECT  2.16 35.505 21.6 35.775 ;
     RECT  2.16 36.045 21.6 36.315 ;
     RECT  2.16 36.585 21.6 36.855 ;
     RECT  2.16 37.125 21.6 37.395 ;
     RECT  2.16 37.665 21.6 37.935 ;
     RECT  2.16 38.205 21.6 38.475 ;
     RECT  2.16 38.745 21.6 39.015 ;
     RECT  2.16 39.285 21.6 39.555 ;
     RECT  2.16 39.825 21.6 40.095 ;
     RECT  2.16 40.365 21.6 40.635 ;
     RECT  2.16 40.905 21.6 41.175 ;
     RECT  2.16 41.445 21.6 41.715 ;
     RECT  2.16 41.985 21.6 42.255 ;
     RECT  2.16 42.525 21.6 42.795 ;
     RECT  2.16 43.065 21.6 43.335 ;
     RECT  2.16 43.605 21.6 43.875 ;
     RECT  2.16 44.145 21.6 44.415 ;
     RECT  2.16 44.685 21.6 44.955 ;
     RECT  2.16 45.225 21.6 45.495 ;
     RECT  2.16 45.765 21.6 46.035 ;
     RECT  2.16 46.305 21.6 46.575 ;
     RECT  2.16 46.845 21.6 47.115 ;
     RECT  2.16 47.385 21.6 47.655 ;
     RECT  2.16 47.925 21.6 48.195 ;
     RECT  2.16 48.465 21.6 48.735 ;
     RECT  2.16 49.005 21.6 49.275 ;
     RECT  2.16 49.545 21.6 49.815 ;
     RECT  2.16 50.085 21.6 50.355 ;
     RECT  2.16 50.625 21.6 50.895 ;
     RECT  2.16 51.165 21.6 51.435 ;
     RECT  2.16 51.705 21.6 51.975 ;
     RECT  2.16 52.245 21.6 52.515 ;
     RECT  2.16 52.785 21.6 53.055 ;
     RECT  2.16 53.325 21.6 53.595 ;
     RECT  2.16 53.865 21.6 54.135 ;
     RECT  2.16 54.405 21.6 54.675 ;
     RECT  2.16 54.945 21.6 55.215 ;
     RECT  2.16 55.485 21.6 55.755 ;
     RECT  2.16 56.025 21.6 56.295 ;
     RECT  2.16 56.565 21.6 56.835 ;
     RECT  2.16 57.105 21.6 57.375 ;
     RECT  2.16 57.645 21.6 57.915 ;
     RECT  2.16 58.185 21.6 58.455 ;
     RECT  2.16 58.725 21.6 58.995 ;
     RECT  2.16 59.265 21.6 59.535 ;
     RECT  2.16 59.805 21.6 60.075 ;
     RECT  2.16 60.345 21.6 60.615 ;
     RECT  2.16 60.885 21.6 61.155 ;
     RECT  2.16 61.425 21.6 61.695 ;
     RECT  2.16 61.965 21.6 62.235 ;
     RECT  2.16 62.505 21.6 62.775 ;
     RECT  2.16 63.045 21.6 63.315 ;
     RECT  2.16 63.585 21.6 63.855 ;
     RECT  2.16 64.125 21.6 64.395 ;
     RECT  2.16 64.665 21.6 64.935 ;
     RECT  2.16 65.205 21.6 65.475 ;
     RECT  2.16 65.745 21.6 66.015 ;
     RECT  2.16 66.285 21.6 66.555 ;
     RECT  2.16 66.825 21.6 67.095 ;
     RECT  2.16 67.365 21.6 67.635 ;
     RECT  2.16 67.905 21.6 68.175 ;
     RECT  2.16 68.445 21.6 68.715 ;
     RECT  2.16 68.985 21.6 69.255 ;
     RECT  2.16 69.525 21.6 69.795 ;
     RECT  2.16 70.065 21.6 70.335 ;
     RECT  2.16 70.605 21.6 70.875 ;
     RECT  2.16 71.145 21.6 71.415 ;
     RECT  2.16 71.685 21.6 71.955 ;
     RECT  2.16 72.225 21.6 72.495 ;
     RECT  2.16 72.765 21.6 73.035 ;
     RECT  2.16 73.305 21.6 73.575 ;
     RECT  2.16 73.845 21.6 74.115 ;
     RECT  2.16 74.385 21.6 74.655 ;
     RECT  2.16 74.925 21.6 75.195 ;
     RECT  2.16 75.465 21.6 75.735 ;
     RECT  2.16 76.005 21.6 76.275 ;
     RECT  2.16 76.545 21.6 76.815 ;
     RECT  2.16 77.085 21.6 77.355 ;
     RECT  2.16 77.625 21.6 77.895 ;
     RECT  2.16 78.165 21.6 78.435 ;
     RECT  2.16 78.705 21.6 78.975 ;
     RECT  2.16 79.245 21.6 79.515 ;
     RECT  2.16 79.785 21.6 80.055 ;
     RECT  2.16 80.325 21.6 80.595 ;
     RECT  2.16 80.865 21.6 81.135 ;
     RECT  2.16 81.405 21.6 81.675 ;
     RECT  2.16 81.945 21.6 82.215 ;
     RECT  2.16 82.485 21.6 82.755 ;
     RECT  2.16 83.025 21.6 83.295 ;
     RECT  2.16 83.565 21.6 83.835 ;
     RECT  2.16 84.105 21.6 84.375 ;
     RECT  2.16 84.645 21.6 84.915 ;
     RECT  2.16 85.185 21.6 85.455 ;
     RECT  2.16 85.725 21.6 85.995 ;
     RECT  2.16 86.265 21.6 86.535 ;
     RECT  2.16 86.805 21.6 87.075 ;
     RECT  2.16 87.345 21.6 87.615 ;
     RECT  2.16 87.885 21.6 88.155 ;
     RECT  2.16 88.425 21.6 88.695 ;
     RECT  2.16 88.965 21.6 89.235 ;
     RECT  2.16 89.505 21.6 89.775 ;
     RECT  2.16 90.045 21.6 90.315 ;
     RECT  2.16 90.585 21.6 90.855 ;
     RECT  2.16 91.125 21.6 91.395 ;
     RECT  2.16 91.665 21.6 91.935 ;
     RECT  2.16 92.205 21.6 92.475 ;
     RECT  2.16 92.745 21.6 93.015 ;
     RECT  2.16 93.285 21.6 93.555 ;
     RECT  2.16 93.825 21.6 94.095 ;
     RECT  2.16 94.365 21.6 94.635 ;
     RECT  2.16 94.905 21.6 95.175 ;
     RECT  2.16 95.445 21.6 95.715 ;
     RECT  2.16 95.985 21.6 96.255 ;
     RECT  2.16 96.525 21.6 96.795 ;
     RECT  2.16 97.065 21.6 97.335 ;
     RECT  2.16 97.605 21.6 97.875 ;
     RECT  2.16 98.145 21.6 98.415 ;
     RECT  2.16 98.685 21.6 98.955 ;
     RECT  2.16 99.225 21.6 99.36 ;
    LAYER RVTP ;
     RECT  2.16 2.295 21.6 2.565 ;
     RECT  2.16 2.835 21.6 3.105 ;
     RECT  2.16 3.375 21.6 3.645 ;
     RECT  2.16 3.915 21.6 4.185 ;
     RECT  2.16 4.455 21.6 4.725 ;
     RECT  2.16 4.995 21.6 5.265 ;
     RECT  2.16 5.535 21.6 5.805 ;
     RECT  2.16 6.075 21.6 6.345 ;
     RECT  2.16 6.615 21.6 6.885 ;
     RECT  2.16 7.155 21.6 7.425 ;
     RECT  2.16 7.695 21.6 7.965 ;
     RECT  2.16 8.235 21.6 8.505 ;
     RECT  2.16 8.775 21.6 9.045 ;
     RECT  2.16 9.315 21.6 9.585 ;
     RECT  2.16 9.855 21.6 10.125 ;
     RECT  2.16 10.395 21.6 10.665 ;
     RECT  2.16 10.935 21.6 11.205 ;
     RECT  2.16 11.475 21.6 11.745 ;
     RECT  2.16 12.015 21.6 12.285 ;
     RECT  2.16 12.555 21.6 12.825 ;
     RECT  2.16 13.095 21.6 13.365 ;
     RECT  2.16 13.635 21.6 13.905 ;
     RECT  2.16 14.175 21.6 14.445 ;
     RECT  2.16 14.715 21.6 14.985 ;
     RECT  2.16 15.255 21.6 15.525 ;
     RECT  2.16 15.795 21.6 16.065 ;
     RECT  2.16 16.335 21.6 16.605 ;
     RECT  2.16 16.875 21.6 17.145 ;
     RECT  2.16 17.415 21.6 17.685 ;
     RECT  2.16 17.955 21.6 18.225 ;
     RECT  2.16 18.495 21.6 18.765 ;
     RECT  2.16 19.035 21.6 19.305 ;
     RECT  2.16 19.575 21.6 19.845 ;
     RECT  2.16 20.115 21.6 20.385 ;
     RECT  2.16 20.655 21.6 20.925 ;
     RECT  2.16 21.195 21.6 21.465 ;
     RECT  2.16 21.735 21.6 22.005 ;
     RECT  2.16 22.275 21.6 22.545 ;
     RECT  2.16 22.815 21.6 23.085 ;
     RECT  2.16 23.355 21.6 23.625 ;
     RECT  2.16 23.895 21.6 24.165 ;
     RECT  2.16 24.435 21.6 24.705 ;
     RECT  2.16 24.975 21.6 25.245 ;
     RECT  2.16 25.515 21.6 25.785 ;
     RECT  2.16 26.055 21.6 26.325 ;
     RECT  2.16 26.595 21.6 26.865 ;
     RECT  2.16 27.135 21.6 27.405 ;
     RECT  2.16 27.675 21.6 27.945 ;
     RECT  2.16 28.215 21.6 28.485 ;
     RECT  2.16 28.755 21.6 29.025 ;
     RECT  2.16 29.295 21.6 29.565 ;
     RECT  2.16 29.835 21.6 30.105 ;
     RECT  2.16 30.375 21.6 30.645 ;
     RECT  2.16 30.915 21.6 31.185 ;
     RECT  2.16 31.455 21.6 31.725 ;
     RECT  2.16 31.995 21.6 32.265 ;
     RECT  2.16 32.535 21.6 32.805 ;
     RECT  2.16 33.075 21.6 33.345 ;
     RECT  2.16 33.615 21.6 33.885 ;
     RECT  2.16 34.155 21.6 34.425 ;
     RECT  2.16 34.695 21.6 34.965 ;
     RECT  2.16 35.235 21.6 35.505 ;
     RECT  2.16 35.775 21.6 36.045 ;
     RECT  2.16 36.315 21.6 36.585 ;
     RECT  2.16 36.855 21.6 37.125 ;
     RECT  2.16 37.395 21.6 37.665 ;
     RECT  2.16 37.935 21.6 38.205 ;
     RECT  2.16 38.475 21.6 38.745 ;
     RECT  2.16 39.015 21.6 39.285 ;
     RECT  2.16 39.555 21.6 39.825 ;
     RECT  2.16 40.095 21.6 40.365 ;
     RECT  2.16 40.635 21.6 40.905 ;
     RECT  2.16 41.175 21.6 41.445 ;
     RECT  2.16 41.715 21.6 41.985 ;
     RECT  2.16 42.255 21.6 42.525 ;
     RECT  2.16 42.795 21.6 43.065 ;
     RECT  2.16 43.335 21.6 43.605 ;
     RECT  2.16 43.875 21.6 44.145 ;
     RECT  2.16 44.415 21.6 44.685 ;
     RECT  2.16 44.955 21.6 45.225 ;
     RECT  2.16 45.495 21.6 45.765 ;
     RECT  2.16 46.035 21.6 46.305 ;
     RECT  2.16 46.575 21.6 46.845 ;
     RECT  2.16 47.115 21.6 47.385 ;
     RECT  2.16 47.655 21.6 47.925 ;
     RECT  2.16 48.195 21.6 48.465 ;
     RECT  2.16 48.735 21.6 49.005 ;
     RECT  2.16 49.275 21.6 49.545 ;
     RECT  2.16 49.815 21.6 50.085 ;
     RECT  2.16 50.355 21.6 50.625 ;
     RECT  2.16 50.895 21.6 51.165 ;
     RECT  2.16 51.435 21.6 51.705 ;
     RECT  2.16 51.975 21.6 52.245 ;
     RECT  2.16 52.515 21.6 52.785 ;
     RECT  2.16 53.055 21.6 53.325 ;
     RECT  2.16 53.595 21.6 53.865 ;
     RECT  2.16 54.135 21.6 54.405 ;
     RECT  2.16 54.675 21.6 54.945 ;
     RECT  2.16 55.215 21.6 55.485 ;
     RECT  2.16 55.755 21.6 56.025 ;
     RECT  2.16 56.295 21.6 56.565 ;
     RECT  2.16 56.835 21.6 57.105 ;
     RECT  2.16 57.375 21.6 57.645 ;
     RECT  2.16 57.915 21.6 58.185 ;
     RECT  2.16 58.455 21.6 58.725 ;
     RECT  2.16 58.995 21.6 59.265 ;
     RECT  2.16 59.535 21.6 59.805 ;
     RECT  2.16 60.075 21.6 60.345 ;
     RECT  2.16 60.615 21.6 60.885 ;
     RECT  2.16 61.155 21.6 61.425 ;
     RECT  2.16 61.695 21.6 61.965 ;
     RECT  2.16 62.235 21.6 62.505 ;
     RECT  2.16 62.775 21.6 63.045 ;
     RECT  2.16 63.315 21.6 63.585 ;
     RECT  2.16 63.855 21.6 64.125 ;
     RECT  2.16 64.395 21.6 64.665 ;
     RECT  2.16 64.935 21.6 65.205 ;
     RECT  2.16 65.475 21.6 65.745 ;
     RECT  2.16 66.015 21.6 66.285 ;
     RECT  2.16 66.555 21.6 66.825 ;
     RECT  2.16 67.095 21.6 67.365 ;
     RECT  2.16 67.635 21.6 67.905 ;
     RECT  2.16 68.175 21.6 68.445 ;
     RECT  2.16 68.715 21.6 68.985 ;
     RECT  2.16 69.255 21.6 69.525 ;
     RECT  2.16 69.795 21.6 70.065 ;
     RECT  2.16 70.335 21.6 70.605 ;
     RECT  2.16 70.875 21.6 71.145 ;
     RECT  2.16 71.415 21.6 71.685 ;
     RECT  2.16 71.955 21.6 72.225 ;
     RECT  2.16 72.495 21.6 72.765 ;
     RECT  2.16 73.035 21.6 73.305 ;
     RECT  2.16 73.575 21.6 73.845 ;
     RECT  2.16 74.115 21.6 74.385 ;
     RECT  2.16 74.655 21.6 74.925 ;
     RECT  2.16 75.195 21.6 75.465 ;
     RECT  2.16 75.735 21.6 76.005 ;
     RECT  2.16 76.275 21.6 76.545 ;
     RECT  2.16 76.815 21.6 77.085 ;
     RECT  2.16 77.355 21.6 77.625 ;
     RECT  2.16 77.895 21.6 78.165 ;
     RECT  2.16 78.435 21.6 78.705 ;
     RECT  2.16 78.975 21.6 79.245 ;
     RECT  2.16 79.515 21.6 79.785 ;
     RECT  2.16 80.055 21.6 80.325 ;
     RECT  2.16 80.595 21.6 80.865 ;
     RECT  2.16 81.135 21.6 81.405 ;
     RECT  2.16 81.675 21.6 81.945 ;
     RECT  2.16 82.215 21.6 82.485 ;
     RECT  2.16 82.755 21.6 83.025 ;
     RECT  2.16 83.295 21.6 83.565 ;
     RECT  2.16 83.835 21.6 84.105 ;
     RECT  2.16 84.375 21.6 84.645 ;
     RECT  2.16 84.915 21.6 85.185 ;
     RECT  2.16 85.455 21.6 85.725 ;
     RECT  2.16 85.995 21.6 86.265 ;
     RECT  2.16 86.535 21.6 86.805 ;
     RECT  2.16 87.075 21.6 87.345 ;
     RECT  2.16 87.615 21.6 87.885 ;
     RECT  2.16 88.155 21.6 88.425 ;
     RECT  2.16 88.695 21.6 88.965 ;
     RECT  2.16 89.235 21.6 89.505 ;
     RECT  2.16 89.775 21.6 90.045 ;
     RECT  2.16 90.315 21.6 90.585 ;
     RECT  2.16 90.855 21.6 91.125 ;
     RECT  2.16 91.395 21.6 91.665 ;
     RECT  2.16 91.935 21.6 92.205 ;
     RECT  2.16 92.475 21.6 92.745 ;
     RECT  2.16 93.015 21.6 93.285 ;
     RECT  2.16 93.555 21.6 93.825 ;
     RECT  2.16 94.095 21.6 94.365 ;
     RECT  2.16 94.635 21.6 94.905 ;
     RECT  2.16 95.175 21.6 95.445 ;
     RECT  2.16 95.715 21.6 95.985 ;
     RECT  2.16 96.255 21.6 96.525 ;
     RECT  2.16 96.795 21.6 97.065 ;
     RECT  2.16 97.335 21.6 97.605 ;
     RECT  2.16 97.875 21.6 98.145 ;
     RECT  2.16 98.415 21.6 98.685 ;
     RECT  2.16 98.955 21.6 99.225 ;
    LAYER M1 ;
     RECT  2.16 2.151 21.6 99.369 ;
    LAYER M2 ;
     RECT  0.103 41.382 0.139 42.21 ;
     RECT  0.103 43.002 0.139 43.56 ;
     RECT  0.103 46.512 0.139 48.15 ;
     RECT  0.103 48.942 0.139 50.85 ;
     RECT  0.103 61.362 0.139 61.38 ;
     RECT  0.103 62.442 0.139 62.73 ;
     RECT  0.103 58.662 0.247 59.49 ;
     RECT  0.139 61.362 0.247 62.73 ;
     RECT  0.139 63.63 0.247 63.648 ;
     RECT  0.139 46.512 0.283 50.85 ;
     RECT  0.283 79.29 0.319 79.308 ;
     RECT  0.319 79.056 0.355 79.308 ;
     RECT  0.103 93.528 0.499 93.546 ;
     RECT  0.103 18.198 0.535 18.216 ;
     RECT  0.247 58.662 0.715 60.102 ;
     RECT  0.247 61.362 0.787 63.648 ;
     RECT  0.103 38.718 0.895 38.736 ;
     RECT  0.535 90.396 0.895 90.414 ;
     RECT  0.427 32.04 0.931 32.058 ;
     RECT  0.427 89.046 0.931 89.064 ;
     RECT  0.823 85.536 0.967 85.554 ;
     RECT  0.499 92.79 1.003 93.546 ;
     RECT  0.499 27.216 1.039 27.234 ;
     RECT  0.103 25.02 1.075 25.038 ;
     RECT  1.003 92.484 1.075 93.546 ;
     RECT  0.931 88.506 1.111 89.064 ;
     RECT  0.103 54.072 1.147 54.63 ;
     RECT  0.931 31.536 1.327 32.058 ;
     RECT  1.147 53.802 1.363 54.63 ;
     RECT  0.895 89.856 1.363 90.414 ;
     RECT  0.103 91.17 1.363 91.188 ;
     RECT  1.327 31.536 1.399 32.094 ;
     RECT  0.283 46.314 1.399 50.85 ;
     RECT  1.363 57.726 1.399 57.744 ;
     RECT  1.363 89.856 1.399 91.188 ;
     RECT  1.075 92.016 1.399 93.546 ;
     RECT  0.859 40.374 1.507 40.392 ;
     RECT  0.967 85.536 1.543 86.292 ;
     RECT  0.967 29.34 1.579 29.358 ;
     RECT  0.103 22.752 1.615 22.77 ;
     RECT  0.103 83.772 1.615 84.366 ;
     RECT  1.615 22.752 1.651 23.184 ;
     RECT  1.111 88.236 1.651 89.064 ;
     RECT  1.399 89.856 1.651 93.546 ;
     RECT  0.103 44.622 1.759 45.45 ;
     RECT  1.399 46.314 1.759 50.958 ;
     RECT  1.399 57.726 1.759 57.834 ;
     RECT  1.363 53.802 1.795 55.008 ;
     RECT  1.795 53.802 1.831 55.044 ;
     RECT  1.759 57.618 1.939 57.834 ;
     RECT  0.787 61.362 1.975 64.116 ;
     RECT  1.939 57.348 2.047 57.834 ;
     RECT  1.543 85.5 2.047 86.292 ;
     RECT  1.867 87.156 2.047 87.174 ;
     RECT  0.895 38.718 2.083 39.276 ;
     RECT  2.047 57.186 2.119 57.834 ;
     RECT  2.083 38.718 2.155 39.312 ;
     RECT  0.103 2.808 2.16 2.826 ;
     RECT  0.103 6.822 2.16 6.84 ;
     RECT  2.047 9.792 2.16 9.81 ;
     RECT  0.103 13.068 2.16 13.086 ;
     RECT  1.111 16.614 2.16 16.632 ;
     RECT  0.535 17.766 2.16 18.216 ;
     RECT  1.687 19.35 2.16 19.368 ;
     RECT  1.651 22.59 2.16 23.184 ;
     RECT  1.075 24.48 2.16 25.038 ;
     RECT  1.543 26.334 2.16 26.352 ;
     RECT  1.039 27.216 2.16 27.504 ;
     RECT  1.579 28.836 2.16 29.358 ;
     RECT  1.399 30.996 2.16 32.094 ;
     RECT  2.155 35.046 2.16 35.064 ;
     RECT  0.103 35.82 2.16 35.838 ;
     RECT  1.363 36.666 2.16 36.684 ;
     RECT  2.011 37.908 2.16 37.926 ;
     RECT  2.155 38.682 2.16 39.312 ;
     RECT  1.507 40.104 2.16 40.392 ;
     RECT  0.139 41.382 2.16 43.56 ;
     RECT  1.759 44.622 2.16 50.958 ;
     RECT  2.083 52.524 2.16 52.542 ;
     RECT  1.831 53.604 2.16 55.044 ;
     RECT  0.103 56.34 2.16 56.358 ;
     RECT  2.119 57.15 2.16 57.834 ;
     RECT  0.715 58.662 2.16 60.444 ;
     RECT  1.975 61.236 2.16 64.116 ;
     RECT  0.103 66.06 2.16 66.078 ;
     RECT  1.975 67.176 2.16 67.194 ;
     RECT  0.787 68.796 2.16 68.814 ;
     RECT  0.103 70.002 2.16 70.02 ;
     RECT  0.103 74.592 2.16 74.61 ;
     RECT  0.355 79.056 2.16 79.776 ;
     RECT  0.391 80.946 2.16 80.964 ;
     RECT  0.787 82.422 2.16 82.44 ;
     RECT  1.615 83.574 2.16 84.366 ;
     RECT  2.047 85.5 2.16 87.174 ;
     RECT  1.651 88.236 2.16 93.546 ;
     RECT  0.103 96.57 2.16 96.588 ;
     RECT  2.16 2.151 5.431 99.369 ;
     RECT  5.431 2.034 13.163 99.369 ;
     RECT  13.163 2.106 14.747 99.369 ;
     RECT  14.747 2.151 21.6 99.369 ;
     RECT  21.6 25.794 21.659 30.024 ;
     RECT  21.6 53.874 21.659 65.124 ;
     RECT  21.6 66.096 21.659 91.764 ;
     RECT  21.6 92.556 21.659 98.91 ;
     RECT  21.6 18.198 21.695 21.654 ;
     RECT  21.659 66.096 21.695 77.544 ;
     RECT  21.6 2.466 21.731 11.844 ;
     RECT  21.6 22.446 21.731 24.732 ;
     RECT  21.6 36.936 21.767 52.974 ;
     RECT  21.731 2.466 21.839 7.218 ;
     RECT  21.731 24.714 21.875 24.732 ;
     RECT  21.659 26.028 21.875 30.024 ;
     RECT  21.767 44.694 21.911 52.974 ;
     RECT  21.659 54.216 21.911 65.124 ;
     RECT  21.659 78.408 21.911 91.764 ;
     RECT  21.659 96.876 21.911 98.91 ;
     RECT  21.6 12.798 21.947 17.442 ;
     RECT  21.911 54.216 21.947 59.184 ;
     RECT  21.911 78.48 21.947 91.764 ;
     RECT  21.947 78.48 21.983 84.204 ;
     RECT  21.695 66.096 22.019 70.974 ;
     RECT  21.911 60.156 22.055 65.124 ;
     RECT  21.983 78.561 22.055 84.204 ;
     RECT  22.019 66.186 22.091 70.974 ;
     RECT  21.911 44.694 22.199 50.994 ;
     RECT  21.839 5.076 22.235 7.218 ;
     RECT  21.947 15.264 22.235 17.442 ;
     RECT  21.731 22.446 22.235 23.724 ;
     RECT  22.199 44.694 22.235 50.958 ;
     RECT  21.947 54.216 22.235 58.014 ;
     RECT  22.091 66.186 22.235 67.392 ;
     RECT  22.091 68.22 22.235 70.974 ;
     RECT  22.055 78.606 22.235 84.204 ;
     RECT  21.659 92.556 22.235 96.048 ;
     RECT  21.839 2.466 22.271 4.284 ;
     RECT  22.235 5.076 22.271 5.904 ;
     RECT  21.731 8.208 22.271 11.844 ;
     RECT  21.947 85.266 22.271 91.764 ;
     RECT  22.235 92.556 22.271 96.012 ;
     RECT  21.911 96.876 22.271 97.866 ;
     RECT  21.911 98.892 22.271 98.91 ;
     RECT  21.6 34.326 22.307 36.144 ;
     RECT  21.767 36.936 22.307 42.624 ;
     RECT  22.307 34.326 22.343 36.072 ;
     RECT  21.767 43.416 22.343 43.866 ;
     RECT  22.235 44.694 22.343 50.922 ;
     RECT  22.343 34.326 22.379 35.496 ;
     RECT  22.271 85.266 22.451 91.494 ;
     RECT  21.911 51.984 22.487 52.974 ;
     RECT  21.695 71.856 22.523 77.544 ;
     RECT  22.271 96.876 22.523 97.056 ;
     RECT  22.523 76.788 22.559 77.544 ;
     RECT  22.271 5.886 22.739 5.904 ;
     RECT  21.695 18.198 22.775 18.414 ;
     RECT  22.343 44.694 22.775 50.814 ;
     RECT  22.343 43.848 22.783 43.866 ;
     RECT  22.775 44.694 22.783 47.754 ;
     RECT  22.271 2.466 22.811 3.024 ;
     RECT  22.271 5.076 22.811 5.094 ;
     RECT  22.235 6.786 22.811 7.218 ;
     RECT  22.271 8.208 22.811 11.574 ;
     RECT  21.947 12.798 22.811 14.202 ;
     RECT  22.235 15.426 22.811 17.244 ;
     RECT  22.775 18.396 22.811 18.414 ;
     RECT  21.695 19.206 22.811 21.654 ;
     RECT  22.235 22.446 22.811 23.454 ;
     RECT  21.875 26.226 22.811 30.024 ;
     RECT  21.6 30.924 22.811 33.174 ;
     RECT  22.379 34.326 22.811 34.344 ;
     RECT  22.379 35.478 22.811 35.496 ;
     RECT  22.307 37.026 22.811 42.624 ;
     RECT  22.775 48.816 22.811 50.814 ;
     RECT  22.487 52.146 22.811 52.974 ;
     RECT  22.235 54.216 22.811 57.906 ;
     RECT  22.055 60.156 22.811 63.729 ;
     RECT  22.235 68.256 22.811 70.974 ;
     RECT  22.523 71.856 22.811 75.996 ;
     RECT  22.559 76.86 22.811 77.544 ;
     RECT  22.235 78.606 22.811 84.132 ;
     RECT  22.451 85.356 22.811 91.494 ;
     RECT  22.271 92.556 22.811 95.904 ;
     RECT  22.523 96.876 22.811 96.894 ;
     RECT  22.811 41.256 22.819 42.624 ;
     RECT  21.947 59.004 22.819 59.184 ;
     RECT  22.811 2.466 22.847 2.754 ;
     RECT  22.271 3.888 22.847 4.284 ;
     RECT  22.811 11.106 22.847 11.574 ;
     RECT  22.811 13.716 22.847 14.202 ;
     RECT  22.811 19.386 22.847 19.944 ;
     RECT  22.811 20.736 22.847 21.654 ;
     RECT  22.811 23.436 22.847 23.454 ;
     RECT  22.811 26.946 22.847 29.862 ;
     RECT  22.811 38.178 22.847 38.196 ;
     RECT  22.819 41.256 22.847 42.822 ;
     RECT  22.783 43.848 22.847 47.754 ;
     RECT  22.811 52.326 22.847 52.974 ;
     RECT  22.811 54.414 22.847 56.664 ;
     RECT  22.819 58.698 22.847 59.184 ;
     RECT  22.811 63.486 22.847 63.729 ;
     RECT  22.055 64.836 22.847 65.124 ;
     RECT  22.235 66.186 22.847 66.888 ;
     RECT  22.811 68.256 22.847 70.902 ;
     RECT  22.811 82.8 22.847 84.132 ;
     RECT  22.811 88.74 22.847 90.612 ;
     RECT  22.811 91.476 22.847 91.494 ;
     RECT  22.811 94.14 22.847 94.464 ;
     RECT  22.271 97.848 22.847 97.866 ;
     RECT  22.847 11.106 22.883 11.124 ;
     RECT  22.847 27.756 22.883 27.774 ;
     RECT  22.847 29.538 22.883 29.862 ;
     RECT  22.811 39.096 22.883 40.464 ;
     RECT  22.847 83.61 22.883 83.934 ;
     RECT  22.811 87.39 22.883 87.876 ;
     RECT  22.847 41.526 22.919 42.822 ;
     RECT  22.847 52.416 22.919 52.434 ;
     RECT  22.847 54.414 22.919 55.008 ;
     RECT  22.811 85.806 22.919 86.634 ;
     RECT  22.811 49.896 22.955 50.814 ;
     RECT  22.847 58.698 22.955 58.788 ;
     RECT  22.811 73.854 22.955 75.996 ;
     RECT  22.847 82.836 22.955 82.854 ;
     RECT  22.955 49.896 22.991 50.724 ;
     RECT  22.811 78.678 22.991 79.236 ;
     RECT  22.919 86.616 22.991 86.634 ;
     RECT  22.811 31.194 23.639 32.256 ;
     RECT  22.811 37.17 23.639 37.224 ;
     RECT  22.991 49.896 23.639 50.454 ;
     RECT  22.919 54.414 23.639 54.504 ;
     RECT  22.847 55.836 23.639 56.664 ;
     RECT  22.847 66.186 23.639 66.384 ;
     RECT  22.955 73.854 23.639 73.944 ;
     RECT  22.955 75.204 23.639 75.996 ;
     RECT  22.811 92.556 23.639 93.312 ;
     RECT  22.847 2.736 23.675 2.754 ;
     RECT  22.811 8.208 23.675 8.226 ;
     RECT  22.811 9.126 23.675 9.882 ;
     RECT  22.811 12.798 23.675 12.816 ;
     RECT  22.847 14.184 23.675 14.202 ;
     RECT  22.847 20.736 23.675 20.952 ;
     RECT  22.883 29.538 23.675 29.556 ;
     RECT  23.639 31.194 23.675 31.212 ;
     RECT  23.639 32.238 23.675 32.256 ;
     RECT  22.811 33.156 23.675 33.174 ;
     RECT  23.639 37.17 23.675 37.188 ;
     RECT  22.883 39.096 23.675 39.114 ;
     RECT  22.883 40.446 23.675 40.464 ;
     RECT  22.919 41.526 23.675 42.624 ;
     RECT  22.847 43.848 23.675 43.866 ;
     RECT  22.847 44.964 23.675 45.792 ;
     RECT  22.847 46.584 23.675 47.214 ;
     RECT  22.811 48.816 23.675 48.996 ;
     RECT  23.639 50.364 23.675 50.382 ;
     RECT  23.639 54.486 23.675 54.504 ;
     RECT  23.639 55.836 23.675 55.854 ;
     RECT  23.639 56.646 23.675 56.664 ;
     RECT  22.811 60.516 23.675 60.912 ;
     RECT  22.811 61.776 23.675 62.694 ;
     RECT  22.847 63.594 23.675 63.729 ;
     RECT  22.847 65.106 23.675 65.124 ;
     RECT  23.639 66.186 23.675 66.204 ;
     RECT  22.847 68.256 23.675 70.632 ;
     RECT  22.811 71.856 23.675 72.864 ;
     RECT  23.639 73.854 23.675 73.872 ;
     RECT  23.639 75.402 23.675 75.996 ;
     RECT  22.811 76.86 23.675 76.878 ;
     RECT  22.991 79.218 23.675 79.236 ;
     RECT  22.811 80.604 23.675 81.666 ;
     RECT  22.919 85.806 23.675 85.824 ;
     RECT  22.883 87.39 23.675 87.408 ;
     RECT  22.847 89.244 23.675 90.612 ;
     RECT  23.639 92.556 23.675 93.042 ;
    LAYER M3 ;
     RECT  8.28 2.101 8.298 2.143 ;
     RECT  13.14 2.029 13.158 2.143 ;
     RECT  5.436 2.029 5.454 2.191 ;
     RECT  7.815 2.143 8.298 2.227 ;
     RECT  14.724 2.101 14.742 2.227 ;
     RECT  2.415 2.143 2.505 2.263 ;
     RECT  7.815 2.227 8.586 2.263 ;
     RECT  11.124 2.101 11.142 2.263 ;
     RECT  7.815 2.263 8.766 2.293 ;
     RECT  5.436 2.191 5.742 2.299 ;
     RECT  11.124 2.263 11.286 2.299 ;
     RECT  14.328 2.227 14.742 2.299 ;
     RECT  16.2 2.191 16.506 2.299 ;
     RECT  2.415 2.263 3.438 2.335 ;
     RECT  10.476 2.299 11.538 2.335 ;
     RECT  13.14 2.143 13.305 2.335 ;
     RECT  6.696 2.299 6.714 2.347 ;
     RECT  7.815 2.293 9.162 2.347 ;
     RECT  9.9 2.335 11.574 2.347 ;
     RECT  16.2 2.299 16.938 2.371 ;
     RECT  20.304 2.335 20.322 2.371 ;
     RECT  18.615 2.143 18.705 2.413 ;
     RECT  13.068 2.335 13.554 2.461 ;
     RECT  14.328 2.299 14.778 2.461 ;
     RECT  13.032 2.461 14.778 2.491 ;
     RECT  13.032 2.491 14.85 2.497 ;
     RECT  5.4 2.299 5.742 2.533 ;
     RECT  6.696 2.347 11.574 2.533 ;
     RECT  17.748 2.371 17.766 2.533 ;
     RECT  12.78 2.497 14.85 2.539 ;
     RECT  15.588 2.371 16.938 2.539 ;
     RECT  17.676 2.533 17.766 2.539 ;
     RECT  2.415 2.335 3.762 2.569 ;
     RECT  5.4 2.533 11.574 2.569 ;
     RECT  12.6 2.539 17.766 2.569 ;
     RECT  18.615 2.413 18.897 2.569 ;
     RECT  2.415 2.569 4.302 2.605 ;
     RECT  20.304 2.371 20.754 2.605 ;
     RECT  21.744 2.587 21.762 2.605 ;
     RECT  2.304 2.605 4.302 2.641 ;
     RECT  5.076 2.569 11.754 2.641 ;
     RECT  12.6 2.569 18.897 2.641 ;
     RECT  20.304 2.605 21.762 2.641 ;
     RECT  2.304 2.641 21.762 2.669 ;
     RECT  22.824 2.461 22.842 2.803 ;
     RECT  0.108 2.803 0.126 3.005 ;
     RECT  23.652 2.731 23.67 3.197 ;
     RECT  22.5 2.803 22.842 3.343 ;
     RECT  22.248 3.343 22.842 3.581 ;
     RECT  2.304 2.669 21.474 3.721 ;
     RECT  2.304 3.721 21.69 4.315 ;
     RECT  22.5 3.581 22.842 4.315 ;
     RECT  2.304 4.315 22.842 4.451 ;
     RECT  2.304 4.451 21.474 4.541 ;
     RECT  2.304 4.541 21.186 4.649 ;
     RECT  22.5 4.451 22.842 4.733 ;
     RECT  22.788 4.733 22.842 4.925 ;
     RECT  22.788 4.925 22.806 5.117 ;
     RECT  2.304 4.649 2.697 5.467 ;
     RECT  3.456 4.649 21.186 5.467 ;
     RECT  21.924 5.275 21.942 5.467 ;
     RECT  2.304 5.467 21.942 5.659 ;
     RECT  2.304 5.659 22.266 5.851 ;
     RECT  2.304 5.851 22.734 6.269 ;
     RECT  0.108 6.817 0.126 6.941 ;
     RECT  22.788 6.619 22.806 7.232 ;
     RECT  2.415 6.269 21.69 7.531 ;
     RECT  2.304 7.531 21.69 7.771 ;
     RECT  23.652 7.579 23.67 7.963 ;
     RECT  23.616 7.963 23.67 8.093 ;
     RECT  2.304 7.771 21.726 8.159 ;
     RECT  20.772 8.159 21.726 8.189 ;
     RECT  20.772 8.189 21.654 8.537 ;
     RECT  2.304 8.159 20.034 8.941 ;
     RECT  20.772 8.537 21.438 8.941 ;
     RECT  22.788 8.059 22.806 9.115 ;
     RECT  2.304 8.941 21.438 9.499 ;
     RECT  22.212 9.115 22.806 9.509 ;
     RECT  2.052 9.499 21.438 9.815 ;
     RECT  2.304 9.815 21.438 9.883 ;
     RECT  23.652 8.093 23.67 9.887 ;
     RECT  2.304 9.883 21.87 10.121 ;
     RECT  2.304 10.121 21.51 10.843 ;
     RECT  2.304 10.843 21.834 10.967 ;
     RECT  22.788 9.509 22.806 11.101 ;
     RECT  2.304 10.967 21.69 11.821 ;
     RECT  22.788 11.101 22.878 11.821 ;
     RECT  2.304 11.821 22.878 11.837 ;
     RECT  2.304 11.837 22.266 12.029 ;
     RECT  2.304 12.029 22.23 12.325 ;
     RECT  2.268 12.325 22.23 12.461 ;
     RECT  2.304 12.461 22.23 12.515 ;
     RECT  23.652 12.763 23.67 12.821 ;
     RECT  2.415 12.515 22.23 12.929 ;
     RECT  22.788 12.955 22.806 13.127 ;
     RECT  0.108 13.063 0.126 13.133 ;
     RECT  2.415 12.929 21.87 13.631 ;
     RECT  2.415 13.631 21.474 13.667 ;
     RECT  2.415 13.667 21.402 13.723 ;
     RECT  22.824 13.711 22.842 13.757 ;
     RECT  2.34 13.723 21.402 14.059 ;
     RECT  2.304 14.059 21.402 14.135 ;
     RECT  23.652 14.107 23.67 14.207 ;
     RECT  2.34 14.135 21.402 14.491 ;
     RECT  2.34 14.491 21.942 15.016 ;
     RECT  2.304 15.016 21.942 15.259 ;
     RECT  22.788 14.683 22.806 15.259 ;
     RECT  2.304 15.259 22.806 15.296 ;
     RECT  2.304 15.296 21.654 15.359 ;
     RECT  0.108 15.259 0.126 15.389 ;
     RECT  2.304 15.359 21.51 15.557 ;
     RECT  2.304 15.557 21.438 15.899 ;
     RECT  22.788 15.296 22.806 16.219 ;
     RECT  22.248 16.219 22.806 16.439 ;
     RECT  2.304 15.899 21.222 16.879 ;
     RECT  22.752 16.439 22.806 17.261 ;
     RECT  2.304 16.879 21.546 17.419 ;
     RECT  2.304 17.419 22.23 17.456 ;
     RECT  2.304 17.456 21.582 17.681 ;
     RECT  1.116 16.609 1.134 17.761 ;
     RECT  22.788 17.995 22.806 18.184 ;
     RECT  0.54 17.761 1.134 18.193 ;
     RECT  22.752 18.184 22.806 18.221 ;
     RECT  0.108 18.193 1.134 18.317 ;
     RECT  2.304 17.681 21.294 18.769 ;
     RECT  2.304 18.769 21.69 19.181 ;
     RECT  22.788 18.221 22.806 19.309 ;
     RECT  0.54 18.317 1.134 19.345 ;
     RECT  2.304 19.181 21.258 19.345 ;
     RECT  22.248 19.309 22.806 19.381 ;
     RECT  22.248 19.381 22.842 19.757 ;
     RECT  22.788 19.757 22.842 20.141 ;
     RECT  22.788 20.141 22.806 20.309 ;
     RECT  0.54 19.345 21.258 20.461 ;
     RECT  23.652 20.683 23.67 20.957 ;
     RECT  0.54 20.461 21.654 21.067 ;
     RECT  0.54 21.067 21.69 21.497 ;
     RECT  0.54 21.497 21.654 21.569 ;
     RECT  0.54 21.569 21.618 21.677 ;
     RECT  22.824 21.631 22.842 21.869 ;
     RECT  22.788 22.027 22.806 22.411 ;
     RECT  22.752 22.411 22.806 22.603 ;
     RECT  0.54 21.677 21.258 22.747 ;
     RECT  0.108 22.747 21.258 22.795 ;
     RECT  22.212 22.603 22.806 22.795 ;
     RECT  0.108 22.795 22.806 22.877 ;
     RECT  0.54 22.877 22.806 23.431 ;
     RECT  0.54 23.431 22.842 23.729 ;
     RECT  22.824 23.729 22.842 23.789 ;
     RECT  0.54 23.729 21.87 25.015 ;
     RECT  0.108 25.015 21.87 25.181 ;
     RECT  0.54 25.181 21.87 26.635 ;
     RECT  22.788 26.059 22.806 26.635 ;
     RECT  0.54 26.635 22.806 26.941 ;
     RECT  0.54 26.941 22.842 27.211 ;
     RECT  0.504 27.211 22.842 27.239 ;
     RECT  0.504 27.239 21.726 27.437 ;
     RECT  22.788 27.239 22.842 27.509 ;
     RECT  22.824 27.509 22.842 27.751 ;
     RECT  22.824 27.751 22.878 28.013 ;
     RECT  0.54 27.437 21.726 28.453 ;
     RECT  22.824 28.013 22.842 28.453 ;
     RECT  0.54 28.453 22.842 28.781 ;
     RECT  0.54 28.781 21.726 29.515 ;
     RECT  22.788 28.781 22.842 29.515 ;
     RECT  23.652 29.131 23.67 29.561 ;
     RECT  0.54 29.515 22.842 29.839 ;
     RECT  0.54 29.839 22.878 30.701 ;
     RECT  0.54 30.701 22.806 30.859 ;
     RECT  23.652 30.859 23.67 31.051 ;
     RECT  23.616 31.051 23.67 31.559 ;
     RECT  0.504 30.859 22.806 31.829 ;
     RECT  0.504 31.829 22.302 32.035 ;
     RECT  0.432 32.035 22.302 32.773 ;
     RECT  0.432 32.773 22.806 32.813 ;
     RECT  0.432 32.813 22.266 33.005 ;
     RECT  23.652 31.559 23.67 33.179 ;
     RECT  0.468 33.005 22.266 33.931 ;
     RECT  0.468 33.931 22.806 34.349 ;
     RECT  0.468 34.349 22.374 35.464 ;
     RECT  0.468 35.464 22.806 35.501 ;
     RECT  0.468 35.501 22.374 35.815 ;
     RECT  0.108 35.815 22.374 35.933 ;
     RECT  0.468 35.933 22.374 36.269 ;
     RECT  23.652 36.811 23.67 37.003 ;
     RECT  0.468 36.269 22.302 37.021 ;
     RECT  23.616 37.003 23.67 37.193 ;
     RECT  23.616 37.193 23.634 37.229 ;
     RECT  0.468 37.021 22.806 37.963 ;
     RECT  0.468 37.963 22.914 38.713 ;
     RECT  0.108 38.713 22.914 38.861 ;
     RECT  23.652 38.011 23.67 39.119 ;
     RECT  0.468 38.861 22.914 41.131 ;
     RECT  23.652 40.123 23.67 42.629 ;
     RECT  0.108 41.131 22.914 45.455 ;
     RECT  0.324 45.455 22.914 46.309 ;
     RECT  0.288 46.309 22.914 46.315 ;
     RECT  23.652 43.771 23.67 47.219 ;
     RECT  0.108 46.315 22.914 49.723 ;
     RECT  23.652 48.571 23.67 49.723 ;
     RECT  0.108 49.723 23.67 50.387 ;
     RECT  0.108 50.387 23.634 50.459 ;
     RECT  0.108 50.459 22.986 50.729 ;
     RECT  0.108 50.729 22.95 50.855 ;
     RECT  0.288 50.855 22.95 52.987 ;
     RECT  0.288 52.987 23.67 54.067 ;
     RECT  0.108 54.067 23.67 54.509 ;
     RECT  0.108 54.509 22.95 54.635 ;
     RECT  0.288 54.635 22.95 55.483 ;
     RECT  0.288 55.483 23.67 56.335 ;
     RECT  0.108 56.335 23.67 56.477 ;
     RECT  0.288 56.477 23.67 56.669 ;
     RECT  0.288 56.669 22.95 58.363 ;
     RECT  0.108 58.363 22.95 59.495 ;
     RECT  0.252 59.495 22.95 60.107 ;
     RECT  0.288 60.107 22.95 60.139 ;
     RECT  0.288 60.139 23.67 61.003 ;
     RECT  0.108 61.003 23.67 61.385 ;
     RECT  0.144 61.385 23.67 62.299 ;
     RECT  0.108 62.299 23.67 62.735 ;
     RECT  0.252 62.735 23.67 63.595 ;
     RECT  0.144 63.595 23.67 63.653 ;
     RECT  0.288 63.653 23.67 66.055 ;
     RECT  0.108 66.055 23.67 66.209 ;
     RECT  0.108 66.209 23.634 66.221 ;
     RECT  0.288 66.221 23.634 66.389 ;
     RECT  0.288 66.389 22.95 68.011 ;
     RECT  0.288 68.011 23.67 69.997 ;
     RECT  0.108 69.997 23.67 70.157 ;
     RECT  0.288 70.157 23.67 70.637 ;
     RECT  0.288 70.637 22.95 71.467 ;
     RECT  0.288 71.467 23.67 73.877 ;
     RECT  0.288 73.877 23.634 73.949 ;
     RECT  0.288 73.949 22.95 74.587 ;
     RECT  0.108 74.587 22.95 74.717 ;
     RECT  0.288 74.717 22.95 74.923 ;
     RECT  0.288 74.923 23.67 76.883 ;
     RECT  0.288 76.883 22.95 78.673 ;
     RECT  0.288 78.673 22.986 79.147 ;
     RECT  0.288 79.147 23.67 79.241 ;
     RECT  0.288 79.241 22.986 79.313 ;
     RECT  0.36 79.313 22.986 79.949 ;
     RECT  0.396 79.949 22.986 79.963 ;
     RECT  0.396 79.963 23.67 80.969 ;
     RECT  0.432 80.969 23.67 81.671 ;
     RECT  0.432 81.671 22.986 83.767 ;
     RECT  0.108 83.767 22.986 84.509 ;
     RECT  0.432 84.509 22.986 85.531 ;
     RECT  0.432 85.531 23.67 85.829 ;
     RECT  0.432 85.829 22.986 87.259 ;
     RECT  0.432 87.259 23.67 87.413 ;
     RECT  0.432 87.413 22.95 88.219 ;
     RECT  0.432 88.219 23.67 88.349 ;
     RECT  0.432 88.349 22.95 89.069 ;
     RECT  0.468 89.069 22.95 89.179 ;
     RECT  0.468 89.179 23.67 89.261 ;
     RECT  0.504 89.261 23.67 89.879 ;
     RECT  0.504 89.879 22.842 90.173 ;
     RECT  23.652 89.879 23.67 90.617 ;
     RECT  0.504 90.173 22.806 91.165 ;
     RECT  0.108 91.165 22.806 91.471 ;
     RECT  0.108 91.471 22.842 91.517 ;
     RECT  0.108 91.517 22.374 91.733 ;
     RECT  0.108 91.733 1.098 91.997 ;
     RECT  0.504 91.997 1.098 92.039 ;
     RECT  23.652 92.059 23.67 92.443 ;
     RECT  0.504 92.039 1.062 92.579 ;
     RECT  0.504 92.579 0.522 92.813 ;
     RECT  1.908 91.733 22.374 92.821 ;
     RECT  23.616 92.443 23.67 93.047 ;
     RECT  23.616 93.047 23.634 93.317 ;
     RECT  1.908 92.821 22.842 93.389 ;
     RECT  2.304 93.389 22.842 93.965 ;
     RECT  0.108 93.523 0.126 94.253 ;
     RECT  2.415 93.965 22.842 94.433 ;
     RECT  22.32 94.433 22.842 94.469 ;
     RECT  22.392 94.469 22.842 94.589 ;
     RECT  22.392 94.589 22.806 94.631 ;
     RECT  2.415 94.433 21.438 95.227 ;
     RECT  2.304 95.227 21.438 95.549 ;
     RECT  22.752 94.631 22.806 95.659 ;
     RECT  22.248 95.659 22.806 95.981 ;
     RECT  22.248 95.981 22.77 96.016 ;
     RECT  22.212 96.016 22.77 96.221 ;
     RECT  2.34 95.549 21.438 96.259 ;
     RECT  2.34 96.259 21.654 96.667 ;
     RECT  2.304 96.667 21.654 96.701 ;
     RECT  22.752 96.221 22.77 96.871 ;
     RECT  22.752 96.871 22.806 97.033 ;
     RECT  22.5 97.033 22.806 97.141 ;
     RECT  0.108 96.565 0.126 97.229 ;
     RECT  2.304 96.701 21.258 97.645 ;
     RECT  2.304 97.645 21.294 97.672 ;
     RECT  2.268 97.672 21.294 97.681 ;
     RECT  22.248 97.141 22.806 97.681 ;
     RECT  2.268 97.681 22.806 97.835 ;
     RECT  2.304 97.835 22.806 97.843 ;
     RECT  2.304 97.843 22.842 98.717 ;
     RECT  2.304 98.717 21.294 99.197 ;
     RECT  2.304 99.197 14.202 99.245 ;
     RECT  14.94 99.197 17.334 99.245 ;
     RECT  20.88 99.197 20.898 99.245 ;
     RECT  18.324 99.197 20.142 99.293 ;
     RECT  16.02 99.245 17.334 99.329 ;
     RECT  2.304 99.245 14.13 99.533 ;
     RECT  18.324 99.293 19.602 99.533 ;
     RECT  19.116 99.533 19.602 99.677 ;
     RECT  2.304 99.533 13.086 99.725 ;
     RECT  14.94 99.245 14.958 99.725 ;
     RECT  16.488 99.329 17.334 99.725 ;
     RECT  18.324 99.533 18.342 99.725 ;
     RECT  19.296 99.677 19.602 99.725 ;
     RECT  2.736 99.725 2.754 100.349 ;
     RECT  5.04 99.725 5.058 100.349 ;
     RECT  6.876 99.725 7.686 100.349 ;
     RECT  14.112 99.533 14.13 100.349 ;
     RECT  16.488 99.725 16.506 100.349 ;
     RECT  7.308 100.349 7.686 100.397 ;
     RECT  7.668 100.397 7.686 100.445 ;
     RECT  8.892 99.725 8.91 100.877 ;
     RECT  22.248 98.717 22.842 100.925 ;
     RECT  22.824 100.925 22.842 101.405 ;
    LAYER M4 ;
     RECT  0.084 2.64 0.137 2.664 ;
     RECT  0.06 2.664 0.137 2.976 ;
     RECT  0.084 2.976 0.137 3 ;
     RECT  0.06 3 0.137 3.312 ;
     RECT  0.084 3.312 0.137 3.336 ;
     RECT  0.06 3.336 0.137 3.648 ;
     RECT  0.084 3.648 0.137 3.672 ;
     RECT  0.06 3.672 0.137 3.936 ;
     RECT  0.084 3.936 0.137 3.96 ;
     RECT  0.06 3.96 0.137 4.272 ;
     RECT  0.084 4.272 0.137 4.296 ;
     RECT  0.06 4.296 0.137 4.608 ;
     RECT  0.084 4.608 0.137 4.632 ;
     RECT  0.06 4.632 0.137 4.944 ;
     RECT  0.084 4.944 0.137 4.968 ;
     RECT  0.06 4.968 0.137 5.28 ;
     RECT  0.084 5.28 0.137 5.304 ;
     RECT  0.06 5.304 0.137 5.568 ;
     RECT  0.084 5.568 0.137 5.592 ;
     RECT  0.06 5.592 0.137 5.904 ;
     RECT  0.084 5.904 0.137 5.928 ;
     RECT  0.06 5.928 0.137 6.24 ;
     RECT  0.084 6.24 0.137 6.264 ;
     RECT  0.06 6.264 0.137 6.576 ;
     RECT  0.084 6.576 0.137 6.6 ;
     RECT  0.06 6.6 0.137 6.912 ;
     RECT  0.084 6.912 0.137 6.936 ;
     RECT  0.06 6.936 0.137 7.2 ;
     RECT  0.084 7.2 0.137 7.224 ;
     RECT  0.06 7.224 0.137 7.536 ;
     RECT  0.084 7.536 0.137 7.56 ;
     RECT  0.06 7.56 0.137 7.872 ;
     RECT  0.084 7.872 0.137 7.896 ;
     RECT  0.06 7.896 0.137 8.208 ;
     RECT  0.084 8.208 0.137 8.232 ;
     RECT  0.06 8.232 0.137 8.496 ;
     RECT  0.084 8.496 0.137 8.52 ;
     RECT  0.06 8.52 0.137 8.832 ;
     RECT  0.084 8.832 0.137 8.856 ;
     RECT  0.06 8.856 0.137 9.168 ;
     RECT  0.084 9.168 0.137 9.192 ;
     RECT  0.06 9.192 0.137 9.504 ;
     RECT  0.084 9.504 0.137 9.528 ;
     RECT  0.06 9.528 0.137 9.84 ;
     RECT  0.084 9.84 0.137 9.864 ;
     RECT  0.06 9.864 0.137 10.128 ;
     RECT  0.084 10.128 0.137 10.152 ;
     RECT  0.06 10.152 0.137 10.464 ;
     RECT  0.084 10.464 0.137 10.488 ;
     RECT  0.06 10.488 0.137 10.8 ;
     RECT  0.084 10.8 0.137 10.824 ;
     RECT  0.06 10.824 0.137 11.136 ;
     RECT  0.084 11.136 0.137 11.16 ;
     RECT  0.06 11.16 0.137 11.472 ;
     RECT  0.084 11.472 0.137 11.496 ;
     RECT  0.06 11.496 0.137 11.76 ;
     RECT  0.084 11.76 0.137 11.784 ;
     RECT  0.06 11.784 0.137 12.096 ;
     RECT  0.084 12.096 0.137 12.12 ;
     RECT  0.06 12.12 0.137 12.432 ;
     RECT  0.084 12.432 0.137 12.456 ;
     RECT  0.06 12.456 0.137 12.768 ;
     RECT  0.084 12.768 0.137 12.792 ;
     RECT  0.06 12.792 0.137 13.104 ;
     RECT  0.084 13.104 0.137 13.128 ;
     RECT  0.06 13.128 0.137 13.392 ;
     RECT  0.084 13.392 0.137 13.416 ;
     RECT  0.06 13.416 0.137 13.728 ;
     RECT  0.084 13.728 0.137 13.752 ;
     RECT  0.06 13.752 0.137 14.064 ;
     RECT  0.084 14.064 0.137 14.088 ;
     RECT  0.06 14.088 0.137 14.4 ;
     RECT  0.084 14.4 0.137 14.424 ;
     RECT  0.06 14.424 0.137 14.688 ;
     RECT  0.084 14.688 0.137 14.712 ;
     RECT  0.06 14.712 0.137 15.024 ;
     RECT  0.084 15.024 0.137 15.048 ;
     RECT  0.06 15.048 0.137 15.36 ;
     RECT  0.084 15.36 0.137 15.384 ;
     RECT  0.06 15.384 0.137 15.696 ;
     RECT  0.084 15.696 0.137 15.72 ;
     RECT  0.06 15.72 0.137 16.032 ;
     RECT  0.084 16.032 0.137 16.056 ;
     RECT  0.06 16.056 0.137 16.32 ;
     RECT  0.084 16.32 0.137 16.344 ;
     RECT  0.06 16.344 0.137 16.656 ;
     RECT  0.084 16.656 0.137 16.68 ;
     RECT  0.06 16.68 0.137 16.992 ;
     RECT  0.084 16.992 0.137 17.016 ;
     RECT  0.06 17.016 0.137 17.328 ;
     RECT  0.084 17.328 0.137 17.352 ;
     RECT  0.06 17.352 0.137 17.664 ;
     RECT  0.084 17.664 0.137 17.688 ;
     RECT  0.06 17.688 0.137 17.952 ;
     RECT  0.084 17.952 0.137 17.976 ;
     RECT  0.06 17.976 0.137 18.288 ;
     RECT  0.084 18.288 0.137 18.312 ;
     RECT  0.06 18.312 0.137 18.624 ;
     RECT  0.084 18.624 0.137 18.648 ;
     RECT  0.06 18.648 0.137 18.96 ;
     RECT  0.084 18.96 0.137 18.984 ;
     RECT  0.06 18.984 0.137 19.296 ;
     RECT  0.084 19.296 0.137 19.32 ;
     RECT  0.06 19.32 0.137 19.584 ;
     RECT  0.084 19.584 0.137 19.608 ;
     RECT  0.06 19.608 0.137 19.92 ;
     RECT  0.084 19.92 0.137 19.944 ;
     RECT  0.06 19.944 0.137 20.256 ;
     RECT  0.084 20.256 0.137 20.28 ;
     RECT  0.06 20.28 0.137 20.592 ;
     RECT  0.084 20.592 0.137 20.616 ;
     RECT  0.06 20.616 0.137 20.88 ;
     RECT  0.084 20.88 0.137 20.904 ;
     RECT  0.06 20.904 0.137 21.216 ;
     RECT  0.084 21.216 0.137 21.24 ;
     RECT  0.06 21.24 0.137 21.552 ;
     RECT  0.084 21.552 0.137 21.576 ;
     RECT  0.06 21.576 0.137 21.888 ;
     RECT  0.084 21.888 0.137 21.912 ;
     RECT  0.06 21.912 0.137 22.224 ;
     RECT  0.084 22.224 0.137 22.248 ;
     RECT  0.06 22.248 0.137 22.512 ;
     RECT  0.084 22.512 0.137 22.536 ;
     RECT  0.06 22.536 0.137 22.848 ;
     RECT  0.084 22.848 0.137 22.872 ;
     RECT  0.06 22.872 0.137 23.184 ;
     RECT  0.084 23.184 0.137 23.208 ;
     RECT  0.06 23.208 0.137 23.52 ;
     RECT  0.084 23.52 0.137 23.544 ;
     RECT  0.06 23.544 0.137 23.856 ;
     RECT  0.084 23.856 0.137 23.88 ;
     RECT  0.06 23.88 0.137 24.144 ;
     RECT  0.084 24.144 0.137 24.168 ;
     RECT  0.06 24.168 0.137 24.48 ;
     RECT  0.084 24.48 0.137 24.504 ;
     RECT  0.06 24.504 0.137 24.816 ;
     RECT  0.084 24.816 0.137 24.84 ;
     RECT  0.06 24.84 0.137 25.152 ;
     RECT  0.084 25.152 0.137 25.176 ;
     RECT  0.06 25.176 0.137 25.488 ;
     RECT  0.084 25.488 0.137 25.512 ;
     RECT  0.06 25.512 0.137 25.776 ;
     RECT  0.084 25.776 0.137 25.8 ;
     RECT  0.06 25.8 0.137 26.112 ;
     RECT  0.084 26.112 0.137 26.136 ;
     RECT  0.06 26.136 0.137 26.448 ;
     RECT  0.084 26.448 0.137 26.472 ;
     RECT  0.06 26.472 0.137 26.784 ;
     RECT  0.084 26.784 0.137 26.808 ;
     RECT  0.06 26.808 0.137 27.12 ;
     RECT  0.084 27.12 0.137 27.144 ;
     RECT  0.06 27.144 0.137 27.408 ;
     RECT  0.084 27.408 0.137 27.432 ;
     RECT  0.06 27.432 0.137 27.744 ;
     RECT  0.084 27.744 0.137 27.768 ;
     RECT  0.06 27.768 0.137 28.08 ;
     RECT  0.084 28.08 0.137 28.104 ;
     RECT  0.06 28.104 0.137 28.416 ;
     RECT  0.084 28.416 0.137 28.44 ;
     RECT  0.06 28.44 0.137 28.704 ;
     RECT  0.084 28.704 0.137 28.728 ;
     RECT  0.06 28.728 0.137 29.04 ;
     RECT  0.084 29.04 0.137 29.064 ;
     RECT  0.06 29.064 0.137 29.376 ;
     RECT  0.084 29.376 0.137 29.4 ;
     RECT  0.06 29.4 0.137 29.712 ;
     RECT  0.084 29.712 0.137 29.736 ;
     RECT  0.06 29.736 0.137 30.048 ;
     RECT  0.084 30.048 0.137 30.072 ;
     RECT  0.06 30.072 0.137 30.336 ;
     RECT  0.084 30.336 0.137 30.36 ;
     RECT  0.06 30.36 0.137 30.672 ;
     RECT  0.084 30.672 0.137 30.696 ;
     RECT  0.06 30.696 0.137 31.008 ;
     RECT  0.084 31.008 0.137 31.032 ;
     RECT  0.06 31.032 0.137 31.344 ;
     RECT  0.084 31.344 0.137 31.368 ;
     RECT  0.06 31.368 0.137 31.68 ;
     RECT  0.084 31.68 0.137 31.704 ;
     RECT  0.06 31.704 0.137 31.968 ;
     RECT  0.084 31.968 0.137 31.992 ;
     RECT  0.06 31.992 0.137 32.304 ;
     RECT  0.084 32.304 0.137 32.328 ;
     RECT  0.06 32.328 0.137 32.64 ;
     RECT  0.084 32.64 0.137 32.664 ;
     RECT  0.06 32.664 0.137 32.976 ;
     RECT  0.084 32.976 0.137 33 ;
     RECT  0.06 33 0.137 33.312 ;
     RECT  0.084 33.312 0.137 33.336 ;
     RECT  0.06 33.336 0.137 33.6 ;
     RECT  0.084 33.6 0.137 33.624 ;
     RECT  0.06 33.624 0.137 33.936 ;
     RECT  0.084 33.936 0.137 33.96 ;
     RECT  0.06 33.96 0.137 34.272 ;
     RECT  0.084 34.272 0.137 34.296 ;
     RECT  0.06 34.296 0.137 34.608 ;
     RECT  0.084 34.608 0.137 34.632 ;
     RECT  0.06 34.632 0.137 34.896 ;
     RECT  0.084 34.896 0.137 34.92 ;
     RECT  0.06 34.92 0.137 35.232 ;
     RECT  0.084 35.232 0.137 35.256 ;
     RECT  0.06 35.256 0.137 35.568 ;
     RECT  0.084 35.568 0.137 35.592 ;
     RECT  0.06 35.592 0.137 35.904 ;
     RECT  0.084 35.904 0.137 35.928 ;
     RECT  0.06 35.928 0.137 36.24 ;
     RECT  0.084 36.24 0.137 36.264 ;
     RECT  0.06 36.264 0.137 36.528 ;
     RECT  0.084 36.528 0.137 36.552 ;
     RECT  0.06 36.552 0.137 36.864 ;
     RECT  0.084 36.864 0.137 36.888 ;
     RECT  0.06 36.888 0.137 37.2 ;
     RECT  0.084 37.2 0.137 37.224 ;
     RECT  0.06 37.224 0.137 37.536 ;
     RECT  0.084 37.536 0.137 37.56 ;
     RECT  0.06 37.56 0.137 37.872 ;
     RECT  0.084 37.872 0.137 37.896 ;
     RECT  0.06 37.896 0.137 38.16 ;
     RECT  0.084 38.16 0.137 38.184 ;
     RECT  0.06 38.184 0.137 38.496 ;
     RECT  0.084 38.496 0.137 38.52 ;
     RECT  0.06 38.52 0.137 38.832 ;
     RECT  0.084 38.832 0.137 38.856 ;
     RECT  0.06 38.856 0.137 39.168 ;
     RECT  0.084 39.168 0.137 39.192 ;
     RECT  0.06 39.192 0.137 39.504 ;
     RECT  0.084 39.504 0.137 39.528 ;
     RECT  0.06 39.528 0.137 39.792 ;
     RECT  0.084 39.792 0.137 39.816 ;
     RECT  0.06 39.816 0.137 40.128 ;
     RECT  0.084 40.128 0.137 40.152 ;
     RECT  0.06 40.152 0.137 40.464 ;
     RECT  0.084 40.464 0.137 40.488 ;
     RECT  0.06 40.488 0.137 40.8 ;
     RECT  0.084 40.8 0.137 40.824 ;
     RECT  0.06 40.824 0.137 41.136 ;
     RECT  0.084 41.136 0.137 41.16 ;
     RECT  0.06 41.16 0.137 41.424 ;
     RECT  0.084 41.424 0.137 41.448 ;
     RECT  0.06 41.448 0.137 41.76 ;
     RECT  0.084 41.76 0.137 41.784 ;
     RECT  0.06 41.784 0.137 42.096 ;
     RECT  0.084 42.096 0.137 42.12 ;
     RECT  0.06 42.12 0.137 42.432 ;
     RECT  0.084 42.432 0.137 42.456 ;
     RECT  0.06 42.456 0.137 42.72 ;
     RECT  0.084 42.72 0.137 42.744 ;
     RECT  0.06 42.744 0.137 43.056 ;
     RECT  0.084 43.056 0.137 43.08 ;
     RECT  0.06 43.08 0.137 43.392 ;
     RECT  0.084 43.392 0.137 43.416 ;
     RECT  0.06 43.416 0.137 43.728 ;
     RECT  0.084 43.728 0.137 43.752 ;
     RECT  0.06 43.752 0.137 44.064 ;
     RECT  0.084 44.064 0.137 44.088 ;
     RECT  0.06 44.088 0.137 44.352 ;
     RECT  0.084 44.352 0.137 44.376 ;
     RECT  0.06 44.376 0.137 44.688 ;
     RECT  0.084 44.688 0.137 44.712 ;
     RECT  0.06 44.712 0.137 45.024 ;
     RECT  0.084 45.024 0.137 45.048 ;
     RECT  0.06 45.048 0.137 45.36 ;
     RECT  0.084 45.36 0.137 45.384 ;
     RECT  0.06 45.384 0.137 45.696 ;
     RECT  0.084 45.696 0.137 45.72 ;
     RECT  0.06 45.72 0.137 45.984 ;
     RECT  0.084 45.984 0.137 46.008 ;
     RECT  0.06 46.008 0.137 46.32 ;
     RECT  0.084 46.32 0.137 46.344 ;
     RECT  0.06 46.344 0.137 46.656 ;
     RECT  0.084 46.656 0.137 46.68 ;
     RECT  0.06 46.68 0.137 46.992 ;
     RECT  0.084 46.992 0.137 47.016 ;
     RECT  0.06 47.016 0.137 47.328 ;
     RECT  0.084 47.328 0.137 47.352 ;
     RECT  0.06 47.352 0.137 47.616 ;
     RECT  0.084 47.616 0.137 47.64 ;
     RECT  0.06 47.64 0.137 47.952 ;
     RECT  0.084 47.952 0.137 47.976 ;
     RECT  0.06 47.976 0.137 48.288 ;
     RECT  0.084 48.288 0.137 48.312 ;
     RECT  0.06 48.312 0.137 48.624 ;
     RECT  0.084 48.624 0.137 48.648 ;
     RECT  0.06 48.648 0.137 48.912 ;
     RECT  0.084 48.912 0.137 48.936 ;
     RECT  0.06 48.936 0.137 49.248 ;
     RECT  0.084 49.248 0.137 49.272 ;
     RECT  0.06 49.272 0.137 49.584 ;
     RECT  0.084 49.584 0.137 49.608 ;
     RECT  0.06 49.608 0.137 49.92 ;
     RECT  0.084 49.92 0.137 49.944 ;
     RECT  0.06 49.944 0.137 50.256 ;
     RECT  0.084 50.256 0.137 50.28 ;
     RECT  0.06 50.28 0.137 50.544 ;
     RECT  0.084 50.544 0.137 50.568 ;
     RECT  0.06 50.568 0.137 50.88 ;
     RECT  0.084 50.88 0.137 50.904 ;
     RECT  0.06 50.904 0.137 51.216 ;
     RECT  0.084 51.216 0.137 51.24 ;
     RECT  0.06 51.24 0.137 51.552 ;
     RECT  0.084 51.552 0.137 51.576 ;
     RECT  0.06 51.576 0.137 51.888 ;
     RECT  0.084 51.888 0.137 51.912 ;
     RECT  0.06 51.912 0.137 52.176 ;
     RECT  0.084 52.176 0.137 52.2 ;
     RECT  0.06 52.2 0.137 52.512 ;
     RECT  0.084 52.512 0.137 52.536 ;
     RECT  0.06 52.536 0.137 52.848 ;
     RECT  0.084 52.848 0.137 52.872 ;
     RECT  0.06 52.872 0.137 53.184 ;
     RECT  0.084 53.184 0.137 53.208 ;
     RECT  0.06 53.208 0.137 53.52 ;
     RECT  0.084 53.52 0.137 53.544 ;
     RECT  0.06 53.544 0.137 53.808 ;
     RECT  0.084 53.808 0.137 53.832 ;
     RECT  0.06 53.832 0.137 54.144 ;
     RECT  0.084 54.144 0.137 54.168 ;
     RECT  0.06 54.168 0.137 54.48 ;
     RECT  0.084 54.48 0.137 54.504 ;
     RECT  0.06 54.504 0.137 54.816 ;
     RECT  0.084 54.816 0.137 54.84 ;
     RECT  0.06 54.84 0.137 55.104 ;
     RECT  0.084 55.104 0.137 55.128 ;
     RECT  0.06 55.128 0.137 55.44 ;
     RECT  0.084 55.44 0.137 55.464 ;
     RECT  0.06 55.464 0.137 55.776 ;
     RECT  0.084 55.776 0.137 55.8 ;
     RECT  0.06 55.8 0.137 56.112 ;
     RECT  0.084 56.112 0.137 56.136 ;
     RECT  0.06 56.136 0.137 56.448 ;
     RECT  0.084 56.448 0.137 56.472 ;
     RECT  0.06 56.472 0.137 56.736 ;
     RECT  0.084 56.736 0.137 56.76 ;
     RECT  0.06 56.76 0.137 57.072 ;
     RECT  0.084 57.072 0.137 57.096 ;
     RECT  0.06 57.096 0.137 57.408 ;
     RECT  0.084 57.408 0.137 57.432 ;
     RECT  0.06 57.432 0.137 57.744 ;
     RECT  0.084 57.744 0.137 57.768 ;
     RECT  0.06 57.768 0.137 58.08 ;
     RECT  0.084 58.08 0.137 58.104 ;
     RECT  0.06 58.104 0.137 58.368 ;
     RECT  0.084 58.368 0.137 58.392 ;
     RECT  0.06 58.392 0.137 58.704 ;
     RECT  0.084 58.704 0.137 58.728 ;
     RECT  0.06 58.728 0.137 59.04 ;
     RECT  0.084 59.04 0.137 59.064 ;
     RECT  0.06 59.064 0.137 59.376 ;
     RECT  0.084 59.376 0.137 59.4 ;
     RECT  0.06 59.4 0.137 59.712 ;
     RECT  0.084 59.712 0.137 59.736 ;
     RECT  0.06 59.736 0.137 60 ;
     RECT  0.084 60 0.137 60.024 ;
     RECT  0.06 60.024 0.137 60.336 ;
     RECT  0.084 60.336 0.137 60.36 ;
     RECT  0.06 60.36 0.137 60.672 ;
     RECT  0.084 60.672 0.137 60.696 ;
     RECT  0.06 60.696 0.137 61.008 ;
     RECT  0.084 61.008 0.137 61.032 ;
     RECT  0.06 61.032 0.137 61.344 ;
     RECT  0.084 61.344 0.137 61.368 ;
     RECT  0.06 61.368 0.137 61.632 ;
     RECT  0.084 61.632 0.137 61.656 ;
     RECT  0.06 61.656 0.137 61.968 ;
     RECT  0.084 61.968 0.137 61.992 ;
     RECT  0.06 61.992 0.137 62.304 ;
     RECT  0.084 62.304 0.137 62.328 ;
     RECT  0.06 62.328 0.137 62.64 ;
     RECT  0.084 62.64 0.137 62.664 ;
     RECT  0.06 62.664 0.137 62.928 ;
     RECT  0.084 62.928 0.137 62.952 ;
     RECT  0.06 62.952 0.137 63.264 ;
     RECT  0.084 63.264 0.137 63.288 ;
     RECT  0.06 63.288 0.137 63.6 ;
     RECT  0.084 63.6 0.137 63.624 ;
     RECT  0.06 63.624 0.137 63.936 ;
     RECT  0.084 63.936 0.137 63.96 ;
     RECT  0.06 63.96 0.137 64.272 ;
     RECT  0.084 64.272 0.137 64.296 ;
     RECT  0.06 64.296 0.137 64.56 ;
     RECT  0.084 64.56 0.137 64.584 ;
     RECT  0.06 64.584 0.137 64.896 ;
     RECT  0.084 64.896 0.137 64.92 ;
     RECT  0.06 64.92 0.137 65.232 ;
     RECT  0.084 65.232 0.137 65.256 ;
     RECT  0.06 65.256 0.137 65.568 ;
     RECT  0.084 65.568 0.137 65.592 ;
     RECT  0.06 65.592 0.137 65.904 ;
     RECT  0.084 65.904 0.137 65.928 ;
     RECT  0.06 65.928 0.137 66.192 ;
     RECT  0.084 66.192 0.137 66.216 ;
     RECT  0.06 66.216 0.137 66.528 ;
     RECT  0.084 66.528 0.137 66.552 ;
     RECT  0.06 66.552 0.137 66.864 ;
     RECT  0.084 66.864 0.137 66.888 ;
     RECT  0.06 66.888 0.137 67.2 ;
     RECT  0.084 67.2 0.137 67.224 ;
     RECT  0.06 67.224 0.137 67.536 ;
     RECT  0.084 67.536 0.137 67.56 ;
     RECT  0.06 67.56 0.137 67.824 ;
     RECT  0.084 67.824 0.137 67.848 ;
     RECT  0.06 67.848 0.137 68.16 ;
     RECT  0.084 68.16 0.137 68.184 ;
     RECT  0.06 68.184 0.137 68.496 ;
     RECT  0.084 68.496 0.137 68.52 ;
     RECT  0.06 68.52 0.137 68.832 ;
     RECT  0.084 68.832 0.137 68.856 ;
     RECT  0.06 68.856 0.137 69.12 ;
     RECT  0.084 69.12 0.137 69.144 ;
     RECT  0.06 69.144 0.137 69.456 ;
     RECT  0.084 69.456 0.137 69.48 ;
     RECT  0.06 69.48 0.137 69.792 ;
     RECT  0.084 69.792 0.137 69.816 ;
     RECT  0.06 69.816 0.137 70.128 ;
     RECT  0.084 70.128 0.137 70.152 ;
     RECT  0.06 70.152 0.137 70.464 ;
     RECT  0.084 70.464 0.137 70.488 ;
     RECT  0.06 70.488 0.137 70.752 ;
     RECT  0.084 70.752 0.137 70.776 ;
     RECT  0.06 70.776 0.137 71.088 ;
     RECT  0.084 71.088 0.137 71.112 ;
     RECT  0.06 71.112 0.137 71.424 ;
     RECT  0.084 71.424 0.137 71.448 ;
     RECT  0.06 71.448 0.137 71.76 ;
     RECT  0.084 71.76 0.137 71.784 ;
     RECT  0.06 71.784 0.137 72.096 ;
     RECT  0.084 72.096 0.137 72.12 ;
     RECT  0.06 72.12 0.137 72.384 ;
     RECT  0.084 72.384 0.137 72.408 ;
     RECT  0.06 72.408 0.137 72.72 ;
     RECT  0.084 72.72 0.137 72.744 ;
     RECT  0.06 72.744 0.137 73.056 ;
     RECT  0.084 73.056 0.137 73.08 ;
     RECT  0.06 73.08 0.137 73.392 ;
     RECT  0.084 73.392 0.137 73.416 ;
     RECT  0.06 73.416 0.137 73.728 ;
     RECT  0.084 73.728 0.137 73.752 ;
     RECT  0.06 73.752 0.137 74.016 ;
     RECT  0.084 74.016 0.137 74.04 ;
     RECT  0.06 74.04 0.137 74.352 ;
     RECT  0.084 74.352 0.137 74.376 ;
     RECT  0.06 74.376 0.137 74.688 ;
     RECT  0.084 74.688 0.137 74.712 ;
     RECT  0.06 74.712 0.137 75.024 ;
     RECT  0.084 75.024 0.137 75.048 ;
     RECT  0.06 75.048 0.137 75.312 ;
     RECT  0.084 75.312 0.137 75.336 ;
     RECT  0.06 75.336 0.137 75.648 ;
     RECT  0.084 75.648 0.137 75.672 ;
     RECT  0.06 75.672 0.137 75.984 ;
     RECT  0.084 75.984 0.137 76.008 ;
     RECT  0.06 76.008 0.137 76.32 ;
     RECT  0.084 76.32 0.137 76.344 ;
     RECT  0.06 76.344 0.137 76.656 ;
     RECT  0.084 76.656 0.137 76.68 ;
     RECT  0.06 76.68 0.137 76.944 ;
     RECT  0.084 76.944 0.137 76.968 ;
     RECT  0.06 76.968 0.137 77.28 ;
     RECT  0.084 77.28 0.137 77.304 ;
     RECT  0.06 77.304 0.137 77.616 ;
     RECT  0.084 77.616 0.137 77.64 ;
     RECT  0.06 77.64 0.137 77.952 ;
     RECT  0.084 77.952 0.137 77.976 ;
     RECT  0.06 77.976 0.137 78.288 ;
     RECT  0.084 78.288 0.137 78.312 ;
     RECT  0.06 78.312 0.137 78.576 ;
     RECT  0.084 78.576 0.137 78.6 ;
     RECT  0.06 78.6 0.137 78.912 ;
     RECT  0.084 78.912 0.137 78.936 ;
     RECT  0.06 78.936 0.137 79.248 ;
     RECT  0.084 79.248 0.137 79.272 ;
     RECT  0.06 79.272 0.137 79.584 ;
     RECT  0.084 79.584 0.137 79.608 ;
     RECT  0.06 79.608 0.137 79.92 ;
     RECT  0.084 79.92 0.137 79.944 ;
     RECT  0.06 79.944 0.137 80.208 ;
     RECT  0.084 80.208 0.137 80.232 ;
     RECT  0.06 80.232 0.137 80.544 ;
     RECT  0.084 80.544 0.137 80.568 ;
     RECT  0.06 80.568 0.137 80.88 ;
     RECT  0.084 80.88 0.137 80.904 ;
     RECT  0.06 80.904 0.137 81.216 ;
     RECT  0.084 81.216 0.137 81.24 ;
     RECT  0.06 81.24 0.137 81.552 ;
     RECT  0.084 81.552 0.137 81.576 ;
     RECT  0.06 81.576 0.137 81.84 ;
     RECT  0.084 81.84 0.137 81.864 ;
     RECT  0.06 81.864 0.137 82.176 ;
     RECT  0.084 82.176 0.137 82.2 ;
     RECT  0.06 82.2 0.137 82.512 ;
     RECT  0.084 82.512 0.137 82.536 ;
     RECT  0.06 82.536 0.137 82.848 ;
     RECT  0.084 82.848 0.137 82.872 ;
     RECT  0.06 82.872 0.137 83.136 ;
     RECT  0.084 83.136 0.137 83.16 ;
     RECT  0.06 83.16 0.137 83.472 ;
     RECT  0.084 83.472 0.137 83.496 ;
     RECT  0.06 83.496 0.137 83.808 ;
     RECT  0.084 83.808 0.137 83.832 ;
     RECT  0.06 83.832 0.137 84.144 ;
     RECT  0.084 84.144 0.137 84.168 ;
     RECT  0.06 84.168 0.137 84.48 ;
     RECT  0.084 84.48 0.137 84.504 ;
     RECT  0.06 84.504 0.137 84.768 ;
     RECT  0.084 84.768 0.137 84.792 ;
     RECT  0.06 84.792 0.137 85.104 ;
     RECT  0.084 85.104 0.137 85.128 ;
     RECT  0.06 85.128 0.137 85.44 ;
     RECT  0.084 85.44 0.137 85.464 ;
     RECT  0.06 85.464 0.137 85.776 ;
     RECT  0.084 85.776 0.137 85.8 ;
     RECT  0.06 85.8 0.137 86.112 ;
     RECT  0.084 86.112 0.137 86.136 ;
     RECT  0.06 86.136 0.137 86.4 ;
     RECT  0.084 86.4 0.137 86.424 ;
     RECT  0.06 86.424 0.137 86.736 ;
     RECT  0.084 86.736 0.137 86.76 ;
     RECT  0.06 86.76 0.137 87.072 ;
     RECT  0.084 87.072 0.137 87.096 ;
     RECT  0.06 87.096 0.137 87.408 ;
     RECT  0.084 87.408 0.137 87.432 ;
     RECT  0.06 87.432 0.137 87.744 ;
     RECT  0.084 87.744 0.137 87.768 ;
     RECT  0.06 87.768 0.137 88.032 ;
     RECT  0.084 88.032 0.137 88.056 ;
     RECT  0.06 88.056 0.137 88.368 ;
     RECT  0.084 88.368 0.137 88.392 ;
     RECT  0.06 88.392 0.137 88.704 ;
     RECT  0.084 88.704 0.137 88.728 ;
     RECT  0.06 88.728 0.137 89.04 ;
     RECT  0.084 89.04 0.137 89.064 ;
     RECT  0.06 89.064 0.137 89.328 ;
     RECT  0.084 89.328 0.137 89.352 ;
     RECT  0.06 89.352 0.137 89.664 ;
     RECT  0.084 89.664 0.137 89.688 ;
     RECT  0.06 89.688 0.137 90 ;
     RECT  0.084 90 0.137 90.024 ;
     RECT  0.06 90.024 0.137 90.336 ;
     RECT  0.084 90.336 0.137 90.36 ;
     RECT  0.06 90.36 0.137 90.672 ;
     RECT  0.084 90.672 0.137 90.696 ;
     RECT  0.06 90.696 0.137 90.96 ;
     RECT  0.084 90.96 0.137 90.984 ;
     RECT  0.06 90.984 0.137 91.296 ;
     RECT  0.084 91.296 0.137 91.32 ;
     RECT  0.06 91.32 0.137 91.632 ;
     RECT  0.084 91.632 0.137 91.656 ;
     RECT  0.06 91.656 0.137 91.968 ;
     RECT  0.084 91.968 0.137 91.992 ;
     RECT  0.06 91.992 0.137 92.304 ;
     RECT  0.084 92.304 0.137 92.328 ;
     RECT  0.06 92.328 0.137 92.592 ;
     RECT  0.084 92.592 0.137 92.616 ;
     RECT  0.06 92.616 0.137 92.928 ;
     RECT  0.084 92.928 0.137 92.952 ;
     RECT  0.06 92.952 0.137 93.264 ;
     RECT  0.084 93.264 0.137 93.288 ;
     RECT  0.06 93.288 0.137 93.6 ;
     RECT  0.084 93.6 0.137 93.624 ;
     RECT  0.06 93.624 0.137 93.936 ;
     RECT  0.084 93.936 0.137 93.96 ;
     RECT  0.06 93.96 0.137 94.224 ;
     RECT  0.084 94.224 0.137 94.248 ;
     RECT  0.06 94.248 0.137 94.56 ;
     RECT  0.084 94.56 0.137 94.584 ;
     RECT  0.06 94.584 0.137 94.896 ;
     RECT  0.084 94.896 0.137 94.92 ;
     RECT  0.06 94.92 0.137 95.232 ;
     RECT  0.084 95.232 0.137 95.256 ;
     RECT  0.06 95.256 0.137 95.52 ;
     RECT  0.084 95.52 0.137 95.544 ;
     RECT  0.06 95.544 0.137 95.856 ;
     RECT  0.084 95.856 0.137 95.88 ;
     RECT  0.06 95.88 0.137 96.192 ;
     RECT  0.084 96.192 0.137 96.216 ;
     RECT  0.06 96.216 0.137 96.672 ;
     RECT  0.084 96.672 0.137 96.696 ;
     RECT  0.06 96.696 0.137 96.912 ;
     RECT  0.084 96.912 0.137 96.936 ;
     RECT  0.06 96.936 0.137 97.2 ;
     RECT  0.084 97.2 0.137 97.224 ;
     RECT  0.06 97.224 0.137 97.44 ;
     RECT  0.084 97.44 0.137 97.464 ;
     RECT  0.06 97.464 0.137 97.68 ;
     RECT  0.084 97.68 0.137 97.704 ;
     RECT  0.06 97.704 0.137 97.92 ;
     RECT  0.084 97.92 0.137 97.944 ;
     RECT  0.06 97.944 0.137 98.16 ;
     RECT  0.084 98.16 0.137 98.184 ;
     RECT  0.06 98.184 0.137 98.448 ;
     RECT  0.084 98.448 0.137 98.472 ;
     RECT  0.06 98.472 0.137 98.688 ;
     RECT  0.084 98.688 0.137 98.712 ;
     RECT  0.137 2.64 0.173 41.448 ;
     RECT  0.137 45.696 0.173 48.936 ;
     RECT  0.137 59.712 0.281 98.712 ;
     RECT  0.137 42.48 0.461 44.712 ;
     RECT  0.461 44.688 1.321 44.712 ;
     RECT  0.173 45.696 1.321 46.632 ;
     RECT  0.173 48.288 1.573 48.312 ;
     RECT  0.461 43.632 1.621 43.656 ;
     RECT  1.621 43.536 1.861 43.656 ;
     RECT  1.321 44.688 1.861 46.632 ;
     RECT  0.173 2.64 1.897 40.824 ;
     RECT  0.281 63.936 2.329 98.712 ;
     RECT  2.293 99.696 2.329 99.72 ;
     RECT  1.897 2.64 2.408 41.448 ;
     RECT  0.461 42.48 2.408 42.552 ;
     RECT  1.861 43.536 2.408 46.632 ;
     RECT  1.573 48.288 2.408 49.224 ;
     RECT  0.137 50.88 2.408 53.832 ;
     RECT  0.137 54.816 2.408 58.728 ;
     RECT  0.281 60 2.408 62.952 ;
     RECT  2.329 63.936 2.408 99.72 ;
     RECT  2.408 2.148 2.512 99.72 ;
     RECT  2.512 2.418 2.704 99.72 ;
     RECT  2.704 99.168 2.725 99.72 ;
     RECT  2.704 9.072 2.765 10.152 ;
     RECT  2.704 32.16 2.765 34.92 ;
     RECT  2.704 17.424 2.867 26.184 ;
     RECT  2.704 6.24 2.945 7.656 ;
     RECT  2.867 20.112 2.981 26.184 ;
     RECT  2.704 70.128 2.981 70.824 ;
     RECT  2.704 51.216 3.089 52.824 ;
     RECT  2.725 99.168 3.155 100.344 ;
     RECT  2.704 78.24 3.269 93.528 ;
     RECT  2.704 36.768 3.299 37.032 ;
     RECT  2.704 53.856 3.341 58.728 ;
     RECT  3.269 83.232 3.341 93.528 ;
     RECT  2.704 16.416 3.347 16.44 ;
     RECT  2.704 73.776 3.385 74.664 ;
     RECT  2.867 17.424 3.413 19.032 ;
     RECT  2.704 95.184 3.521 96.936 ;
     RECT  2.704 39.888 3.557 47.208 ;
     RECT  2.981 70.128 3.565 70.248 ;
     RECT  2.704 62.784 3.629 63.816 ;
     RECT  3.341 56.016 3.673 58.728 ;
     RECT  2.704 66.72 3.683 67.752 ;
     RECT  3.673 57.408 3.731 58.728 ;
     RECT  2.704 14.928 3.733 15.384 ;
     RECT  2.765 32.16 3.733 34.824 ;
     RECT  3.299 36.768 3.769 36.984 ;
     RECT  2.704 59.808 3.772 61.224 ;
     RECT  3.341 83.232 3.827 92.952 ;
     RECT  3.521 95.184 3.845 96.744 ;
     RECT  3.733 68.928 3.875 68.952 ;
     RECT  2.981 21.936 3.877 26.184 ;
     RECT  2.704 27.648 3.877 30.888 ;
     RECT  3.841 76.944 3.884 76.968 ;
     RECT  3.884 76.368 3.913 76.968 ;
     RECT  3.269 78.24 3.913 82.056 ;
     RECT  2.704 4.896 3.925 5.112 ;
     RECT  3.841 65.568 3.925 65.592 ;
     RECT  3.683 66.72 3.925 67.176 ;
     RECT  3.925 65.568 3.953 67.176 ;
     RECT  2.945 6.672 3.973 7.656 ;
     RECT  2.765 9.072 3.973 9.336 ;
     RECT  3.973 6.672 3.985 9.336 ;
     RECT  3.985 6.672 4.021 9.768 ;
     RECT  3.877 21.936 4.021 30.888 ;
     RECT  3.733 32.16 4.021 35.352 ;
     RECT  3.557 39.888 4.021 41.496 ;
     RECT  4.021 21.936 4.025 35.352 ;
     RECT  3.985 50.304 4.057 50.328 ;
     RECT  3.565 70.128 4.061 70.152 ;
     RECT  3.913 75.552 4.061 82.056 ;
     RECT  4.021 6.672 4.069 10.248 ;
     RECT  2.704 11.376 4.069 11.448 ;
     RECT  3.733 14.832 4.093 15.384 ;
     RECT  4.057 50.304 4.129 50.616 ;
     RECT  3.089 51.744 4.129 52.824 ;
     RECT  4.093 14.832 4.165 16.2 ;
     RECT  4.069 6.672 4.211 11.448 ;
     RECT  4.061 78.72 4.237 82.056 ;
     RECT  3.827 83.232 4.237 90.504 ;
     RECT  4.025 32.592 4.261 35.352 ;
     RECT  4.237 78.72 4.313 90.504 ;
     RECT  4.165 14.784 4.355 16.2 ;
     RECT  4.313 79.824 4.396 90.504 ;
     RECT  4.355 14.784 4.417 15.624 ;
     RECT  3.413 17.424 4.417 17.688 ;
     RECT  3.769 36.48 4.417 36.984 ;
     RECT  3.953 65.568 4.417 67.08 ;
     RECT  4.357 3.744 4.453 3.768 ;
     RECT  3.385 73.776 4.453 74.328 ;
     RECT  4.061 75.552 4.453 77.496 ;
     RECT  3.845 95.76 4.457 96.744 ;
     RECT  2.704 49.2 4.489 49.224 ;
     RECT  4.129 50.304 4.489 52.824 ;
     RECT  4.417 17.424 4.525 17.88 ;
     RECT  2.981 20.112 4.525 20.904 ;
     RECT  4.025 21.936 4.525 31.416 ;
     RECT  4.129 97.92 4.565 97.944 ;
     RECT  3.629 62.784 4.597 63.72 ;
     RECT  3.913 59.28 4.637 59.304 ;
     RECT  3.413 19.008 4.645 19.032 ;
     RECT  4.525 20.112 4.645 31.416 ;
     RECT  4.021 39.264 4.645 41.496 ;
     RECT  3.557 42.48 4.645 47.208 ;
     RECT  4.597 62.64 4.645 63.72 ;
     RECT  4.489 49.2 4.669 52.824 ;
     RECT  4.645 62.208 4.693 63.72 ;
     RECT  4.211 8.448 4.705 11.448 ;
     RECT  4.489 71.28 4.741 71.304 ;
     RECT  2.704 72.384 4.741 72.408 ;
     RECT  4.645 39.264 4.789 47.208 ;
     RECT  4.789 39.216 4.813 47.208 ;
     RECT  4.741 71.28 4.813 72.408 ;
     RECT  4.453 73.776 4.813 77.496 ;
     RECT  3.781 12.912 4.837 12.936 ;
     RECT  4.417 14.496 4.837 15.624 ;
     RECT  3.772 60.816 4.849 61.224 ;
     RECT  4.693 62.208 4.883 64.008 ;
     RECT  3.155 99.168 4.883 99.72 ;
     RECT  4.417 36.48 4.885 37.704 ;
     RECT  4.883 62.208 4.889 63.912 ;
     RECT  4.457 95.76 4.889 96.312 ;
     RECT  4.453 3.216 4.921 3.768 ;
     RECT  3.925 4.896 4.921 5.16 ;
     RECT  4.885 36.48 4.921 37.752 ;
     RECT  4.669 48.384 4.921 52.824 ;
     RECT  4.417 65.376 4.921 67.08 ;
     RECT  4.381 68.784 4.921 68.808 ;
     RECT  4.921 36.384 4.933 37.752 ;
     RECT  4.813 38.928 4.933 47.208 ;
     RECT  3.673 56.016 4.933 56.328 ;
     RECT  4.921 65.376 4.981 68.808 ;
     RECT  4.705 8.448 4.988 11.736 ;
     RECT  4.837 12.912 4.988 15.624 ;
     RECT  4.933 36.384 4.993 47.208 ;
     RECT  4.921 48.24 4.993 52.824 ;
     RECT  4.933 55.968 4.993 56.328 ;
     RECT  3.731 57.408 4.993 57.72 ;
     RECT  4.849 60.384 4.993 61.224 ;
     RECT  4.889 62.208 4.993 63.816 ;
     RECT  4.525 17.184 5.029 17.88 ;
     RECT  4.993 36.384 5.029 52.824 ;
     RECT  3.827 91.584 5.029 92.952 ;
     RECT  4.883 99.696 5.029 99.72 ;
     RECT  4.921 3.216 5.065 5.16 ;
     RECT  5.029 91.584 5.065 93.48 ;
     RECT  4.981 65.376 5.068 69.72 ;
     RECT  3.341 53.856 5.077 54.984 ;
     RECT  4.993 55.968 5.077 57.72 ;
     RECT  5.065 91.584 5.101 94.296 ;
     RECT  5.065 2.592 5.137 5.16 ;
     RECT  4.211 6.672 5.137 7.368 ;
     RECT  4.645 19.008 5.137 31.416 ;
     RECT  5.077 53.856 5.137 57.72 ;
     RECT  4.993 60.384 5.137 63.816 ;
     RECT  4.813 71.28 5.137 77.496 ;
     RECT  5.029 99.696 5.171 100.344 ;
     RECT  5.137 53.856 5.173 57.864 ;
     RECT  4.261 32.592 5.221 35.4 ;
     RECT  5.029 36.384 5.221 52.872 ;
     RECT  5.029 16.992 5.245 17.88 ;
     RECT  4.988 8.448 5.317 15.624 ;
     RECT  5.245 16.992 5.317 17.928 ;
     RECT  5.137 71.28 5.353 77.64 ;
     RECT  4.313 78.72 5.353 78.744 ;
     RECT  5.137 2.592 5.365 7.368 ;
     RECT  5.317 8.448 5.365 17.928 ;
     RECT  5.353 71.28 5.425 78.744 ;
     RECT  4.396 79.824 5.425 89.784 ;
     RECT  5.101 91.104 5.425 94.296 ;
     RECT  5.365 2.592 5.509 17.928 ;
     RECT  5.137 19.008 5.509 31.512 ;
     RECT  5.221 32.592 5.557 52.872 ;
     RECT  5.173 53.856 5.557 58.056 ;
     RECT  5.425 79.824 5.569 94.296 ;
     RECT  5.557 32.592 5.605 58.056 ;
     RECT  5.068 65.376 5.605 69.528 ;
     RECT  5.425 70.848 5.641 78.744 ;
     RECT  5.509 2.592 5.677 31.512 ;
     RECT  5.605 32.592 5.677 58.152 ;
     RECT  5.677 2.592 5.713 58.152 ;
     RECT  5.641 70.8 5.713 78.744 ;
     RECT  5.569 79.824 5.713 94.584 ;
     RECT  5.137 59.952 5.857 63.816 ;
     RECT  5.605 65.136 5.857 69.528 ;
     RECT  5.713 70.8 5.857 94.584 ;
     RECT  4.889 95.904 5.857 96.312 ;
     RECT  5.173 97.488 5.893 97.512 ;
     RECT  5.713 2.208 5.939 58.152 ;
     RECT  5.171 99.696 6.001 99.72 ;
     RECT  5.857 59.952 6.037 69.528 ;
     RECT  5.857 70.8 6.085 96.312 ;
     RECT  5.893 97.488 6.085 98.088 ;
     RECT  6.085 70.8 6.172 98.088 ;
     RECT  5.939 2.592 6.181 58.152 ;
     RECT  6.037 59.808 6.181 69.528 ;
     RECT  6.172 70.8 6.181 95.928 ;
     RECT  6.181 2.592 6.253 58.536 ;
     RECT  6.253 2.592 6.325 58.728 ;
     RECT  6.181 59.808 6.325 95.928 ;
     RECT  6.001 99.168 6.865 99.72 ;
     RECT  6.172 97.488 6.901 98.088 ;
     RECT  6.325 2.592 7.189 95.928 ;
     RECT  6.901 97.488 7.189 98.136 ;
     RECT  6.865 99.168 7.297 100.344 ;
     RECT  7.297 99.168 7.657 100.392 ;
     RECT  7.189 2.352 7.808 95.928 ;
     RECT  7.189 97.104 7.808 98.136 ;
     RECT  7.657 99.168 7.808 100.44 ;
     RECT  7.808 2.148 7.912 100.44 ;
     RECT  7.912 2.304 8.099 100.44 ;
     RECT  8.099 2.304 8.104 99.72 ;
     RECT  8.104 2.304 9.206 98.424 ;
     RECT  8.881 100.848 9.347 100.872 ;
     RECT  9.206 2.352 9.349 98.424 ;
     RECT  9.349 2.352 9.461 98.616 ;
     RECT  9.461 2.352 10.609 97.704 ;
     RECT  10.609 2.352 10.748 98.616 ;
     RECT  8.104 99.696 10.748 99.72 ;
     RECT  10.748 2.352 11.405 99.72 ;
     RECT  11.405 98.736 11.909 99.72 ;
     RECT  11.405 2.352 12.517 97.32 ;
     RECT  11.909 99.696 12.877 99.72 ;
     RECT  12.517 2.352 13.093 98.088 ;
     RECT  12.877 99.648 13.093 99.72 ;
     RECT  13.093 2.352 13.097 99.72 ;
     RECT  13.097 2.352 13.208 99.528 ;
     RECT  13.208 2.148 13.312 99.528 ;
     RECT  13.312 2.352 13.457 99.528 ;
     RECT  13.457 2.352 13.504 99.24 ;
     RECT  13.504 2.352 13.817 98.136 ;
     RECT  13.817 98.064 14.141 98.136 ;
     RECT  14.101 100.32 14.339 100.344 ;
     RECT  13.817 2.352 14.497 97.032 ;
     RECT  14.141 98.112 14.605 98.136 ;
     RECT  13.504 99.168 14.605 99.24 ;
     RECT  14.497 2.304 14.789 97.032 ;
     RECT  14.605 98.112 14.821 99.24 ;
     RECT  14.821 98.112 14.969 99.72 ;
     RECT  14.789 2.352 15.289 97.032 ;
     RECT  14.969 98.112 15.289 99.24 ;
     RECT  15.289 2.352 15.653 99.24 ;
     RECT  15.653 2.352 15.725 99.192 ;
     RECT  15.725 2.352 16.589 97.944 ;
     RECT  16.477 100.32 16.595 100.344 ;
     RECT  15.725 99.168 16.757 99.192 ;
     RECT  16.589 2.352 17.021 97.704 ;
     RECT  16.757 99.168 17.089 99.72 ;
     RECT  17.021 78.672 17.345 97.704 ;
     RECT  17.021 2.352 17.417 77.4 ;
     RECT  17.417 2.352 17.489 77.304 ;
     RECT  17.345 78.672 17.525 93.576 ;
     RECT  17.345 94.848 17.593 97.704 ;
     RECT  17.089 98.736 17.593 99.72 ;
     RECT  17.525 78.672 17.633 89.976 ;
     RECT  17.489 2.352 18.608 75.96 ;
     RECT  17.489 77.04 18.608 77.304 ;
     RECT  17.633 78.672 18.608 80.328 ;
     RECT  17.633 81.36 18.608 89.976 ;
     RECT  17.525 90.96 18.608 93.576 ;
     RECT  17.593 94.848 18.608 99.72 ;
     RECT  18.608 2.148 18.712 99.72 ;
     RECT  18.712 2.352 18.904 99.72 ;
     RECT  18.904 97.008 18.929 97.608 ;
     RECT  18.904 11.136 18.965 11.496 ;
     RECT  18.904 60 18.965 65.256 ;
     RECT  18.904 95.232 19.001 95.496 ;
     RECT  18.904 24.192 19.037 31.704 ;
     RECT  18.904 16.8 19.043 19.368 ;
     RECT  18.904 66.528 19.043 71.736 ;
     RECT  19.037 24.336 19.073 31.704 ;
     RECT  18.904 74.352 19.073 77.304 ;
     RECT  18.904 5.568 19.091 6.408 ;
     RECT  18.929 97.008 19.145 97.032 ;
     RECT  18.904 21.168 19.283 23.112 ;
     RECT  18.965 11.424 19.289 11.496 ;
     RECT  18.904 12.528 19.325 15.768 ;
     RECT  19.043 71.712 19.325 71.736 ;
     RECT  18.904 78.624 19.325 80.328 ;
     RECT  19.001 95.424 19.325 95.496 ;
     RECT  18.904 72.96 19.397 72.984 ;
     RECT  19.043 16.8 19.433 17.976 ;
     RECT  18.904 7.632 19.469 10.152 ;
     RECT  18.904 2.352 19.475 2.376 ;
     RECT  18.904 91.44 19.475 92.232 ;
     RECT  18.904 45.984 19.505 58.968 ;
     RECT  19.505 45.984 19.571 58.776 ;
     RECT  18.904 32.736 19.577 44.904 ;
     RECT  19.043 66.528 19.577 70.68 ;
     RECT  19.325 78.624 19.577 78.936 ;
     RECT  19.325 80.112 19.613 80.328 ;
     RECT  19.469 7.632 19.619 7.992 ;
     RECT  19.571 45.984 19.619 53.592 ;
     RECT  19.571 54.672 19.619 58.776 ;
     RECT  19.577 66.528 19.619 67.944 ;
     RECT  18.904 81.36 19.619 90.264 ;
     RECT  19.577 68.976 19.649 70.68 ;
     RECT  18.904 98.64 19.657 99.72 ;
     RECT  19.619 7.632 19.667 7.656 ;
     RECT  19.619 66.528 19.667 67.416 ;
     RECT  19.073 76.464 19.667 77.304 ;
     RECT  19.091 5.568 19.715 5.592 ;
     RECT  19.619 46.224 19.793 53.592 ;
     RECT  19.619 86.064 19.865 90.264 ;
     RECT  19.325 12.528 19.901 15.336 ;
     RECT  19.577 32.736 19.909 40.968 ;
     RECT  19.283 21.168 19.969 21.96 ;
     RECT  19.073 24.336 19.973 31.224 ;
     RECT  19.667 76.464 19.973 76.872 ;
     RECT  19.657 98.64 19.973 99.672 ;
     RECT  19.973 26.88 20.003 31.224 ;
     RECT  19.667 67.056 20.009 67.416 ;
     RECT  20.009 67.056 20.045 67.272 ;
     RECT  19.619 54.672 20.051 58.728 ;
     RECT  19.283 23.088 20.099 23.112 ;
     RECT  19.649 68.976 20.099 69.048 ;
     RECT  19.969 21.12 20.117 21.96 ;
     RECT  19.973 24.336 20.117 25.32 ;
     RECT  19.619 81.36 20.117 84.984 ;
     RECT  19.577 42 20.147 44.904 ;
     RECT  19.649 70.08 20.147 70.68 ;
     RECT  19.901 12.528 20.189 15.096 ;
     RECT  20.117 21.792 20.195 21.96 ;
     RECT  19.793 46.224 20.195 53.304 ;
     RECT  20.147 70.32 20.195 70.68 ;
     RECT  19.865 86.208 20.195 90.264 ;
     RECT  19.433 16.8 20.243 17.64 ;
     RECT  20.195 70.656 20.291 70.68 ;
     RECT  20.003 26.88 20.333 29.112 ;
     RECT  20.117 81.36 20.333 83.064 ;
     RECT  19.973 99.168 20.339 99.672 ;
     RECT  19.289 11.424 20.369 11.448 ;
     RECT  20.189 12.528 20.369 12.888 ;
     RECT  19.909 32.208 20.369 40.968 ;
     RECT  20.099 68.976 20.369 69 ;
     RECT  19.577 78.624 20.405 78.744 ;
     RECT  20.195 86.208 20.405 86.76 ;
     RECT  20.003 30.288 20.441 31.224 ;
     RECT  20.243 17.04 20.545 17.64 ;
     RECT  19.043 19.344 20.545 19.368 ;
     RECT  19.973 76.464 20.545 76.68 ;
     RECT  20.545 17.04 20.585 19.368 ;
     RECT  20.117 84.048 20.693 84.984 ;
     RECT  20.369 38.976 20.723 40.968 ;
     RECT  20.693 84.768 20.723 84.984 ;
     RECT  20.195 87.84 20.729 90.264 ;
     RECT  20.369 32.208 20.761 37.992 ;
     RECT  20.195 46.272 20.765 53.304 ;
     RECT  20.149 72.576 20.765 72.6 ;
     RECT  20.723 38.976 20.771 39.48 ;
     RECT  20.147 44.88 20.801 44.904 ;
     RECT  20.771 39.12 20.819 39.48 ;
     RECT  20.723 40.656 20.833 40.968 ;
     RECT  20.147 42 20.909 43.8 ;
     RECT  19.073 74.352 20.909 75.048 ;
     RECT  20.339 99.168 20.909 99.24 ;
     RECT  20.833 40.656 20.945 41.016 ;
     RECT  20.051 54.72 20.945 58.728 ;
     RECT  19.613 80.304 21.013 80.328 ;
     RECT  20.819 39.36 21.017 39.48 ;
     RECT  20.729 88.032 21.017 90.264 ;
     RECT  20.333 26.88 21.059 29.064 ;
     RECT  20.761 31.344 21.059 37.992 ;
     RECT  20.045 67.056 21.085 67.08 ;
     RECT  19.475 91.44 21.085 91.464 ;
     RECT  20.765 46.608 21.155 53.304 ;
     RECT  21.085 6.432 21.157 6.456 ;
     RECT  20.189 14.304 21.157 15.096 ;
     RECT  19.969 96.192 21.197 96.216 ;
     RECT  20.195 21.936 21.229 21.96 ;
     RECT  21.085 97.2 21.229 97.464 ;
     RECT  20.945 40.656 21.305 40.872 ;
     RECT  20.909 99.168 21.347 99.192 ;
     RECT  20.369 12.528 21.373 12.552 ;
     RECT  21.155 46.656 21.373 53.304 ;
     RECT  20.945 54.72 21.373 55.176 ;
     RECT  18.965 60.336 21.373 65.256 ;
     RECT  19.469 9.504 21.409 10.152 ;
     RECT  21.373 12.192 21.409 12.552 ;
     RECT  21.157 13.92 21.409 15.096 ;
     RECT  21.373 60.336 21.409 65.928 ;
     RECT  21.085 67.056 21.409 67.848 ;
     RECT  21.013 80.16 21.409 80.328 ;
     RECT  20.333 81.36 21.409 81.864 ;
     RECT  21.157 6.432 21.445 7.032 ;
     RECT  21.229 21.936 21.445 22.248 ;
     RECT  20.441 30.288 21.445 30.312 ;
     RECT  20.333 82.992 21.445 83.016 ;
     RECT  21.085 91.296 21.445 91.464 ;
     RECT  21.305 40.704 21.449 40.872 ;
     RECT  20.945 56.256 21.449 58.728 ;
     RECT  21.409 8.736 21.481 10.152 ;
     RECT  21.059 26.88 21.481 28.392 ;
     RECT  21.085 78.576 21.481 78.6 ;
     RECT  21.445 90.72 21.481 91.464 ;
     RECT  21.481 8.736 21.517 10.296 ;
     RECT  21.445 30.288 21.517 30.744 ;
     RECT  20.581 71.28 21.517 71.304 ;
     RECT  21.481 77.808 21.517 78.6 ;
     RECT  21.409 80.16 21.517 81.864 ;
     RECT  18.904 93.504 21.517 93.528 ;
     RECT  21.517 29.712 21.529 30.744 ;
     RECT  21.517 77.808 21.553 81.864 ;
     RECT  21.445 82.992 21.553 83.64 ;
     RECT  20.117 24.336 21.589 25.128 ;
     RECT  21.481 26.256 21.589 28.392 ;
     RECT  21.445 6.432 21.625 7.416 ;
     RECT  21.517 8.736 21.625 11.064 ;
     RECT  20.585 17.04 21.625 18.6 ;
     RECT  21.085 20.304 21.625 20.328 ;
     RECT  21.445 21.456 21.625 22.248 ;
     RECT  21.589 24.336 21.625 28.392 ;
     RECT  20.909 42.816 21.625 43.8 ;
     RECT  21.517 71.28 21.625 72.072 ;
     RECT  20.545 76.08 21.625 76.68 ;
     RECT  21.553 77.808 21.625 83.64 ;
     RECT  20.405 86.208 21.625 86.28 ;
     RECT  21.229 97.2 21.625 98.184 ;
     RECT  20.689 2.784 21.661 2.808 ;
     RECT  21.445 4.512 21.661 4.536 ;
     RECT  21.625 6.432 21.661 11.064 ;
     RECT  21.409 12.192 21.661 15.672 ;
     RECT  21.449 56.88 21.661 58.728 ;
     RECT  21.409 59.76 21.661 67.848 ;
     RECT  20.909 74.352 21.661 74.76 ;
     RECT  21.625 86.208 21.661 86.52 ;
     RECT  21.517 93.216 21.661 93.528 ;
     RECT  21.409 94.752 21.661 94.776 ;
     RECT  21.625 20.304 21.697 22.248 ;
     RECT  21.625 23.568 21.697 28.392 ;
     RECT  20.723 84.768 21.697 84.888 ;
     RECT  21.661 86.112 21.697 86.52 ;
     RECT  21.661 2.784 21.733 4.536 ;
     RECT  21.661 6.048 21.733 15.672 ;
     RECT  21.697 84.768 21.805 86.52 ;
     RECT  21.625 42.816 21.841 44.376 ;
     RECT  21.733 45.504 21.841 45.528 ;
     RECT  21.481 90.72 21.841 91.896 ;
     RECT  21.661 93.216 21.841 94.776 ;
     RECT  21.661 73.584 21.877 74.76 ;
     RECT  21.625 76.08 21.877 83.64 ;
     RECT  21.805 84.768 21.877 86.904 ;
     RECT  21.625 96.432 21.877 98.184 ;
     RECT  21.877 73.584 22.165 86.904 ;
     RECT  21.017 88.032 22.165 89.016 ;
     RECT  21.373 46.656 22.201 55.176 ;
     RECT  21.661 56.88 22.201 67.848 ;
     RECT  21.625 70.512 22.201 72.072 ;
     RECT  22.165 73.584 22.201 89.016 ;
     RECT  21.877 96.432 22.201 98.712 ;
     RECT  21.733 2.592 22.237 15.672 ;
     RECT  21.625 17.04 22.237 19.176 ;
     RECT  21.697 20.304 22.237 28.392 ;
     RECT  21.529 29.712 22.237 30.312 ;
     RECT  21.059 32.016 22.237 37.992 ;
     RECT  21.841 90.72 22.237 94.776 ;
     RECT  22.201 96.192 22.237 98.712 ;
     RECT  22.237 31.824 22.309 37.992 ;
     RECT  21.017 39.36 22.309 39.384 ;
     RECT  21.449 40.704 22.309 40.728 ;
     RECT  21.841 42.816 22.309 45.528 ;
     RECT  22.201 46.656 22.309 55.704 ;
     RECT  22.201 56.88 22.489 68.232 ;
     RECT  22.309 31.824 22.705 40.728 ;
     RECT  22.489 56.88 22.741 69.384 ;
     RECT  22.237 90.72 22.741 98.712 ;
     RECT  22.237 2.592 22.777 30.312 ;
     RECT  22.705 31.824 22.777 41.304 ;
     RECT  22.309 42.624 22.777 55.704 ;
     RECT  22.741 56.832 22.777 69.384 ;
     RECT  22.201 70.512 22.777 89.016 ;
     RECT  22.741 90.336 22.777 98.712 ;
     RECT  22.22 100.896 22.789 100.92 ;
     RECT  22.789 100.896 22.876 101.4 ;
     RECT  22.876 100.896 23.315 100.92 ;
     RECT  22.777 2.592 23.605 69.384 ;
     RECT  22.777 70.512 23.605 98.712 ;
     RECT  23.605 2.592 23.676 2.616 ;
     RECT  23.605 2.616 23.724 2.784 ;
     RECT  23.605 2.784 23.676 2.808 ;
     RECT  23.605 2.808 23.724 2.976 ;
     RECT  23.605 2.976 23.676 3 ;
     RECT  23.605 3 23.724 3.168 ;
     RECT  23.605 3.168 23.676 3.192 ;
     RECT  23.605 3.192 23.724 3.36 ;
     RECT  23.605 3.36 23.676 3.384 ;
     RECT  23.605 3.384 23.724 3.552 ;
     RECT  23.605 3.552 23.676 3.576 ;
     RECT  23.605 3.576 23.724 3.744 ;
     RECT  23.605 3.744 23.676 3.768 ;
     RECT  23.605 3.768 23.724 3.936 ;
     RECT  23.605 3.936 23.676 3.96 ;
     RECT  23.605 3.96 23.724 4.128 ;
     RECT  23.605 4.128 23.676 4.152 ;
     RECT  23.605 4.152 23.724 4.32 ;
     RECT  23.605 4.32 23.676 4.344 ;
     RECT  23.605 4.344 23.724 4.512 ;
     RECT  23.605 4.512 23.676 4.536 ;
     RECT  23.605 4.536 23.724 4.704 ;
     RECT  23.605 4.704 23.676 4.728 ;
     RECT  23.605 4.728 23.724 4.896 ;
     RECT  23.605 4.896 23.676 4.92 ;
     RECT  23.605 4.92 23.724 5.088 ;
     RECT  23.605 5.088 23.676 5.112 ;
     RECT  23.605 5.112 23.724 5.28 ;
     RECT  23.605 5.28 23.676 5.304 ;
     RECT  23.605 5.304 23.724 5.472 ;
     RECT  23.605 5.472 23.676 5.496 ;
     RECT  23.605 5.496 23.724 5.664 ;
     RECT  23.605 5.664 23.676 5.688 ;
     RECT  23.605 5.688 23.724 5.856 ;
     RECT  23.605 5.856 23.676 5.88 ;
     RECT  23.605 5.88 23.724 6.048 ;
     RECT  23.605 6.048 23.676 6.072 ;
     RECT  23.605 6.072 23.724 6.24 ;
     RECT  23.605 6.24 23.676 6.264 ;
     RECT  23.605 6.264 23.724 6.432 ;
     RECT  23.605 6.432 23.676 6.456 ;
     RECT  23.605 6.456 23.724 6.624 ;
     RECT  23.605 6.624 23.676 6.648 ;
     RECT  23.605 6.648 23.724 6.816 ;
     RECT  23.605 6.816 23.676 6.84 ;
     RECT  23.605 6.84 23.724 7.008 ;
     RECT  23.605 7.008 23.676 7.032 ;
     RECT  23.605 7.032 23.724 7.2 ;
     RECT  23.605 7.2 23.676 7.224 ;
     RECT  23.605 7.224 23.724 7.392 ;
     RECT  23.605 7.392 23.676 7.416 ;
     RECT  23.605 7.416 23.724 7.584 ;
     RECT  23.605 7.584 23.676 7.608 ;
     RECT  23.605 7.608 23.724 7.776 ;
     RECT  23.605 7.776 23.676 7.8 ;
     RECT  23.605 7.8 23.724 7.968 ;
     RECT  23.605 7.968 23.676 7.992 ;
     RECT  23.605 7.992 23.724 8.16 ;
     RECT  23.605 8.16 23.676 8.184 ;
     RECT  23.605 8.184 23.724 8.352 ;
     RECT  23.605 8.352 23.676 8.376 ;
     RECT  23.605 8.376 23.724 8.544 ;
     RECT  23.605 8.544 23.676 8.568 ;
     RECT  23.605 8.568 23.724 8.736 ;
     RECT  23.605 8.736 23.676 8.76 ;
     RECT  23.605 8.76 23.724 8.928 ;
     RECT  23.605 8.928 23.676 8.952 ;
     RECT  23.605 8.952 23.724 9.12 ;
     RECT  23.605 9.12 23.676 9.144 ;
     RECT  23.605 9.144 23.724 9.312 ;
     RECT  23.605 9.312 23.676 9.336 ;
     RECT  23.605 9.336 23.724 9.504 ;
     RECT  23.605 9.504 23.676 9.528 ;
     RECT  23.605 9.528 23.724 9.696 ;
     RECT  23.605 9.696 23.676 9.72 ;
     RECT  23.605 9.72 23.724 9.888 ;
     RECT  23.605 9.888 23.676 9.912 ;
     RECT  23.605 9.912 23.724 10.08 ;
     RECT  23.605 10.08 23.676 10.104 ;
     RECT  23.605 10.104 23.724 10.272 ;
     RECT  23.605 10.272 23.676 10.296 ;
     RECT  23.605 10.296 23.724 10.464 ;
     RECT  23.605 10.464 23.676 10.488 ;
     RECT  23.605 10.488 23.724 10.656 ;
     RECT  23.605 10.656 23.676 10.68 ;
     RECT  23.605 10.68 23.724 10.848 ;
     RECT  23.605 10.848 23.676 10.872 ;
     RECT  23.605 10.872 23.724 11.04 ;
     RECT  23.605 11.04 23.676 11.064 ;
     RECT  23.605 11.064 23.724 11.232 ;
     RECT  23.605 11.232 23.676 11.256 ;
     RECT  23.605 11.256 23.724 11.424 ;
     RECT  23.605 11.424 23.676 11.448 ;
     RECT  23.605 11.448 23.724 11.616 ;
     RECT  23.605 11.616 23.676 11.64 ;
     RECT  23.605 11.64 23.724 11.808 ;
     RECT  23.605 11.808 23.676 11.832 ;
     RECT  23.605 11.832 23.724 12 ;
     RECT  23.605 12 23.676 12.024 ;
     RECT  23.605 12.024 23.724 12.192 ;
     RECT  23.605 12.192 23.676 12.216 ;
     RECT  23.605 12.216 23.724 12.384 ;
     RECT  23.605 12.384 23.676 12.408 ;
     RECT  23.605 12.408 23.724 12.576 ;
     RECT  23.605 12.576 23.676 12.6 ;
     RECT  23.605 12.6 23.724 12.768 ;
     RECT  23.605 12.768 23.676 12.792 ;
     RECT  23.605 12.792 23.724 12.96 ;
     RECT  23.605 12.96 23.676 12.984 ;
     RECT  23.605 12.984 23.724 13.152 ;
     RECT  23.605 13.152 23.676 13.176 ;
     RECT  23.605 13.176 23.724 13.344 ;
     RECT  23.605 13.344 23.676 13.368 ;
     RECT  23.605 13.368 23.724 13.536 ;
     RECT  23.605 13.536 23.676 13.56 ;
     RECT  23.605 13.56 23.724 13.728 ;
     RECT  23.605 13.728 23.676 13.752 ;
     RECT  23.605 13.752 23.724 13.92 ;
     RECT  23.605 13.92 23.676 13.944 ;
     RECT  23.605 13.944 23.724 14.112 ;
     RECT  23.605 14.112 23.676 14.136 ;
     RECT  23.605 14.136 23.724 14.304 ;
     RECT  23.605 14.304 23.676 14.328 ;
     RECT  23.605 14.328 23.724 14.496 ;
     RECT  23.605 14.496 23.676 14.52 ;
     RECT  23.605 14.52 23.724 14.688 ;
     RECT  23.605 14.688 23.676 14.712 ;
     RECT  23.605 14.712 23.724 14.88 ;
     RECT  23.605 14.88 23.676 14.904 ;
     RECT  23.605 14.904 23.724 15.072 ;
     RECT  23.605 15.072 23.676 15.096 ;
     RECT  23.605 15.096 23.724 15.264 ;
     RECT  23.605 15.264 23.676 15.288 ;
     RECT  23.605 15.288 23.724 15.456 ;
     RECT  23.605 15.456 23.676 15.48 ;
     RECT  23.605 15.48 23.724 15.648 ;
     RECT  23.605 15.648 23.676 15.672 ;
     RECT  23.605 15.672 23.724 15.84 ;
     RECT  23.605 15.84 23.676 15.864 ;
     RECT  23.605 15.864 23.724 16.032 ;
     RECT  23.605 16.032 23.676 16.056 ;
     RECT  23.605 16.056 23.724 16.224 ;
     RECT  23.605 16.224 23.676 16.248 ;
     RECT  23.605 16.248 23.724 16.464 ;
     RECT  23.605 16.464 23.676 16.488 ;
     RECT  23.605 16.488 23.724 16.656 ;
     RECT  23.605 16.656 23.676 16.68 ;
     RECT  23.605 16.68 23.724 16.848 ;
     RECT  23.605 16.848 23.676 16.872 ;
     RECT  23.605 16.872 23.724 17.04 ;
     RECT  23.605 17.04 23.676 17.064 ;
     RECT  23.605 17.064 23.724 17.232 ;
     RECT  23.605 17.232 23.676 17.256 ;
     RECT  23.605 17.256 23.724 17.424 ;
     RECT  23.605 17.424 23.676 17.448 ;
     RECT  23.605 17.448 23.724 17.616 ;
     RECT  23.605 17.616 23.676 17.64 ;
     RECT  23.605 17.64 23.724 17.808 ;
     RECT  23.605 17.808 23.676 17.832 ;
     RECT  23.605 17.832 23.724 18 ;
     RECT  23.605 18 23.676 18.024 ;
     RECT  23.605 18.024 23.724 18.192 ;
     RECT  23.605 18.192 23.676 18.216 ;
     RECT  23.605 18.216 23.724 18.384 ;
     RECT  23.605 18.384 23.676 18.408 ;
     RECT  23.605 18.408 23.724 18.576 ;
     RECT  23.605 18.576 23.676 18.6 ;
     RECT  23.605 18.6 23.724 18.768 ;
     RECT  23.605 18.768 23.676 18.792 ;
     RECT  23.605 18.792 23.724 18.96 ;
     RECT  23.605 18.96 23.676 18.984 ;
     RECT  23.605 18.984 23.724 19.152 ;
     RECT  23.605 19.152 23.676 19.176 ;
     RECT  23.605 19.176 23.724 19.344 ;
     RECT  23.605 19.344 23.676 19.368 ;
     RECT  23.605 19.368 23.724 19.536 ;
     RECT  23.605 19.536 23.676 19.56 ;
     RECT  23.605 19.56 23.724 19.728 ;
     RECT  23.605 19.728 23.676 19.752 ;
     RECT  23.605 19.752 23.724 19.92 ;
     RECT  23.605 19.92 23.676 19.944 ;
     RECT  23.605 19.944 23.724 20.112 ;
     RECT  23.605 20.112 23.676 20.136 ;
     RECT  23.605 20.136 23.724 20.304 ;
     RECT  23.605 20.304 23.676 20.328 ;
     RECT  23.605 20.328 23.724 20.496 ;
     RECT  23.605 20.496 23.676 20.52 ;
     RECT  23.605 20.52 23.724 20.688 ;
     RECT  23.605 20.688 23.676 20.712 ;
     RECT  23.605 20.712 23.724 20.88 ;
     RECT  23.605 20.88 23.676 20.904 ;
     RECT  23.605 20.904 23.724 21.072 ;
     RECT  23.605 21.072 23.676 21.096 ;
     RECT  23.605 21.096 23.724 21.264 ;
     RECT  23.605 21.264 23.676 21.288 ;
     RECT  23.605 21.288 23.724 21.456 ;
     RECT  23.605 21.456 23.676 21.48 ;
     RECT  23.605 21.48 23.724 21.648 ;
     RECT  23.605 21.648 23.676 21.672 ;
     RECT  23.605 21.672 23.724 21.84 ;
     RECT  23.605 21.84 23.676 21.864 ;
     RECT  23.605 21.864 23.724 22.032 ;
     RECT  23.605 22.032 23.676 22.056 ;
     RECT  23.605 22.056 23.724 22.224 ;
     RECT  23.605 22.224 23.676 22.248 ;
     RECT  23.605 22.248 23.724 22.416 ;
     RECT  23.605 22.416 23.676 22.44 ;
     RECT  23.605 22.44 23.724 22.608 ;
     RECT  23.605 22.608 23.676 22.632 ;
     RECT  23.605 22.632 23.724 22.8 ;
     RECT  23.605 22.8 23.676 22.824 ;
     RECT  23.605 22.824 23.724 22.992 ;
     RECT  23.605 22.992 23.676 23.016 ;
     RECT  23.605 23.016 23.724 23.184 ;
     RECT  23.605 23.184 23.676 23.208 ;
     RECT  23.605 23.208 23.724 23.376 ;
     RECT  23.605 23.376 23.676 23.4 ;
     RECT  23.605 23.4 23.724 23.568 ;
     RECT  23.605 23.568 23.676 23.592 ;
     RECT  23.605 23.592 23.724 23.76 ;
     RECT  23.605 23.76 23.676 23.784 ;
     RECT  23.605 23.784 23.724 23.952 ;
     RECT  23.605 23.952 23.676 23.976 ;
     RECT  23.605 23.976 23.724 24.144 ;
     RECT  23.605 24.144 23.676 24.168 ;
     RECT  23.605 24.168 23.724 24.336 ;
     RECT  23.605 24.336 23.676 24.36 ;
     RECT  23.605 24.36 23.724 24.528 ;
     RECT  23.605 24.528 23.676 24.552 ;
     RECT  23.605 24.552 23.724 24.72 ;
     RECT  23.605 24.72 23.676 24.744 ;
     RECT  23.605 24.744 23.724 24.912 ;
     RECT  23.605 24.912 23.676 24.936 ;
     RECT  23.605 24.936 23.724 25.104 ;
     RECT  23.605 25.104 23.676 25.128 ;
     RECT  23.605 25.128 23.724 25.296 ;
     RECT  23.605 25.296 23.676 25.32 ;
     RECT  23.605 25.32 23.724 25.488 ;
     RECT  23.605 25.488 23.676 25.512 ;
     RECT  23.605 25.512 23.724 25.68 ;
     RECT  23.605 25.68 23.676 25.704 ;
     RECT  23.605 25.704 23.724 25.872 ;
     RECT  23.605 25.872 23.676 25.896 ;
     RECT  23.605 25.896 23.724 26.064 ;
     RECT  23.605 26.064 23.676 26.088 ;
     RECT  23.605 26.088 23.724 26.256 ;
     RECT  23.605 26.256 23.676 26.28 ;
     RECT  23.605 26.28 23.724 26.448 ;
     RECT  23.605 26.448 23.676 26.472 ;
     RECT  23.605 26.472 23.724 26.64 ;
     RECT  23.605 26.64 23.676 26.664 ;
     RECT  23.605 26.664 23.724 26.832 ;
     RECT  23.605 26.832 23.676 26.856 ;
     RECT  23.605 26.856 23.724 27.024 ;
     RECT  23.605 27.024 23.676 27.048 ;
     RECT  23.605 27.048 23.724 27.216 ;
     RECT  23.605 27.216 23.676 27.24 ;
     RECT  23.605 27.24 23.724 27.408 ;
     RECT  23.605 27.408 23.676 27.432 ;
     RECT  23.605 27.432 23.724 27.6 ;
     RECT  23.605 27.6 23.676 27.624 ;
     RECT  23.605 27.624 23.724 27.792 ;
     RECT  23.605 27.792 23.676 27.816 ;
     RECT  23.605 27.816 23.724 27.984 ;
     RECT  23.605 27.984 23.676 28.008 ;
     RECT  23.605 28.008 23.724 28.176 ;
     RECT  23.605 28.176 23.676 28.2 ;
     RECT  23.605 28.2 23.724 28.368 ;
     RECT  23.605 28.368 23.676 28.392 ;
     RECT  23.605 28.392 23.724 28.56 ;
     RECT  23.605 28.56 23.676 28.584 ;
     RECT  23.605 28.584 23.724 28.752 ;
     RECT  23.605 28.752 23.676 28.776 ;
     RECT  23.605 28.776 23.724 28.944 ;
     RECT  23.605 28.944 23.676 28.968 ;
     RECT  23.605 28.968 23.724 29.136 ;
     RECT  23.605 29.136 23.676 29.16 ;
     RECT  23.605 29.16 23.724 29.328 ;
     RECT  23.605 29.328 23.676 29.352 ;
     RECT  23.605 29.352 23.724 29.52 ;
     RECT  23.605 29.52 23.676 29.544 ;
     RECT  23.605 29.544 23.724 29.712 ;
     RECT  23.605 29.712 23.676 29.736 ;
     RECT  23.605 29.736 23.724 29.904 ;
     RECT  23.605 29.904 23.676 29.928 ;
     RECT  23.605 29.928 23.724 30.096 ;
     RECT  23.605 30.096 23.676 30.12 ;
     RECT  23.605 30.12 23.724 30.288 ;
     RECT  23.605 30.288 23.676 30.312 ;
     RECT  23.605 30.312 23.724 30.48 ;
     RECT  23.605 30.48 23.676 30.504 ;
     RECT  23.605 30.504 23.724 30.672 ;
     RECT  23.605 30.672 23.676 30.696 ;
     RECT  23.605 30.696 23.724 30.864 ;
     RECT  23.605 30.864 23.676 30.888 ;
     RECT  23.605 30.888 23.724 31.056 ;
     RECT  23.605 31.056 23.676 31.08 ;
     RECT  23.605 31.08 23.724 31.248 ;
     RECT  23.605 31.248 23.676 31.272 ;
     RECT  23.605 31.272 23.724 31.44 ;
     RECT  23.605 31.44 23.676 31.464 ;
     RECT  23.605 31.464 23.724 31.632 ;
     RECT  23.605 31.632 23.676 31.656 ;
     RECT  23.605 31.656 23.724 31.824 ;
     RECT  23.605 31.824 23.676 31.848 ;
     RECT  23.605 31.848 23.724 32.016 ;
     RECT  23.605 32.016 23.676 32.04 ;
     RECT  23.605 32.04 23.724 32.208 ;
     RECT  23.605 32.208 23.676 32.232 ;
     RECT  23.605 32.232 23.724 32.4 ;
     RECT  23.605 32.4 23.676 32.424 ;
     RECT  23.605 32.424 23.724 32.592 ;
     RECT  23.605 32.592 23.676 32.616 ;
     RECT  23.605 32.616 23.724 32.784 ;
     RECT  23.605 32.784 23.676 32.808 ;
     RECT  23.605 32.808 23.724 32.976 ;
     RECT  23.605 32.976 23.676 33 ;
     RECT  23.605 33 23.724 33.168 ;
     RECT  23.605 33.168 23.676 33.192 ;
     RECT  23.605 33.192 23.724 33.36 ;
     RECT  23.605 33.36 23.676 33.384 ;
     RECT  23.605 33.384 23.724 33.552 ;
     RECT  23.605 33.552 23.676 33.576 ;
     RECT  23.605 33.576 23.724 33.744 ;
     RECT  23.605 33.744 23.676 33.768 ;
     RECT  23.605 33.768 23.724 33.936 ;
     RECT  23.605 33.936 23.676 33.96 ;
     RECT  23.605 33.96 23.724 34.128 ;
     RECT  23.605 34.128 23.676 34.152 ;
     RECT  23.605 34.152 23.724 34.32 ;
     RECT  23.605 34.32 23.676 34.344 ;
     RECT  23.605 34.344 23.724 34.512 ;
     RECT  23.605 34.512 23.676 34.536 ;
     RECT  23.605 34.536 23.724 34.704 ;
     RECT  23.605 34.704 23.676 34.728 ;
     RECT  23.605 34.728 23.724 34.896 ;
     RECT  23.605 34.896 23.676 34.92 ;
     RECT  23.605 34.92 23.724 35.088 ;
     RECT  23.605 35.088 23.676 35.112 ;
     RECT  23.605 35.112 23.724 35.28 ;
     RECT  23.605 35.28 23.676 35.304 ;
     RECT  23.605 35.304 23.724 35.472 ;
     RECT  23.605 35.472 23.676 35.496 ;
     RECT  23.605 35.496 23.724 35.664 ;
     RECT  23.605 35.664 23.676 35.688 ;
     RECT  23.605 35.688 23.724 35.856 ;
     RECT  23.605 35.856 23.676 35.88 ;
     RECT  23.605 35.88 23.724 36.048 ;
     RECT  23.605 36.048 23.676 36.072 ;
     RECT  23.605 36.072 23.724 36.24 ;
     RECT  23.605 36.24 23.676 36.264 ;
     RECT  23.605 36.264 23.724 36.432 ;
     RECT  23.605 36.432 23.676 36.456 ;
     RECT  23.605 36.456 23.724 36.624 ;
     RECT  23.605 36.624 23.676 36.648 ;
     RECT  23.605 36.648 23.724 36.816 ;
     RECT  23.605 36.816 23.676 36.84 ;
     RECT  23.605 36.84 23.724 37.008 ;
     RECT  23.605 37.008 23.676 37.032 ;
     RECT  23.605 37.032 23.724 37.2 ;
     RECT  23.605 37.2 23.676 37.224 ;
     RECT  23.605 37.224 23.724 37.392 ;
     RECT  23.605 37.392 23.676 37.416 ;
     RECT  23.605 37.416 23.724 37.632 ;
     RECT  23.605 37.632 23.676 37.656 ;
     RECT  23.605 37.656 23.724 37.824 ;
     RECT  23.605 37.824 23.676 37.848 ;
     RECT  23.605 37.848 23.724 38.016 ;
     RECT  23.605 38.016 23.676 38.04 ;
     RECT  23.605 38.04 23.724 38.208 ;
     RECT  23.605 38.208 23.676 38.232 ;
     RECT  23.605 38.232 23.724 38.4 ;
     RECT  23.605 38.4 23.676 38.424 ;
     RECT  23.605 38.424 23.724 38.592 ;
     RECT  23.605 38.592 23.676 38.616 ;
     RECT  23.605 38.616 23.724 38.784 ;
     RECT  23.605 38.784 23.676 38.808 ;
     RECT  23.605 38.808 23.724 38.976 ;
     RECT  23.605 38.976 23.676 39 ;
     RECT  23.605 39 23.724 39.168 ;
     RECT  23.605 39.168 23.676 39.192 ;
     RECT  23.605 39.192 23.724 39.36 ;
     RECT  23.605 39.36 23.676 39.384 ;
     RECT  23.605 39.384 23.724 39.552 ;
     RECT  23.605 39.552 23.676 39.576 ;
     RECT  23.605 39.576 23.724 39.744 ;
     RECT  23.605 39.744 23.676 39.768 ;
     RECT  23.605 39.768 23.724 39.936 ;
     RECT  23.605 39.936 23.676 39.96 ;
     RECT  23.605 39.96 23.724 40.128 ;
     RECT  23.605 40.128 23.676 40.152 ;
     RECT  23.605 40.152 23.724 40.32 ;
     RECT  23.605 40.32 23.676 40.344 ;
     RECT  23.605 40.344 23.724 40.512 ;
     RECT  23.605 40.512 23.676 40.536 ;
     RECT  23.605 40.536 23.724 40.704 ;
     RECT  23.605 40.704 23.676 40.728 ;
     RECT  23.605 40.728 23.724 40.896 ;
     RECT  23.605 40.896 23.676 40.92 ;
     RECT  23.605 40.92 23.724 41.088 ;
     RECT  23.605 41.088 23.676 41.112 ;
     RECT  23.605 41.112 23.724 41.28 ;
     RECT  23.605 41.28 23.676 41.304 ;
     RECT  23.605 41.304 23.724 41.472 ;
     RECT  23.605 41.472 23.676 41.496 ;
     RECT  23.605 41.496 23.724 41.664 ;
     RECT  23.605 41.664 23.676 41.688 ;
     RECT  23.605 41.688 23.724 41.856 ;
     RECT  23.605 41.856 23.676 41.88 ;
     RECT  23.605 41.88 23.724 42.048 ;
     RECT  23.605 42.048 23.676 42.072 ;
     RECT  23.605 42.072 23.724 42.24 ;
     RECT  23.605 42.24 23.676 42.264 ;
     RECT  23.605 42.264 23.724 42.432 ;
     RECT  23.605 42.432 23.676 42.456 ;
     RECT  23.605 42.456 23.724 42.624 ;
     RECT  23.605 42.624 23.676 42.648 ;
     RECT  23.605 42.648 23.724 42.816 ;
     RECT  23.605 42.816 23.676 42.84 ;
     RECT  23.605 42.84 23.724 43.008 ;
     RECT  23.605 43.008 23.676 43.032 ;
     RECT  23.605 43.032 23.724 43.2 ;
     RECT  23.605 43.2 23.676 43.224 ;
     RECT  23.605 43.224 23.724 43.392 ;
     RECT  23.605 43.392 23.676 43.416 ;
     RECT  23.605 43.416 23.724 43.584 ;
     RECT  23.605 43.584 23.676 43.608 ;
     RECT  23.605 43.608 23.724 43.776 ;
     RECT  23.605 43.776 23.676 43.8 ;
     RECT  23.605 43.8 23.724 43.968 ;
     RECT  23.605 43.968 23.676 43.992 ;
     RECT  23.605 43.992 23.724 44.16 ;
     RECT  23.605 44.16 23.676 44.184 ;
     RECT  23.605 44.184 23.724 44.352 ;
     RECT  23.605 44.352 23.676 44.376 ;
     RECT  23.605 44.376 23.724 44.544 ;
     RECT  23.605 44.544 23.676 44.568 ;
     RECT  23.605 44.568 23.724 44.736 ;
     RECT  23.605 44.736 23.676 44.76 ;
     RECT  23.605 44.76 23.724 44.928 ;
     RECT  23.605 44.928 23.676 44.952 ;
     RECT  23.605 44.952 23.724 45.12 ;
     RECT  23.605 45.12 23.676 45.144 ;
     RECT  23.605 45.144 23.724 45.312 ;
     RECT  23.605 45.312 23.676 45.336 ;
     RECT  23.605 45.336 23.724 45.504 ;
     RECT  23.605 45.504 23.676 45.528 ;
     RECT  23.605 45.528 23.724 45.696 ;
     RECT  23.605 45.696 23.676 45.72 ;
     RECT  23.605 45.72 23.724 45.888 ;
     RECT  23.605 45.888 23.676 45.912 ;
     RECT  23.605 45.912 23.724 46.08 ;
     RECT  23.605 46.08 23.676 46.104 ;
     RECT  23.605 46.104 23.724 46.272 ;
     RECT  23.605 46.272 23.676 46.296 ;
     RECT  23.605 46.296 23.724 46.464 ;
     RECT  23.605 46.464 23.676 46.488 ;
     RECT  23.605 46.488 23.724 46.656 ;
     RECT  23.605 46.656 23.676 46.68 ;
     RECT  23.605 46.68 23.724 46.848 ;
     RECT  23.605 46.848 23.676 46.872 ;
     RECT  23.605 46.872 23.724 47.04 ;
     RECT  23.605 47.04 23.676 47.064 ;
     RECT  23.605 47.064 23.724 47.232 ;
     RECT  23.605 47.232 23.676 47.256 ;
     RECT  23.605 47.256 23.724 47.424 ;
     RECT  23.605 47.424 23.676 47.448 ;
     RECT  23.605 47.448 23.724 47.616 ;
     RECT  23.605 47.616 23.676 47.64 ;
     RECT  23.605 47.64 23.724 47.808 ;
     RECT  23.605 47.808 23.676 47.832 ;
     RECT  23.605 47.832 23.724 48 ;
     RECT  23.605 48 23.676 48.024 ;
     RECT  23.605 48.024 23.724 48.192 ;
     RECT  23.605 48.192 23.676 48.216 ;
     RECT  23.605 48.216 23.724 48.384 ;
     RECT  23.605 48.384 23.676 48.408 ;
     RECT  23.605 48.408 23.724 48.576 ;
     RECT  23.605 48.576 23.676 48.6 ;
     RECT  23.605 48.6 23.724 48.768 ;
     RECT  23.605 48.768 23.676 48.792 ;
     RECT  23.605 48.792 23.724 48.96 ;
     RECT  23.605 48.96 23.676 48.984 ;
     RECT  23.605 48.984 23.724 49.152 ;
     RECT  23.605 49.152 23.676 49.176 ;
     RECT  23.605 49.176 23.724 49.344 ;
     RECT  23.605 49.344 23.676 49.368 ;
     RECT  23.605 49.368 23.724 49.536 ;
     RECT  23.605 49.536 23.676 49.56 ;
     RECT  23.605 49.56 23.724 49.728 ;
     RECT  23.605 49.728 23.676 49.752 ;
     RECT  23.605 49.752 23.724 49.92 ;
     RECT  23.605 49.92 23.676 49.944 ;
     RECT  23.605 49.944 23.724 50.112 ;
     RECT  23.605 50.112 23.676 50.136 ;
     RECT  23.605 50.136 23.724 50.304 ;
     RECT  23.605 50.304 23.676 50.328 ;
     RECT  23.605 50.328 23.724 50.496 ;
     RECT  23.605 50.496 23.676 50.52 ;
     RECT  23.605 50.52 23.724 50.688 ;
     RECT  23.605 50.688 23.676 50.712 ;
     RECT  23.605 50.712 23.724 50.88 ;
     RECT  23.605 50.88 23.676 50.904 ;
     RECT  23.605 50.904 23.724 51.072 ;
     RECT  23.605 51.072 23.676 51.096 ;
     RECT  23.605 51.096 23.724 51.264 ;
     RECT  23.605 51.264 23.676 51.288 ;
     RECT  23.605 51.288 23.724 51.456 ;
     RECT  23.605 51.456 23.676 51.48 ;
     RECT  23.605 51.48 23.724 51.648 ;
     RECT  23.605 51.648 23.676 51.672 ;
     RECT  23.605 51.672 23.724 51.84 ;
     RECT  23.605 51.84 23.676 51.864 ;
     RECT  23.605 51.864 23.724 52.032 ;
     RECT  23.605 52.032 23.676 52.056 ;
     RECT  23.605 52.056 23.724 52.224 ;
     RECT  23.605 52.224 23.676 52.248 ;
     RECT  23.605 52.248 23.724 52.416 ;
     RECT  23.605 52.416 23.676 52.44 ;
     RECT  23.605 52.44 23.724 52.608 ;
     RECT  23.605 52.608 23.676 52.632 ;
     RECT  23.605 52.632 23.724 52.8 ;
     RECT  23.605 52.8 23.676 52.824 ;
     RECT  23.605 52.824 23.724 52.992 ;
     RECT  23.605 52.992 23.676 53.016 ;
     RECT  23.605 53.016 23.724 53.184 ;
     RECT  23.605 53.184 23.676 53.208 ;
     RECT  23.605 53.208 23.724 53.376 ;
     RECT  23.605 53.376 23.676 53.4 ;
     RECT  23.605 53.4 23.724 53.568 ;
     RECT  23.605 53.568 23.676 53.592 ;
     RECT  23.605 53.592 23.724 53.76 ;
     RECT  23.605 53.76 23.676 53.784 ;
     RECT  23.605 53.784 23.724 53.952 ;
     RECT  23.605 53.952 23.676 53.976 ;
     RECT  23.605 53.976 23.724 54.144 ;
     RECT  23.605 54.144 23.676 54.168 ;
     RECT  23.605 54.168 23.724 54.336 ;
     RECT  23.605 54.336 23.676 54.36 ;
     RECT  23.605 54.36 23.724 54.528 ;
     RECT  23.605 54.528 23.676 54.552 ;
     RECT  23.605 54.552 23.724 54.72 ;
     RECT  23.605 54.72 23.676 54.744 ;
     RECT  23.605 54.744 23.724 54.912 ;
     RECT  23.605 54.912 23.676 54.936 ;
     RECT  23.605 54.936 23.724 55.104 ;
     RECT  23.605 55.104 23.676 55.128 ;
     RECT  23.605 55.128 23.724 55.296 ;
     RECT  23.605 55.296 23.676 55.32 ;
     RECT  23.605 55.32 23.724 55.488 ;
     RECT  23.605 55.488 23.676 55.512 ;
     RECT  23.605 55.512 23.724 55.68 ;
     RECT  23.605 55.68 23.676 55.704 ;
     RECT  23.605 55.704 23.724 55.872 ;
     RECT  23.605 55.872 23.676 55.896 ;
     RECT  23.605 55.896 23.724 56.064 ;
     RECT  23.605 56.064 23.676 56.088 ;
     RECT  23.605 56.088 23.724 56.256 ;
     RECT  23.605 56.256 23.676 56.28 ;
     RECT  23.605 56.28 23.724 56.448 ;
     RECT  23.605 56.448 23.676 56.472 ;
     RECT  23.605 56.472 23.724 56.64 ;
     RECT  23.605 56.64 23.676 56.664 ;
     RECT  23.605 56.664 23.724 56.832 ;
     RECT  23.605 56.832 23.676 56.856 ;
     RECT  23.605 56.856 23.724 57.024 ;
     RECT  23.605 57.024 23.676 57.048 ;
     RECT  23.605 57.048 23.724 57.216 ;
     RECT  23.605 57.216 23.676 57.24 ;
     RECT  23.605 57.24 23.724 57.408 ;
     RECT  23.605 57.408 23.676 57.432 ;
     RECT  23.605 57.432 23.724 57.6 ;
     RECT  23.605 57.6 23.676 57.624 ;
     RECT  23.605 57.624 23.724 57.792 ;
     RECT  23.605 57.792 23.676 57.816 ;
     RECT  23.605 57.816 23.724 57.984 ;
     RECT  23.605 57.984 23.676 58.008 ;
     RECT  23.605 58.008 23.724 58.176 ;
     RECT  23.605 58.176 23.676 58.2 ;
     RECT  23.605 58.2 23.724 58.368 ;
     RECT  23.605 58.368 23.676 58.392 ;
     RECT  23.605 58.392 23.724 58.608 ;
     RECT  23.605 58.608 23.676 58.632 ;
     RECT  23.605 58.632 23.724 58.8 ;
     RECT  23.605 58.8 23.676 58.824 ;
     RECT  23.605 58.824 23.724 58.992 ;
     RECT  23.605 58.992 23.676 59.016 ;
     RECT  23.605 59.016 23.724 59.184 ;
     RECT  23.605 59.184 23.676 59.208 ;
     RECT  23.605 59.208 23.724 59.376 ;
     RECT  23.605 59.376 23.676 59.4 ;
     RECT  23.605 59.4 23.724 59.568 ;
     RECT  23.605 59.568 23.676 59.592 ;
     RECT  23.605 59.592 23.724 59.76 ;
     RECT  23.605 59.76 23.676 59.784 ;
     RECT  23.605 59.784 23.724 59.952 ;
     RECT  23.605 59.952 23.676 59.976 ;
     RECT  23.605 59.976 23.724 60.144 ;
     RECT  23.605 60.144 23.676 60.168 ;
     RECT  23.605 60.168 23.724 60.336 ;
     RECT  23.605 60.336 23.676 60.36 ;
     RECT  23.605 60.36 23.724 60.528 ;
     RECT  23.605 60.528 23.676 60.552 ;
     RECT  23.605 60.552 23.724 60.72 ;
     RECT  23.605 60.72 23.676 60.744 ;
     RECT  23.605 60.744 23.724 60.912 ;
     RECT  23.605 60.912 23.676 60.936 ;
     RECT  23.605 60.936 23.724 61.104 ;
     RECT  23.605 61.104 23.676 61.128 ;
     RECT  23.605 61.128 23.724 61.296 ;
     RECT  23.605 61.296 23.676 61.32 ;
     RECT  23.605 61.32 23.724 61.488 ;
     RECT  23.605 61.488 23.676 61.512 ;
     RECT  23.605 61.512 23.724 61.68 ;
     RECT  23.605 61.68 23.676 61.704 ;
     RECT  23.605 61.704 23.724 61.872 ;
     RECT  23.605 61.872 23.676 61.896 ;
     RECT  23.605 61.896 23.724 62.064 ;
     RECT  23.605 62.064 23.676 62.088 ;
     RECT  23.605 62.088 23.724 62.256 ;
     RECT  23.605 62.256 23.676 62.28 ;
     RECT  23.605 62.28 23.724 62.448 ;
     RECT  23.605 62.448 23.676 62.472 ;
     RECT  23.605 62.472 23.724 62.64 ;
     RECT  23.605 62.64 23.676 62.664 ;
     RECT  23.605 62.664 23.724 62.832 ;
     RECT  23.605 62.832 23.676 62.856 ;
     RECT  23.605 62.856 23.724 63.024 ;
     RECT  23.605 63.024 23.676 63.048 ;
     RECT  23.605 63.048 23.724 63.216 ;
     RECT  23.605 63.216 23.676 63.24 ;
     RECT  23.605 63.24 23.724 63.408 ;
     RECT  23.605 63.408 23.676 63.432 ;
     RECT  23.605 63.432 23.724 63.6 ;
     RECT  23.605 63.6 23.676 63.624 ;
     RECT  23.605 63.624 23.724 63.792 ;
     RECT  23.605 63.792 23.676 63.816 ;
     RECT  23.605 63.816 23.724 63.984 ;
     RECT  23.605 63.984 23.676 64.008 ;
     RECT  23.605 64.008 23.724 64.176 ;
     RECT  23.605 64.176 23.676 64.2 ;
     RECT  23.605 64.2 23.724 64.368 ;
     RECT  23.605 64.368 23.676 64.392 ;
     RECT  23.605 64.392 23.724 64.56 ;
     RECT  23.605 64.56 23.676 64.584 ;
     RECT  23.605 64.584 23.724 64.752 ;
     RECT  23.605 64.752 23.676 64.776 ;
     RECT  23.605 64.776 23.724 64.944 ;
     RECT  23.605 64.944 23.676 64.968 ;
     RECT  23.605 64.968 23.724 65.136 ;
     RECT  23.605 65.136 23.676 65.16 ;
     RECT  23.605 65.16 23.724 65.328 ;
     RECT  23.605 65.328 23.676 65.352 ;
     RECT  23.605 65.352 23.724 65.52 ;
     RECT  23.605 65.52 23.676 65.544 ;
     RECT  23.605 65.544 23.724 65.712 ;
     RECT  23.605 65.712 23.676 65.736 ;
     RECT  23.605 65.736 23.724 65.904 ;
     RECT  23.605 65.904 23.676 65.928 ;
     RECT  23.605 65.928 23.724 66.096 ;
     RECT  23.605 66.096 23.676 66.12 ;
     RECT  23.605 66.12 23.724 66.288 ;
     RECT  23.605 66.288 23.676 66.312 ;
     RECT  23.605 66.312 23.724 66.48 ;
     RECT  23.605 66.48 23.676 66.504 ;
     RECT  23.605 66.504 23.724 66.672 ;
     RECT  23.605 66.672 23.676 66.696 ;
     RECT  23.605 66.696 23.724 66.864 ;
     RECT  23.605 66.864 23.676 66.888 ;
     RECT  23.605 66.888 23.724 67.056 ;
     RECT  23.605 67.056 23.676 67.08 ;
     RECT  23.605 67.08 23.724 67.248 ;
     RECT  23.605 67.248 23.676 67.272 ;
     RECT  23.605 67.272 23.724 67.44 ;
     RECT  23.605 67.44 23.676 67.464 ;
     RECT  23.605 67.464 23.724 67.632 ;
     RECT  23.605 67.632 23.676 67.656 ;
     RECT  23.605 67.656 23.724 67.824 ;
     RECT  23.605 67.824 23.676 67.848 ;
     RECT  23.605 67.848 23.724 68.016 ;
     RECT  23.605 68.016 23.676 68.04 ;
     RECT  23.605 68.04 23.724 68.208 ;
     RECT  23.605 68.208 23.676 68.232 ;
     RECT  23.605 68.232 23.724 68.4 ;
     RECT  23.605 68.4 23.676 68.424 ;
     RECT  23.605 68.424 23.724 68.592 ;
     RECT  23.605 68.592 23.676 68.616 ;
     RECT  23.605 68.616 23.724 68.784 ;
     RECT  23.605 68.784 23.676 68.808 ;
     RECT  23.605 68.808 23.724 68.976 ;
     RECT  23.605 68.976 23.676 69 ;
     RECT  23.605 69 23.724 69.168 ;
     RECT  23.605 69.168 23.676 69.192 ;
     RECT  23.605 69.192 23.724 69.36 ;
     RECT  23.605 69.36 23.676 69.384 ;
     RECT  23.605 69.384 23.724 69.552 ;
     RECT  23.605 69.552 23.676 69.576 ;
     RECT  23.605 69.576 23.724 69.744 ;
     RECT  23.605 69.744 23.676 69.768 ;
     RECT  23.605 69.768 23.724 69.936 ;
     RECT  23.605 69.936 23.676 69.96 ;
     RECT  23.605 69.96 23.724 70.128 ;
     RECT  23.605 70.128 23.676 70.152 ;
     RECT  23.605 70.152 23.724 70.32 ;
     RECT  23.605 70.32 23.676 70.344 ;
     RECT  23.605 70.344 23.724 70.512 ;
     RECT  23.605 70.512 23.676 70.536 ;
     RECT  23.605 70.536 23.724 70.704 ;
     RECT  23.605 70.704 23.676 70.728 ;
     RECT  23.605 70.728 23.724 70.896 ;
     RECT  23.605 70.896 23.676 70.92 ;
     RECT  23.605 70.92 23.724 71.088 ;
     RECT  23.605 71.088 23.676 71.112 ;
     RECT  23.605 71.112 23.724 71.28 ;
     RECT  23.605 71.28 23.676 71.304 ;
     RECT  23.605 71.304 23.724 71.472 ;
     RECT  23.605 71.472 23.676 71.496 ;
     RECT  23.605 71.496 23.724 71.664 ;
     RECT  23.605 71.664 23.676 71.688 ;
     RECT  23.605 71.688 23.724 71.856 ;
     RECT  23.605 71.856 23.676 71.88 ;
     RECT  23.605 71.88 23.724 72.048 ;
     RECT  23.605 72.048 23.676 72.072 ;
     RECT  23.605 72.072 23.724 72.24 ;
     RECT  23.605 72.24 23.676 72.264 ;
     RECT  23.605 72.264 23.724 72.432 ;
     RECT  23.605 72.432 23.676 72.456 ;
     RECT  23.605 72.456 23.724 72.624 ;
     RECT  23.605 72.624 23.676 72.648 ;
     RECT  23.605 72.648 23.724 72.816 ;
     RECT  23.605 72.816 23.676 72.84 ;
     RECT  23.605 72.84 23.724 73.008 ;
     RECT  23.605 73.008 23.676 73.032 ;
     RECT  23.605 73.032 23.724 73.2 ;
     RECT  23.605 73.2 23.676 73.224 ;
     RECT  23.605 73.224 23.724 73.392 ;
     RECT  23.605 73.392 23.676 73.416 ;
     RECT  23.605 73.416 23.724 73.584 ;
     RECT  23.605 73.584 23.676 73.608 ;
     RECT  23.605 73.608 23.724 73.776 ;
     RECT  23.605 73.776 23.676 73.8 ;
     RECT  23.605 73.8 23.724 73.968 ;
     RECT  23.605 73.968 23.676 73.992 ;
     RECT  23.605 73.992 23.724 74.16 ;
     RECT  23.605 74.16 23.676 74.184 ;
     RECT  23.605 74.184 23.724 74.352 ;
     RECT  23.605 74.352 23.676 74.376 ;
     RECT  23.605 74.376 23.724 74.544 ;
     RECT  23.605 74.544 23.676 74.568 ;
     RECT  23.605 74.568 23.724 74.736 ;
     RECT  23.605 74.736 23.676 74.76 ;
     RECT  23.605 74.76 23.724 74.928 ;
     RECT  23.605 74.928 23.676 74.952 ;
     RECT  23.605 74.952 23.724 75.12 ;
     RECT  23.605 75.12 23.676 75.144 ;
     RECT  23.605 75.144 23.724 75.312 ;
     RECT  23.605 75.312 23.676 75.336 ;
     RECT  23.605 75.336 23.724 75.504 ;
     RECT  23.605 75.504 23.676 75.528 ;
     RECT  23.605 75.528 23.724 75.696 ;
     RECT  23.605 75.696 23.676 75.72 ;
     RECT  23.605 75.72 23.724 75.888 ;
     RECT  23.605 75.888 23.676 75.912 ;
     RECT  23.605 75.912 23.724 76.08 ;
     RECT  23.605 76.08 23.676 76.104 ;
     RECT  23.605 76.104 23.724 76.272 ;
     RECT  23.605 76.272 23.676 76.296 ;
     RECT  23.605 76.296 23.724 76.464 ;
     RECT  23.605 76.464 23.676 76.488 ;
     RECT  23.605 76.488 23.724 76.656 ;
     RECT  23.605 76.656 23.676 76.68 ;
     RECT  23.605 76.68 23.724 76.848 ;
     RECT  23.605 76.848 23.676 76.872 ;
     RECT  23.605 76.872 23.724 77.04 ;
     RECT  23.605 77.04 23.676 77.064 ;
     RECT  23.605 77.064 23.724 77.232 ;
     RECT  23.605 77.232 23.676 77.256 ;
     RECT  23.605 77.256 23.724 77.424 ;
     RECT  23.605 77.424 23.676 77.448 ;
     RECT  23.605 77.448 23.724 77.616 ;
     RECT  23.605 77.616 23.676 77.64 ;
     RECT  23.605 77.64 23.724 77.808 ;
     RECT  23.605 77.808 23.676 77.832 ;
     RECT  23.605 77.832 23.724 78 ;
     RECT  23.605 78 23.676 78.024 ;
     RECT  23.605 78.024 23.724 78.192 ;
     RECT  23.605 78.192 23.676 78.216 ;
     RECT  23.605 78.216 23.724 78.384 ;
     RECT  23.605 78.384 23.676 78.408 ;
     RECT  23.605 78.408 23.724 78.576 ;
     RECT  23.605 78.576 23.676 78.6 ;
     RECT  23.605 78.6 23.724 78.768 ;
     RECT  23.605 78.768 23.676 78.792 ;
     RECT  23.605 78.792 23.724 78.96 ;
     RECT  23.605 78.96 23.676 78.984 ;
     RECT  23.605 78.984 23.724 79.152 ;
     RECT  23.605 79.152 23.676 79.176 ;
     RECT  23.605 79.176 23.724 79.344 ;
     RECT  23.605 79.344 23.676 79.368 ;
     RECT  23.605 79.368 23.724 79.536 ;
     RECT  23.605 79.536 23.676 79.56 ;
     RECT  23.605 79.56 23.724 79.776 ;
     RECT  23.605 79.776 23.676 79.8 ;
     RECT  23.605 79.8 23.724 79.968 ;
     RECT  23.605 79.968 23.676 79.992 ;
     RECT  23.605 79.992 23.724 80.16 ;
     RECT  23.605 80.16 23.676 80.184 ;
     RECT  23.605 80.184 23.724 80.352 ;
     RECT  23.605 80.352 23.676 80.376 ;
     RECT  23.605 80.376 23.724 80.544 ;
     RECT  23.605 80.544 23.676 80.568 ;
     RECT  23.605 80.568 23.724 80.736 ;
     RECT  23.605 80.736 23.676 80.76 ;
     RECT  23.605 80.76 23.724 80.928 ;
     RECT  23.605 80.928 23.676 80.952 ;
     RECT  23.605 80.952 23.724 81.12 ;
     RECT  23.605 81.12 23.676 81.144 ;
     RECT  23.605 81.144 23.724 81.312 ;
     RECT  23.605 81.312 23.676 81.336 ;
     RECT  23.605 81.336 23.724 81.504 ;
     RECT  23.605 81.504 23.676 81.528 ;
     RECT  23.605 81.528 23.724 81.696 ;
     RECT  23.605 81.696 23.676 81.72 ;
     RECT  23.605 81.72 23.724 81.888 ;
     RECT  23.605 81.888 23.676 81.912 ;
     RECT  23.605 81.912 23.724 82.08 ;
     RECT  23.605 82.08 23.676 82.104 ;
     RECT  23.605 82.104 23.724 82.272 ;
     RECT  23.605 82.272 23.676 82.296 ;
     RECT  23.605 82.296 23.724 82.464 ;
     RECT  23.605 82.464 23.676 82.488 ;
     RECT  23.605 82.488 23.724 82.656 ;
     RECT  23.605 82.656 23.676 82.68 ;
     RECT  23.605 82.68 23.724 82.848 ;
     RECT  23.605 82.848 23.676 82.872 ;
     RECT  23.605 82.872 23.724 83.04 ;
     RECT  23.605 83.04 23.676 83.064 ;
     RECT  23.605 83.064 23.724 83.232 ;
     RECT  23.605 83.232 23.676 83.256 ;
     RECT  23.605 83.256 23.724 83.424 ;
     RECT  23.605 83.424 23.676 83.448 ;
     RECT  23.605 83.448 23.724 83.616 ;
     RECT  23.605 83.616 23.676 83.64 ;
     RECT  23.605 83.64 23.724 83.808 ;
     RECT  23.605 83.808 23.676 83.832 ;
     RECT  23.605 83.832 23.724 84 ;
     RECT  23.605 84 23.676 84.024 ;
     RECT  23.605 84.024 23.724 84.192 ;
     RECT  23.605 84.192 23.676 84.216 ;
     RECT  23.605 84.216 23.724 84.384 ;
     RECT  23.605 84.384 23.676 84.408 ;
     RECT  23.605 84.408 23.724 84.576 ;
     RECT  23.605 84.576 23.676 84.6 ;
     RECT  23.605 84.6 23.724 84.768 ;
     RECT  23.605 84.768 23.676 84.792 ;
     RECT  23.605 84.792 23.724 84.96 ;
     RECT  23.605 84.96 23.676 84.984 ;
     RECT  23.605 84.984 23.724 85.152 ;
     RECT  23.605 85.152 23.676 85.176 ;
     RECT  23.605 85.176 23.724 85.344 ;
     RECT  23.605 85.344 23.676 85.368 ;
     RECT  23.605 85.368 23.724 85.536 ;
     RECT  23.605 85.536 23.676 85.56 ;
     RECT  23.605 85.56 23.724 85.728 ;
     RECT  23.605 85.728 23.676 85.752 ;
     RECT  23.605 85.752 23.724 85.92 ;
     RECT  23.605 85.92 23.676 85.944 ;
     RECT  23.605 85.944 23.724 86.112 ;
     RECT  23.605 86.112 23.676 86.136 ;
     RECT  23.605 86.136 23.724 86.304 ;
     RECT  23.605 86.304 23.676 86.328 ;
     RECT  23.605 86.328 23.724 86.496 ;
     RECT  23.605 86.496 23.676 86.52 ;
     RECT  23.605 86.52 23.724 86.688 ;
     RECT  23.605 86.688 23.676 86.712 ;
     RECT  23.605 86.712 23.724 86.88 ;
     RECT  23.605 86.88 23.676 86.904 ;
     RECT  23.605 86.904 23.724 87.072 ;
     RECT  23.605 87.072 23.676 87.096 ;
     RECT  23.605 87.096 23.724 87.264 ;
     RECT  23.605 87.264 23.676 87.288 ;
     RECT  23.605 87.288 23.724 87.456 ;
     RECT  23.605 87.456 23.676 87.48 ;
     RECT  23.605 87.48 23.724 87.648 ;
     RECT  23.605 87.648 23.676 87.672 ;
     RECT  23.605 87.672 23.724 87.84 ;
     RECT  23.605 87.84 23.676 87.864 ;
     RECT  23.605 87.864 23.724 88.032 ;
     RECT  23.605 88.032 23.676 88.056 ;
     RECT  23.605 88.056 23.724 88.224 ;
     RECT  23.605 88.224 23.676 88.248 ;
     RECT  23.605 88.248 23.724 88.416 ;
     RECT  23.605 88.416 23.676 88.44 ;
     RECT  23.605 88.44 23.724 88.608 ;
     RECT  23.605 88.608 23.676 88.632 ;
     RECT  23.605 88.632 23.724 88.8 ;
     RECT  23.605 88.8 23.676 88.824 ;
     RECT  23.605 88.824 23.724 88.992 ;
     RECT  23.605 88.992 23.676 89.016 ;
     RECT  23.605 89.016 23.724 89.184 ;
     RECT  23.605 89.184 23.676 89.208 ;
     RECT  23.605 89.208 23.724 89.376 ;
     RECT  23.605 89.376 23.676 89.4 ;
     RECT  23.605 89.4 23.724 89.568 ;
     RECT  23.605 89.568 23.676 89.592 ;
     RECT  23.605 89.592 23.724 89.76 ;
     RECT  23.605 89.76 23.676 89.784 ;
     RECT  23.605 89.784 23.724 89.952 ;
     RECT  23.605 89.952 23.676 89.976 ;
     RECT  23.605 89.976 23.724 90.144 ;
     RECT  23.605 90.144 23.676 90.168 ;
     RECT  23.605 90.168 23.724 90.336 ;
     RECT  23.605 90.336 23.676 90.36 ;
     RECT  23.605 90.36 23.724 90.528 ;
     RECT  23.605 90.528 23.676 90.552 ;
     RECT  23.605 90.552 23.724 90.72 ;
     RECT  23.605 90.72 23.676 90.744 ;
     RECT  23.605 90.744 23.724 90.912 ;
     RECT  23.605 90.912 23.676 90.936 ;
     RECT  23.605 90.936 23.724 91.104 ;
     RECT  23.605 91.104 23.676 91.128 ;
     RECT  23.605 91.128 23.724 91.296 ;
     RECT  23.605 91.296 23.676 91.32 ;
     RECT  23.605 91.32 23.724 91.488 ;
     RECT  23.605 91.488 23.676 91.512 ;
     RECT  23.605 91.512 23.724 91.68 ;
     RECT  23.605 91.68 23.676 91.704 ;
     RECT  23.605 91.704 23.724 91.872 ;
     RECT  23.605 91.872 23.676 91.896 ;
     RECT  23.605 91.896 23.724 92.064 ;
     RECT  23.605 92.064 23.676 92.088 ;
     RECT  23.605 92.088 23.724 92.256 ;
     RECT  23.605 92.256 23.676 92.28 ;
     RECT  23.605 92.28 23.724 92.448 ;
     RECT  23.605 92.448 23.676 92.472 ;
     RECT  23.605 92.472 23.724 92.64 ;
     RECT  23.605 92.64 23.676 92.664 ;
     RECT  23.605 92.664 23.724 92.832 ;
     RECT  23.605 92.832 23.676 92.856 ;
     RECT  23.605 92.856 23.724 93.024 ;
     RECT  23.605 93.024 23.676 93.048 ;
     RECT  23.605 93.048 23.724 93.216 ;
     RECT  23.605 93.216 23.676 93.24 ;
     RECT  23.605 93.24 23.724 93.408 ;
     RECT  23.605 93.408 23.676 93.432 ;
     RECT  23.605 93.432 23.724 93.6 ;
     RECT  23.605 93.6 23.676 93.624 ;
     RECT  23.605 93.624 23.724 93.792 ;
     RECT  23.605 93.792 23.676 93.816 ;
     RECT  23.605 93.816 23.724 93.984 ;
     RECT  23.605 93.984 23.676 94.008 ;
     RECT  23.605 94.008 23.724 94.176 ;
     RECT  23.605 94.176 23.676 94.2 ;
     RECT  23.605 94.2 23.724 94.368 ;
     RECT  23.605 94.368 23.676 94.392 ;
     RECT  23.605 94.392 23.724 94.56 ;
     RECT  23.605 94.56 23.676 94.584 ;
     RECT  23.605 94.584 23.724 94.752 ;
     RECT  23.605 94.752 23.676 94.776 ;
     RECT  23.605 94.776 23.724 95.184 ;
     RECT  23.605 95.184 23.676 95.208 ;
     RECT  23.605 95.208 23.724 95.424 ;
     RECT  23.605 95.424 23.676 95.448 ;
     RECT  23.605 95.448 23.724 95.664 ;
     RECT  23.605 95.664 23.676 95.688 ;
     RECT  23.605 95.688 23.724 95.952 ;
     RECT  23.605 95.952 23.676 95.976 ;
     RECT  23.605 95.976 23.724 96.192 ;
     RECT  23.605 96.192 23.676 96.216 ;
     RECT  23.605 96.216 23.724 96.432 ;
     RECT  23.605 96.432 23.676 96.456 ;
     RECT  23.605 96.456 23.724 96.672 ;
     RECT  23.605 96.672 23.676 96.696 ;
     RECT  23.605 96.696 23.724 96.912 ;
     RECT  23.605 96.912 23.676 96.936 ;
     RECT  23.605 96.936 23.724 97.2 ;
     RECT  23.605 97.2 23.676 97.224 ;
     RECT  23.605 97.224 23.724 97.44 ;
     RECT  23.605 97.44 23.676 97.464 ;
     RECT  23.605 97.464 23.724 97.68 ;
     RECT  23.605 97.68 23.676 97.704 ;
     RECT  23.605 97.704 23.724 97.92 ;
     RECT  23.605 97.92 23.676 97.944 ;
     RECT  23.605 97.944 23.724 98.16 ;
     RECT  23.605 98.16 23.676 98.184 ;
     RECT  23.605 98.184 23.724 98.448 ;
     RECT  23.605 98.448 23.676 98.472 ;
     RECT  23.605 98.472 23.724 98.688 ;
     RECT  23.605 98.688 23.676 98.712 ;
    LAYER M5 ;
     RECT  2.4 2.137 2.52 2.151 ;
     RECT  7.8 2.137 7.92 2.151 ;
     RECT  13.2 2.137 13.32 2.151 ;
     RECT  18.6 2.137 18.72 2.151 ;
     RECT  18.6 2.151 18.912 2.341 ;
     RECT  11.808 2.389 11.832 2.677 ;
     RECT  13.2 2.151 13.512 2.677 ;
     RECT  9.264 2.725 9.288 2.821 ;
     RECT  17.088 2.485 17.112 2.821 ;
     RECT  18.6 2.341 19.464 2.821 ;
     RECT  17.088 2.821 19.464 2.869 ;
     RECT  11.808 2.677 13.512 2.965 ;
     RECT  5.904 2.197 5.928 3.013 ;
     RECT  5.904 3.013 6.072 3.109 ;
     RECT  11.568 2.965 13.512 3.253 ;
     RECT  11.568 3.253 13.8 3.445 ;
     RECT  11.04 3.445 13.8 3.589 ;
     RECT  11.04 3.589 13.944 3.683 ;
     RECT  9.264 2.821 9.816 3.685 ;
     RECT  15.696 3.397 15.72 3.685 ;
     RECT  16.752 2.869 19.464 3.685 ;
     RECT  4.464 3.205 4.488 3.733 ;
     RECT  5.616 3.109 6.072 3.781 ;
     RECT  4.368 3.733 4.488 3.877 ;
     RECT  5.616 3.781 6.312 3.877 ;
     RECT  7.8 2.151 8.112 4.021 ;
     RECT  9.168 3.685 9.816 4.021 ;
     RECT  11.712 3.683 13.944 4.021 ;
     RECT  11.712 4.021 13.992 4.069 ;
     RECT  15.696 3.685 19.464 4.069 ;
     RECT  4.368 3.877 6.312 4.117 ;
     RECT  7.8 4.021 9.816 4.117 ;
     RECT  11.712 4.069 19.464 4.837 ;
     RECT  2.4 2.151 2.712 4.885 ;
     RECT  11.04 4.837 19.464 5.075 ;
     RECT  2.4 4.885 3.336 5.125 ;
     RECT  4.368 4.117 9.816 5.125 ;
     RECT  11.232 5.075 19.464 5.557 ;
     RECT  2.4 5.125 9.816 5.701 ;
     RECT  2.4 5.701 9.912 5.747 ;
     RECT  5.472 5.747 9.912 5.941 ;
     RECT  5.472 5.941 10.056 6.133 ;
     RECT  11.232 5.557 19.704 6.133 ;
     RECT  2.4 5.747 4.488 7.237 ;
     RECT  5.472 6.133 19.704 7.237 ;
     RECT  2.4 7.237 19.704 9.301 ;
     RECT  2.208 9.301 19.704 9.493 ;
     RECT  1.104 9.061 1.128 18.997 ;
     RECT  1.056 18.997 1.128 22.453 ;
     RECT  2.16 9.493 20.664 24.181 ;
     RECT  1.008 22.453 1.128 27.637 ;
     RECT  0.528 27.637 1.128 28.789 ;
     RECT  2.112 24.181 20.664 28.789 ;
     RECT  0.528 28.789 20.664 28.981 ;
     RECT  0.48 28.981 20.664 29.029 ;
     RECT  0.48 29.029 21.048 30.709 ;
     RECT  0.48 30.709 21.48 32.051 ;
     RECT  0.48 32.051 20.664 34.979 ;
     RECT  0.48 34.979 20.616 37.667 ;
     RECT  0.48 37.667 20.568 38.965 ;
     RECT  0.48 38.965 20.76 39.109 ;
     RECT  0.48 39.109 20.808 46.597 ;
     RECT  0.48 46.597 21.144 47.269 ;
     RECT  0.48 47.269 21.192 51.109 ;
     RECT  0.48 51.109 21.816 51.685 ;
     RECT  0.48 51.685 22.392 51.875 ;
     RECT  0.48 51.875 22.296 55.141 ;
     RECT  0.48 55.141 22.344 70.453 ;
     RECT  0.144 70.453 22.344 70.835 ;
     RECT  0.48 70.835 22.344 84.659 ;
     RECT  0.528 84.659 22.344 86.291 ;
     RECT  0.528 86.291 20.568 87.923 ;
     RECT  21.792 86.291 22.344 88.115 ;
     RECT  21.792 88.115 22.248 88.163 ;
     RECT  0.528 87.923 15.624 88.307 ;
     RECT  0.528 88.307 11.496 88.979 ;
     RECT  12.528 88.307 15.624 89.219 ;
     RECT  16.608 87.923 20.568 89.459 ;
     RECT  0.528 88.979 4.536 89.555 ;
     RECT  5.712 88.979 11.496 89.699 ;
     RECT  0.528 89.555 4.344 89.795 ;
     RECT  16.944 89.459 20.568 89.843 ;
     RECT  12.864 89.219 15.624 90.083 ;
     RECT  2.256 89.795 4.344 90.515 ;
     RECT  5.712 89.699 11.304 90.515 ;
     RECT  6.144 90.515 11.304 90.755 ;
     RECT  6.144 90.755 11.016 90.803 ;
     RECT  14.832 90.083 15.624 90.851 ;
     RECT  6.144 90.803 9.72 90.899 ;
     RECT  10.992 90.803 11.016 91.187 ;
     RECT  2.256 90.515 3.816 91.235 ;
     RECT  16.944 89.843 19.464 91.235 ;
     RECT  20.544 89.843 20.568 91.475 ;
     RECT  2.256 91.235 3.768 91.811 ;
     RECT  0.528 89.795 1.08 92.003 ;
     RECT  17.328 91.235 19.464 92.243 ;
     RECT  17.328 92.243 18.912 92.387 ;
     RECT  12.864 90.083 13.512 92.389 ;
     RECT  15.504 90.851 15.624 92.629 ;
     RECT  6.672 90.899 9.72 92.675 ;
     RECT  12.864 92.389 14.136 92.675 ;
     RECT  12.864 92.675 13.512 93.011 ;
     RECT  15.504 92.629 15.672 93.059 ;
     RECT  15.648 93.059 15.672 93.251 ;
     RECT  17.328 92.387 17.352 93.445 ;
     RECT  17.136 93.445 17.352 93.491 ;
     RECT  1.008 92.003 1.08 93.539 ;
     RECT  6.72 92.675 9.72 93.539 ;
     RECT  17.136 93.491 17.16 94.019 ;
     RECT  7.8 93.539 9.72 94.021 ;
     RECT  10.944 93.685 10.968 94.021 ;
     RECT  13.2 93.011 13.512 94.069 ;
     RECT  18.6 92.387 18.912 94.837 ;
     RECT  2.256 91.811 3.48 95.219 ;
     RECT  7.8 94.021 11.16 95.219 ;
     RECT  6.72 93.539 6.744 95.365 ;
     RECT  6.096 95.365 6.744 95.411 ;
     RECT  7.8 95.219 10.248 95.555 ;
     RECT  9.408 95.555 10.248 95.651 ;
     RECT  17.712 94.837 18.912 95.747 ;
     RECT  2.256 95.219 2.712 95.795 ;
     RECT  14.496 93.205 14.52 95.891 ;
     RECT  13.104 94.069 13.512 96.227 ;
     RECT  10.224 95.651 10.248 96.419 ;
     RECT  1.056 93.539 1.08 96.755 ;
     RECT  6.096 95.411 6.12 96.755 ;
     RECT  17.328 96.325 17.352 97.379 ;
     RECT  18.6 95.747 18.912 97.525 ;
     RECT  7.8 95.555 8.112 98.149 ;
     RECT  18.48 97.525 18.912 98.869 ;
     RECT  2.4 95.795 2.712 99.157 ;
     RECT  7.8 98.149 8.568 99.157 ;
     RECT  13.2 96.227 13.512 99.157 ;
     RECT  18.048 98.869 18.912 99.157 ;
     RECT  21.792 88.163 21.816 99.157 ;
     RECT  2.4 99.157 4.872 99.383 ;
     RECT  13.2 99.157 21.816 99.637 ;
     RECT  2.592 99.383 4.872 99.685 ;
     RECT  6.096 99.157 8.568 99.685 ;
     RECT  10.8 99.157 10.824 99.685 ;
     RECT  11.808 99.589 11.832 99.685 ;
     RECT  13.056 99.637 21.816 99.685 ;
     RECT  2.592 99.685 21.816 100.885 ;
     RECT  2.592 100.885 22.296 101.365 ;
     RECT  23.28 100.885 23.304 101.365 ;
     RECT  2.592 101.365 23.304 101.436 ;
     RECT  2.616 101.436 2.88 101.456 ;
     RECT  2.904 101.436 3.12 101.456 ;
     RECT  3.144 101.436 3.36 101.456 ;
     RECT  3.384 101.436 3.6 101.456 ;
     RECT  3.624 101.436 3.84 101.456 ;
     RECT  3.864 101.436 4.128 101.456 ;
     RECT  4.152 101.436 4.368 101.456 ;
     RECT  4.392 101.436 4.608 101.456 ;
     RECT  4.632 101.436 4.848 101.456 ;
     RECT  4.872 101.436 5.136 101.456 ;
     RECT  5.16 101.436 5.376 101.456 ;
     RECT  5.4 101.436 5.616 101.456 ;
     RECT  5.64 101.436 5.856 101.456 ;
     RECT  5.88 101.436 6.096 101.456 ;
     RECT  6.12 101.436 6.576 101.456 ;
     RECT  6.6 101.436 6.816 101.456 ;
     RECT  6.84 101.436 7.056 101.456 ;
     RECT  7.08 101.436 7.296 101.456 ;
     RECT  7.32 101.436 7.584 101.456 ;
     RECT  7.608 101.436 7.824 101.456 ;
     RECT  7.848 101.436 8.064 101.456 ;
     RECT  8.088 101.436 8.304 101.456 ;
     RECT  8.328 101.436 8.544 101.456 ;
     RECT  8.568 101.436 8.832 101.456 ;
     RECT  8.856 101.436 9.072 101.456 ;
     RECT  9.096 101.436 9.312 101.456 ;
     RECT  9.336 101.436 9.552 101.456 ;
     RECT  9.576 101.436 9.792 101.456 ;
     RECT  9.816 101.436 10.08 101.456 ;
     RECT  10.104 101.436 10.32 101.456 ;
     RECT  10.344 101.436 10.56 101.456 ;
     RECT  10.584 101.436 10.8 101.456 ;
     RECT  10.824 101.436 11.04 101.456 ;
     RECT  11.064 101.436 11.328 101.456 ;
     RECT  11.352 101.436 11.568 101.456 ;
     RECT  11.592 101.436 11.808 101.456 ;
     RECT  11.832 101.436 12.048 101.456 ;
     RECT  12.072 101.436 12.336 101.456 ;
     RECT  12.36 101.436 12.576 101.456 ;
     RECT  12.6 101.436 12.816 101.456 ;
     RECT  12.84 101.436 13.056 101.456 ;
     RECT  13.08 101.436 13.296 101.456 ;
     RECT  13.32 101.436 13.584 101.456 ;
     RECT  13.608 101.436 13.824 101.456 ;
     RECT  13.848 101.436 14.064 101.456 ;
     RECT  14.088 101.436 14.304 101.456 ;
     RECT  14.328 101.436 14.544 101.456 ;
     RECT  14.568 101.436 14.832 101.456 ;
     RECT  14.856 101.436 15.072 101.456 ;
     RECT  15.096 101.436 15.312 101.456 ;
     RECT  15.336 101.436 15.552 101.456 ;
     RECT  15.576 101.436 15.792 101.456 ;
     RECT  15.816 101.436 16.08 101.456 ;
     RECT  16.104 101.436 16.32 101.456 ;
     RECT  16.344 101.436 16.56 101.456 ;
     RECT  16.584 101.436 16.8 101.456 ;
     RECT  16.824 101.436 17.04 101.456 ;
     RECT  17.064 101.436 17.328 101.456 ;
     RECT  17.352 101.436 17.568 101.456 ;
     RECT  17.592 101.436 17.808 101.456 ;
     RECT  17.832 101.436 18.048 101.456 ;
     RECT  18.072 101.436 18.336 101.456 ;
     RECT  18.36 101.436 18.576 101.456 ;
     RECT  18.6 101.436 18.816 101.456 ;
     RECT  18.84 101.436 19.056 101.456 ;
     RECT  19.08 101.436 19.296 101.456 ;
     RECT  19.32 101.436 19.584 101.456 ;
     RECT  19.608 101.436 19.824 101.456 ;
     RECT  19.848 101.436 20.064 101.456 ;
     RECT  20.088 101.436 20.304 101.456 ;
     RECT  20.328 101.436 20.544 101.456 ;
     RECT  20.568 101.436 20.832 101.456 ;
     RECT  20.856 101.436 21.072 101.456 ;
     RECT  21.096 101.436 21.312 101.456 ;
     RECT  21.336 101.436 21.792 101.456 ;
     RECT  21.816 101.436 22.272 101.456 ;
     RECT  22.296 101.436 22.8 101.456 ;
     RECT  22.824 101.436 23.28 101.456 ;
     RECT  11.832 2.389 13.2 2.677 ;
     RECT  17.112 2.485 18.6 2.821 ;
     RECT  8.112 2.725 9.264 3.685 ;
     RECT  4.488 3.205 5.616 3.877 ;
     RECT  15.72 3.397 16.752 3.685 ;
     RECT  9.816 3.445 11.04 3.683 ;
     RECT  9.816 3.683 11.712 4.837 ;
     RECT  8.112 3.685 9.168 4.021 ;
     RECT  6.312 3.781 7.8 4.117 ;
     RECT  9.816 4.837 11.04 5.075 ;
     RECT  3.336 4.885 4.368 5.125 ;
     RECT  9.816 5.075 11.232 5.701 ;
     RECT  9.912 5.701 11.232 5.941 ;
     RECT  4.488 5.747 5.472 7.237 ;
     RECT  10.056 5.941 11.232 6.133 ;
     RECT  1.128 9.061 2.4 9.301 ;
     RECT  1.128 9.301 2.208 9.493 ;
     RECT  1.128 9.493 2.16 24.181 ;
     RECT  1.128 24.181 2.112 28.789 ;
     RECT  20.568 37.667 20.616 38.965 ;
     RECT  20.568 86.291 21.792 91.475 ;
     RECT  15.624 87.923 16.608 89.459 ;
     RECT  11.496 88.307 12.528 89.219 ;
     RECT  4.536 88.979 5.712 89.555 ;
     RECT  11.496 89.219 12.864 89.699 ;
     RECT  15.624 89.459 16.944 91.235 ;
     RECT  4.344 89.555 5.712 90.515 ;
     RECT  1.08 89.795 2.256 95.795 ;
     RECT  19.464 89.843 20.544 91.475 ;
     RECT  13.512 90.083 14.832 90.851 ;
     RECT  9.72 90.803 10.992 91.187 ;
     RECT  15.624 91.235 15.672 92.629 ;
     RECT  17.352 92.387 18.6 93.491 ;
     RECT  14.136 92.389 15.504 92.675 ;
     RECT  13.512 92.675 15.504 93.059 ;
     RECT  13.104 93.011 13.2 94.069 ;
     RECT  13.512 93.059 15.648 93.205 ;
     RECT  13.512 93.205 14.496 95.891 ;
     RECT  14.52 93.205 15.648 93.251 ;
     RECT  17.16 93.491 18.6 94.019 ;
     RECT  6.744 93.539 7.8 95.411 ;
     RECT  9.72 93.685 10.944 94.021 ;
     RECT  17.712 94.019 18.6 94.837 ;
     RECT  8.112 95.555 9.408 95.651 ;
     RECT  17.712 95.747 18.6 96.325 ;
     RECT  1.08 95.795 2.4 96.755 ;
     RECT  17.352 96.325 18.6 97.379 ;
     RECT  18.048 97.379 18.6 97.525 ;
     RECT  18.048 97.525 18.48 98.869 ;
     RECT  4.872 99.157 6.096 99.685 ;
     RECT  10.824 99.589 11.808 99.685 ;
     RECT  11.832 99.589 13.2 99.637 ;
     RECT  11.832 99.637 13.056 99.685 ;
     RECT  22.296 100.885 23.28 101.365 ;
  END
END ot_hgi_coll_qso_q2_b32
END LIBRARY
